VERSION 5.8 ;
BUSBITCHARS "[]" ;
DIVIDERCHAR "/" ;
UNITS
    DATABASE MICRONS 1000 ;
END UNITS

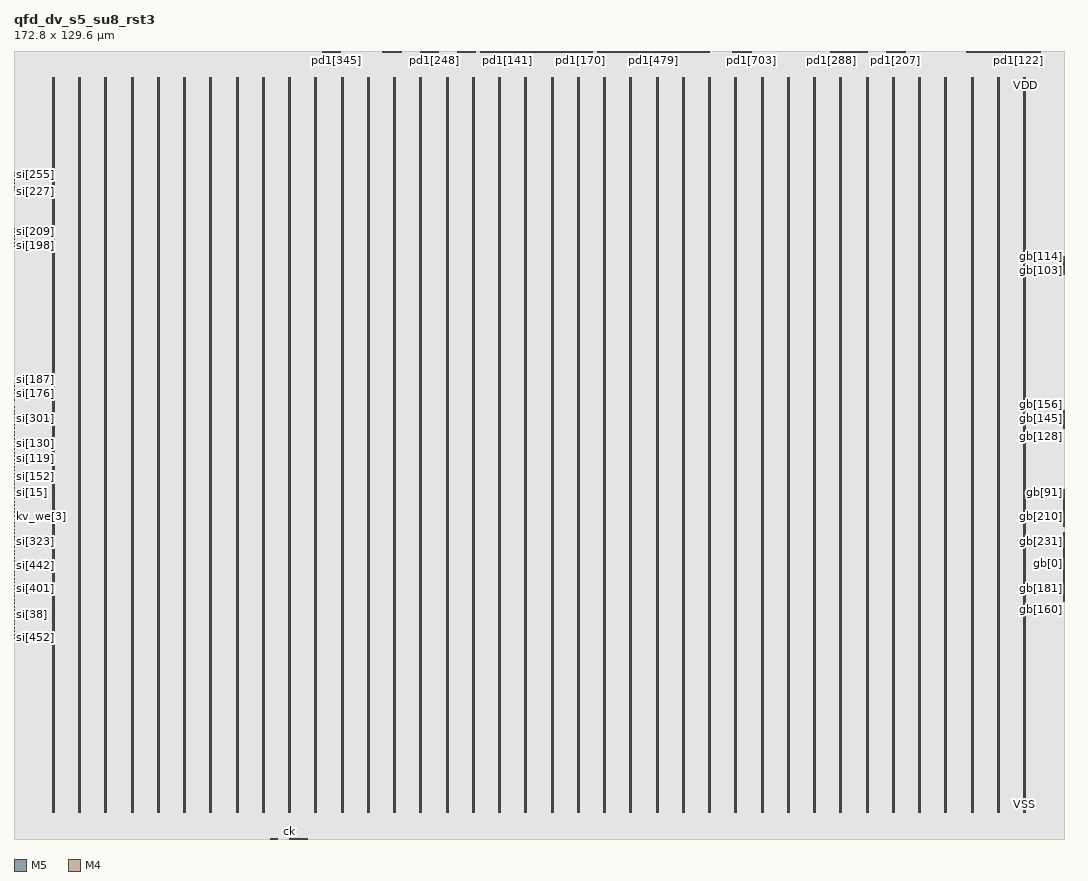
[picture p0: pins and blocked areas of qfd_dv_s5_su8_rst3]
MACRO qfd_dv_s5_su8_rst3
  FOREIGN qfd_dv_s5_su8_rst3 0 0 ;
  CLASS BLOCK ;
  SIZE 172.8 BY 129.6 ;
  PIN ck
    DIRECTION INPUT ;
    USE SIGNAL ;
    PORT
      LAYER M5 ;
        RECT  45.264 0 45.288 0.084 ;
    END
  END ck
  PIN gb[0]
    DIRECTION OUTPUT ;
    USE SIGNAL ;
    PORT
      LAYER M4 ;
        RECT  172.716 45.264 172.8 45.288 ;
    END
  END gb[0]
  PIN gb[100]
    DIRECTION OUTPUT ;
    USE SIGNAL ;
    PORT
      LAYER M4 ;
        RECT  172.716 93.264 172.8 93.288 ;
    END
  END gb[100]
  PIN gb[101]
    DIRECTION OUTPUT ;
    USE SIGNAL ;
    PORT
      LAYER M4 ;
        RECT  172.716 93.36 172.8 93.384 ;
    END
  END gb[101]
  PIN gb[102]
    DIRECTION OUTPUT ;
    USE SIGNAL ;
    PORT
      LAYER M4 ;
        RECT  172.716 93.456 172.8 93.48 ;
    END
  END gb[102]
  PIN gb[103]
    DIRECTION OUTPUT ;
    USE SIGNAL ;
    PORT
      LAYER M4 ;
        RECT  172.716 93.552 172.8 93.576 ;
    END
  END gb[103]
  PIN gb[104]
    DIRECTION OUTPUT ;
    USE SIGNAL ;
    PORT
      LAYER M4 ;
        RECT  172.716 93.648 172.8 93.672 ;
    END
  END gb[104]
  PIN gb[105]
    DIRECTION OUTPUT ;
    USE SIGNAL ;
    PORT
      LAYER M4 ;
        RECT  172.716 93.744 172.8 93.768 ;
    END
  END gb[105]
  PIN gb[106]
    DIRECTION OUTPUT ;
    USE SIGNAL ;
    PORT
      LAYER M4 ;
        RECT  172.716 93.84 172.8 93.864 ;
    END
  END gb[106]
  PIN gb[107]
    DIRECTION OUTPUT ;
    USE SIGNAL ;
    PORT
      LAYER M4 ;
        RECT  172.716 93.936 172.8 93.96 ;
    END
  END gb[107]
  PIN gb[108]
    DIRECTION OUTPUT ;
    USE SIGNAL ;
    PORT
      LAYER M4 ;
        RECT  172.716 94.032 172.8 94.056 ;
    END
  END gb[108]
  PIN gb[109]
    DIRECTION OUTPUT ;
    USE SIGNAL ;
    PORT
      LAYER M4 ;
        RECT  172.716 94.128 172.8 94.152 ;
    END
  END gb[109]
  PIN gb[10]
    DIRECTION OUTPUT ;
    USE SIGNAL ;
    PORT
      LAYER M4 ;
        RECT  172.716 46.224 172.8 46.248 ;
    END
  END gb[10]
  PIN gb[110]
    DIRECTION OUTPUT ;
    USE SIGNAL ;
    PORT
      LAYER M4 ;
        RECT  172.716 94.224 172.8 94.248 ;
    END
  END gb[110]
  PIN gb[111]
    DIRECTION OUTPUT ;
    USE SIGNAL ;
    PORT
      LAYER M4 ;
        RECT  172.716 94.32 172.8 94.344 ;
    END
  END gb[111]
  PIN gb[112]
    DIRECTION OUTPUT ;
    USE SIGNAL ;
    PORT
      LAYER M4 ;
        RECT  172.716 94.416 172.8 94.44 ;
    END
  END gb[112]
  PIN gb[113]
    DIRECTION OUTPUT ;
    USE SIGNAL ;
    PORT
      LAYER M4 ;
        RECT  172.716 94.512 172.8 94.536 ;
    END
  END gb[113]
  PIN gb[114]
    DIRECTION OUTPUT ;
    USE SIGNAL ;
    PORT
      LAYER M4 ;
        RECT  172.716 94.608 172.8 94.632 ;
    END
  END gb[114]
  PIN gb[115]
    DIRECTION OUTPUT ;
    USE SIGNAL ;
    PORT
      LAYER M4 ;
        RECT  172.716 94.704 172.8 94.728 ;
    END
  END gb[115]
  PIN gb[116]
    DIRECTION OUTPUT ;
    USE SIGNAL ;
    PORT
      LAYER M4 ;
        RECT  172.716 94.8 172.8 94.824 ;
    END
  END gb[116]
  PIN gb[117]
    DIRECTION OUTPUT ;
    USE SIGNAL ;
    PORT
      LAYER M4 ;
        RECT  172.716 94.896 172.8 94.92 ;
    END
  END gb[117]
  PIN gb[118]
    DIRECTION OUTPUT ;
    USE SIGNAL ;
    PORT
      LAYER M4 ;
        RECT  172.716 94.992 172.8 95.016 ;
    END
  END gb[118]
  PIN gb[119]
    DIRECTION OUTPUT ;
    USE SIGNAL ;
    PORT
      LAYER M4 ;
        RECT  172.716 95.088 172.8 95.112 ;
    END
  END gb[119]
  PIN gb[11]
    DIRECTION OUTPUT ;
    USE SIGNAL ;
    PORT
      LAYER M4 ;
        RECT  172.716 46.32 172.8 46.344 ;
    END
  END gb[11]
  PIN gb[120]
    DIRECTION OUTPUT ;
    USE SIGNAL ;
    PORT
      LAYER M4 ;
        RECT  172.716 95.184 172.8 95.208 ;
    END
  END gb[120]
  PIN gb[121]
    DIRECTION OUTPUT ;
    USE SIGNAL ;
    PORT
      LAYER M4 ;
        RECT  172.716 95.28 172.8 95.304 ;
    END
  END gb[121]
  PIN gb[122]
    DIRECTION OUTPUT ;
    USE SIGNAL ;
    PORT
      LAYER M4 ;
        RECT  172.716 95.376 172.8 95.4 ;
    END
  END gb[122]
  PIN gb[123]
    DIRECTION OUTPUT ;
    USE SIGNAL ;
    PORT
      LAYER M4 ;
        RECT  172.716 95.472 172.8 95.496 ;
    END
  END gb[123]
  PIN gb[124]
    DIRECTION OUTPUT ;
    USE SIGNAL ;
    PORT
      LAYER M4 ;
        RECT  172.716 95.568 172.8 95.592 ;
    END
  END gb[124]
  PIN gb[125]
    DIRECTION OUTPUT ;
    USE SIGNAL ;
    PORT
      LAYER M4 ;
        RECT  172.716 95.664 172.8 95.688 ;
    END
  END gb[125]
  PIN gb[126]
    DIRECTION OUTPUT ;
    USE SIGNAL ;
    PORT
      LAYER M4 ;
        RECT  172.716 95.76 172.8 95.784 ;
    END
  END gb[126]
  PIN gb[127]
    DIRECTION OUTPUT ;
    USE SIGNAL ;
    PORT
      LAYER M4 ;
        RECT  172.716 95.856 172.8 95.88 ;
    END
  END gb[127]
  PIN gb[128]
    DIRECTION OUTPUT ;
    USE SIGNAL ;
    PORT
      LAYER M4 ;
        RECT  172.716 67.536 172.8 67.56 ;
    END
  END gb[128]
  PIN gb[129]
    DIRECTION OUTPUT ;
    USE SIGNAL ;
    PORT
      LAYER M4 ;
        RECT  172.716 67.632 172.8 67.656 ;
    END
  END gb[129]
  PIN gb[12]
    DIRECTION OUTPUT ;
    USE SIGNAL ;
    PORT
      LAYER M4 ;
        RECT  172.716 46.416 172.8 46.44 ;
    END
  END gb[12]
  PIN gb[130]
    DIRECTION OUTPUT ;
    USE SIGNAL ;
    PORT
      LAYER M4 ;
        RECT  172.716 67.728 172.8 67.752 ;
    END
  END gb[130]
  PIN gb[131]
    DIRECTION OUTPUT ;
    USE SIGNAL ;
    PORT
      LAYER M4 ;
        RECT  172.716 67.824 172.8 67.848 ;
    END
  END gb[131]
  PIN gb[132]
    DIRECTION OUTPUT ;
    USE SIGNAL ;
    PORT
      LAYER M4 ;
        RECT  172.716 67.92 172.8 67.944 ;
    END
  END gb[132]
  PIN gb[133]
    DIRECTION OUTPUT ;
    USE SIGNAL ;
    PORT
      LAYER M4 ;
        RECT  172.716 68.016 172.8 68.04 ;
    END
  END gb[133]
  PIN gb[134]
    DIRECTION OUTPUT ;
    USE SIGNAL ;
    PORT
      LAYER M4 ;
        RECT  172.716 68.112 172.8 68.136 ;
    END
  END gb[134]
  PIN gb[135]
    DIRECTION OUTPUT ;
    USE SIGNAL ;
    PORT
      LAYER M4 ;
        RECT  172.716 68.208 172.8 68.232 ;
    END
  END gb[135]
  PIN gb[136]
    DIRECTION OUTPUT ;
    USE SIGNAL ;
    PORT
      LAYER M4 ;
        RECT  172.716 68.304 172.8 68.328 ;
    END
  END gb[136]
  PIN gb[137]
    DIRECTION OUTPUT ;
    USE SIGNAL ;
    PORT
      LAYER M4 ;
        RECT  172.716 68.4 172.8 68.424 ;
    END
  END gb[137]
  PIN gb[138]
    DIRECTION OUTPUT ;
    USE SIGNAL ;
    PORT
      LAYER M4 ;
        RECT  172.716 68.496 172.8 68.52 ;
    END
  END gb[138]
  PIN gb[139]
    DIRECTION OUTPUT ;
    USE SIGNAL ;
    PORT
      LAYER M4 ;
        RECT  172.716 68.592 172.8 68.616 ;
    END
  END gb[139]
  PIN gb[13]
    DIRECTION OUTPUT ;
    USE SIGNAL ;
    PORT
      LAYER M4 ;
        RECT  172.716 46.512 172.8 46.536 ;
    END
  END gb[13]
  PIN gb[140]
    DIRECTION OUTPUT ;
    USE SIGNAL ;
    PORT
      LAYER M4 ;
        RECT  172.716 68.688 172.8 68.712 ;
    END
  END gb[140]
  PIN gb[141]
    DIRECTION OUTPUT ;
    USE SIGNAL ;
    PORT
      LAYER M4 ;
        RECT  172.716 68.784 172.8 68.808 ;
    END
  END gb[141]
  PIN gb[142]
    DIRECTION OUTPUT ;
    USE SIGNAL ;
    PORT
      LAYER M4 ;
        RECT  172.716 68.88 172.8 68.904 ;
    END
  END gb[142]
  PIN gb[143]
    DIRECTION OUTPUT ;
    USE SIGNAL ;
    PORT
      LAYER M4 ;
        RECT  172.716 68.976 172.8 69 ;
    END
  END gb[143]
  PIN gb[144]
    DIRECTION OUTPUT ;
    USE SIGNAL ;
    PORT
      LAYER M4 ;
        RECT  172.716 69.072 172.8 69.096 ;
    END
  END gb[144]
  PIN gb[145]
    DIRECTION OUTPUT ;
    USE SIGNAL ;
    PORT
      LAYER M4 ;
        RECT  172.716 69.168 172.8 69.192 ;
    END
  END gb[145]
  PIN gb[146]
    DIRECTION OUTPUT ;
    USE SIGNAL ;
    PORT
      LAYER M4 ;
        RECT  172.716 69.264 172.8 69.288 ;
    END
  END gb[146]
  PIN gb[147]
    DIRECTION OUTPUT ;
    USE SIGNAL ;
    PORT
      LAYER M4 ;
        RECT  172.716 69.36 172.8 69.384 ;
    END
  END gb[147]
  PIN gb[148]
    DIRECTION OUTPUT ;
    USE SIGNAL ;
    PORT
      LAYER M4 ;
        RECT  172.716 69.456 172.8 69.48 ;
    END
  END gb[148]
  PIN gb[149]
    DIRECTION OUTPUT ;
    USE SIGNAL ;
    PORT
      LAYER M4 ;
        RECT  172.716 69.552 172.8 69.576 ;
    END
  END gb[149]
  PIN gb[14]
    DIRECTION OUTPUT ;
    USE SIGNAL ;
    PORT
      LAYER M4 ;
        RECT  172.716 46.608 172.8 46.632 ;
    END
  END gb[14]
  PIN gb[150]
    DIRECTION OUTPUT ;
    USE SIGNAL ;
    PORT
      LAYER M4 ;
        RECT  172.716 69.648 172.8 69.672 ;
    END
  END gb[150]
  PIN gb[151]
    DIRECTION OUTPUT ;
    USE SIGNAL ;
    PORT
      LAYER M4 ;
        RECT  172.716 69.744 172.8 69.768 ;
    END
  END gb[151]
  PIN gb[152]
    DIRECTION OUTPUT ;
    USE SIGNAL ;
    PORT
      LAYER M4 ;
        RECT  172.716 69.84 172.8 69.864 ;
    END
  END gb[152]
  PIN gb[153]
    DIRECTION OUTPUT ;
    USE SIGNAL ;
    PORT
      LAYER M4 ;
        RECT  172.716 69.936 172.8 69.96 ;
    END
  END gb[153]
  PIN gb[154]
    DIRECTION OUTPUT ;
    USE SIGNAL ;
    PORT
      LAYER M4 ;
        RECT  172.716 70.032 172.8 70.056 ;
    END
  END gb[154]
  PIN gb[155]
    DIRECTION OUTPUT ;
    USE SIGNAL ;
    PORT
      LAYER M4 ;
        RECT  172.716 70.128 172.8 70.152 ;
    END
  END gb[155]
  PIN gb[156]
    DIRECTION OUTPUT ;
    USE SIGNAL ;
    PORT
      LAYER M4 ;
        RECT  172.716 70.224 172.8 70.248 ;
    END
  END gb[156]
  PIN gb[157]
    DIRECTION OUTPUT ;
    USE SIGNAL ;
    PORT
      LAYER M4 ;
        RECT  172.716 70.32 172.8 70.344 ;
    END
  END gb[157]
  PIN gb[158]
    DIRECTION OUTPUT ;
    USE SIGNAL ;
    PORT
      LAYER M4 ;
        RECT  172.716 70.416 172.8 70.44 ;
    END
  END gb[158]
  PIN gb[159]
    DIRECTION OUTPUT ;
    USE SIGNAL ;
    PORT
      LAYER M4 ;
        RECT  172.716 70.512 172.8 70.536 ;
    END
  END gb[159]
  PIN gb[15]
    DIRECTION OUTPUT ;
    USE SIGNAL ;
    PORT
      LAYER M4 ;
        RECT  172.716 46.704 172.8 46.728 ;
    END
  END gb[15]
  PIN gb[160]
    DIRECTION OUTPUT ;
    USE SIGNAL ;
    PORT
      LAYER M4 ;
        RECT  172.716 39.12 172.8 39.144 ;
    END
  END gb[160]
  PIN gb[161]
    DIRECTION OUTPUT ;
    USE SIGNAL ;
    PORT
      LAYER M4 ;
        RECT  172.716 39.216 172.8 39.24 ;
    END
  END gb[161]
  PIN gb[162]
    DIRECTION OUTPUT ;
    USE SIGNAL ;
    PORT
      LAYER M4 ;
        RECT  172.716 39.312 172.8 39.336 ;
    END
  END gb[162]
  PIN gb[163]
    DIRECTION OUTPUT ;
    USE SIGNAL ;
    PORT
      LAYER M4 ;
        RECT  172.716 39.408 172.8 39.432 ;
    END
  END gb[163]
  PIN gb[164]
    DIRECTION OUTPUT ;
    USE SIGNAL ;
    PORT
      LAYER M4 ;
        RECT  172.716 39.504 172.8 39.528 ;
    END
  END gb[164]
  PIN gb[165]
    DIRECTION OUTPUT ;
    USE SIGNAL ;
    PORT
      LAYER M4 ;
        RECT  172.716 39.6 172.8 39.624 ;
    END
  END gb[165]
  PIN gb[166]
    DIRECTION OUTPUT ;
    USE SIGNAL ;
    PORT
      LAYER M4 ;
        RECT  172.716 39.696 172.8 39.72 ;
    END
  END gb[166]
  PIN gb[167]
    DIRECTION OUTPUT ;
    USE SIGNAL ;
    PORT
      LAYER M4 ;
        RECT  172.716 39.792 172.8 39.816 ;
    END
  END gb[167]
  PIN gb[168]
    DIRECTION OUTPUT ;
    USE SIGNAL ;
    PORT
      LAYER M4 ;
        RECT  172.716 39.888 172.8 39.912 ;
    END
  END gb[168]
  PIN gb[169]
    DIRECTION OUTPUT ;
    USE SIGNAL ;
    PORT
      LAYER M4 ;
        RECT  172.716 39.984 172.8 40.008 ;
    END
  END gb[169]
  PIN gb[16]
    DIRECTION OUTPUT ;
    USE SIGNAL ;
    PORT
      LAYER M4 ;
        RECT  172.716 46.8 172.8 46.824 ;
    END
  END gb[16]
  PIN gb[170]
    DIRECTION OUTPUT ;
    USE SIGNAL ;
    PORT
      LAYER M4 ;
        RECT  172.716 40.08 172.8 40.104 ;
    END
  END gb[170]
  PIN gb[171]
    DIRECTION OUTPUT ;
    USE SIGNAL ;
    PORT
      LAYER M4 ;
        RECT  172.716 40.176 172.8 40.2 ;
    END
  END gb[171]
  PIN gb[172]
    DIRECTION OUTPUT ;
    USE SIGNAL ;
    PORT
      LAYER M4 ;
        RECT  172.716 40.272 172.8 40.296 ;
    END
  END gb[172]
  PIN gb[173]
    DIRECTION OUTPUT ;
    USE SIGNAL ;
    PORT
      LAYER M4 ;
        RECT  172.716 40.368 172.8 40.392 ;
    END
  END gb[173]
  PIN gb[174]
    DIRECTION OUTPUT ;
    USE SIGNAL ;
    PORT
      LAYER M4 ;
        RECT  172.716 40.464 172.8 40.488 ;
    END
  END gb[174]
  PIN gb[175]
    DIRECTION OUTPUT ;
    USE SIGNAL ;
    PORT
      LAYER M4 ;
        RECT  172.716 40.56 172.8 40.584 ;
    END
  END gb[175]
  PIN gb[176]
    DIRECTION OUTPUT ;
    USE SIGNAL ;
    PORT
      LAYER M4 ;
        RECT  172.716 40.656 172.8 40.68 ;
    END
  END gb[176]
  PIN gb[177]
    DIRECTION OUTPUT ;
    USE SIGNAL ;
    PORT
      LAYER M4 ;
        RECT  172.716 40.752 172.8 40.776 ;
    END
  END gb[177]
  PIN gb[178]
    DIRECTION OUTPUT ;
    USE SIGNAL ;
    PORT
      LAYER M4 ;
        RECT  172.716 40.848 172.8 40.872 ;
    END
  END gb[178]
  PIN gb[179]
    DIRECTION OUTPUT ;
    USE SIGNAL ;
    PORT
      LAYER M4 ;
        RECT  172.716 40.944 172.8 40.968 ;
    END
  END gb[179]
  PIN gb[17]
    DIRECTION OUTPUT ;
    USE SIGNAL ;
    PORT
      LAYER M4 ;
        RECT  172.716 46.896 172.8 46.92 ;
    END
  END gb[17]
  PIN gb[180]
    DIRECTION OUTPUT ;
    USE SIGNAL ;
    PORT
      LAYER M4 ;
        RECT  172.716 41.04 172.8 41.064 ;
    END
  END gb[180]
  PIN gb[181]
    DIRECTION OUTPUT ;
    USE SIGNAL ;
    PORT
      LAYER M4 ;
        RECT  172.716 41.136 172.8 41.16 ;
    END
  END gb[181]
  PIN gb[182]
    DIRECTION OUTPUT ;
    USE SIGNAL ;
    PORT
      LAYER M4 ;
        RECT  172.716 41.232 172.8 41.256 ;
    END
  END gb[182]
  PIN gb[183]
    DIRECTION OUTPUT ;
    USE SIGNAL ;
    PORT
      LAYER M4 ;
        RECT  172.716 41.328 172.8 41.352 ;
    END
  END gb[183]
  PIN gb[184]
    DIRECTION OUTPUT ;
    USE SIGNAL ;
    PORT
      LAYER M4 ;
        RECT  172.716 41.424 172.8 41.448 ;
    END
  END gb[184]
  PIN gb[185]
    DIRECTION OUTPUT ;
    USE SIGNAL ;
    PORT
      LAYER M4 ;
        RECT  172.716 41.52 172.8 41.544 ;
    END
  END gb[185]
  PIN gb[186]
    DIRECTION OUTPUT ;
    USE SIGNAL ;
    PORT
      LAYER M4 ;
        RECT  172.716 41.616 172.8 41.64 ;
    END
  END gb[186]
  PIN gb[187]
    DIRECTION OUTPUT ;
    USE SIGNAL ;
    PORT
      LAYER M4 ;
        RECT  172.716 41.712 172.8 41.736 ;
    END
  END gb[187]
  PIN gb[188]
    DIRECTION OUTPUT ;
    USE SIGNAL ;
    PORT
      LAYER M4 ;
        RECT  172.716 41.808 172.8 41.832 ;
    END
  END gb[188]
  PIN gb[189]
    DIRECTION OUTPUT ;
    USE SIGNAL ;
    PORT
      LAYER M4 ;
        RECT  172.716 41.904 172.8 41.928 ;
    END
  END gb[189]
  PIN gb[18]
    DIRECTION OUTPUT ;
    USE SIGNAL ;
    PORT
      LAYER M4 ;
        RECT  172.716 46.992 172.8 47.016 ;
    END
  END gb[18]
  PIN gb[190]
    DIRECTION OUTPUT ;
    USE SIGNAL ;
    PORT
      LAYER M4 ;
        RECT  172.716 42 172.8 42.024 ;
    END
  END gb[190]
  PIN gb[191]
    DIRECTION OUTPUT ;
    USE SIGNAL ;
    PORT
      LAYER M4 ;
        RECT  172.716 42.096 172.8 42.12 ;
    END
  END gb[191]
  PIN gb[192]
    DIRECTION OUTPUT ;
    USE SIGNAL ;
    PORT
      LAYER M4 ;
        RECT  172.716 51.408 172.8 51.432 ;
    END
  END gb[192]
  PIN gb[193]
    DIRECTION OUTPUT ;
    USE SIGNAL ;
    PORT
      LAYER M4 ;
        RECT  172.716 51.504 172.8 51.528 ;
    END
  END gb[193]
  PIN gb[194]
    DIRECTION OUTPUT ;
    USE SIGNAL ;
    PORT
      LAYER M4 ;
        RECT  172.716 51.6 172.8 51.624 ;
    END
  END gb[194]
  PIN gb[195]
    DIRECTION OUTPUT ;
    USE SIGNAL ;
    PORT
      LAYER M4 ;
        RECT  172.716 51.696 172.8 51.72 ;
    END
  END gb[195]
  PIN gb[196]
    DIRECTION OUTPUT ;
    USE SIGNAL ;
    PORT
      LAYER M4 ;
        RECT  172.716 51.792 172.8 51.816 ;
    END
  END gb[196]
  PIN gb[197]
    DIRECTION OUTPUT ;
    USE SIGNAL ;
    PORT
      LAYER M4 ;
        RECT  172.716 51.888 172.8 51.912 ;
    END
  END gb[197]
  PIN gb[198]
    DIRECTION OUTPUT ;
    USE SIGNAL ;
    PORT
      LAYER M4 ;
        RECT  172.716 51.984 172.8 52.008 ;
    END
  END gb[198]
  PIN gb[199]
    DIRECTION OUTPUT ;
    USE SIGNAL ;
    PORT
      LAYER M4 ;
        RECT  172.716 52.08 172.8 52.104 ;
    END
  END gb[199]
  PIN gb[19]
    DIRECTION OUTPUT ;
    USE SIGNAL ;
    PORT
      LAYER M4 ;
        RECT  172.716 47.088 172.8 47.112 ;
    END
  END gb[19]
  PIN gb[1]
    DIRECTION OUTPUT ;
    USE SIGNAL ;
    PORT
      LAYER M4 ;
        RECT  172.716 45.36 172.8 45.384 ;
    END
  END gb[1]
  PIN gb[200]
    DIRECTION OUTPUT ;
    USE SIGNAL ;
    PORT
      LAYER M4 ;
        RECT  172.716 52.176 172.8 52.2 ;
    END
  END gb[200]
  PIN gb[201]
    DIRECTION OUTPUT ;
    USE SIGNAL ;
    PORT
      LAYER M4 ;
        RECT  172.716 52.272 172.8 52.296 ;
    END
  END gb[201]
  PIN gb[202]
    DIRECTION OUTPUT ;
    USE SIGNAL ;
    PORT
      LAYER M4 ;
        RECT  172.716 52.368 172.8 52.392 ;
    END
  END gb[202]
  PIN gb[203]
    DIRECTION OUTPUT ;
    USE SIGNAL ;
    PORT
      LAYER M4 ;
        RECT  172.716 52.464 172.8 52.488 ;
    END
  END gb[203]
  PIN gb[204]
    DIRECTION OUTPUT ;
    USE SIGNAL ;
    PORT
      LAYER M4 ;
        RECT  172.716 52.56 172.8 52.584 ;
    END
  END gb[204]
  PIN gb[205]
    DIRECTION OUTPUT ;
    USE SIGNAL ;
    PORT
      LAYER M4 ;
        RECT  172.716 52.656 172.8 52.68 ;
    END
  END gb[205]
  PIN gb[206]
    DIRECTION OUTPUT ;
    USE SIGNAL ;
    PORT
      LAYER M4 ;
        RECT  172.716 52.752 172.8 52.776 ;
    END
  END gb[206]
  PIN gb[207]
    DIRECTION OUTPUT ;
    USE SIGNAL ;
    PORT
      LAYER M4 ;
        RECT  172.716 52.848 172.8 52.872 ;
    END
  END gb[207]
  PIN gb[208]
    DIRECTION OUTPUT ;
    USE SIGNAL ;
    PORT
      LAYER M4 ;
        RECT  172.716 52.944 172.8 52.968 ;
    END
  END gb[208]
  PIN gb[209]
    DIRECTION OUTPUT ;
    USE SIGNAL ;
    PORT
      LAYER M4 ;
        RECT  172.716 53.04 172.8 53.064 ;
    END
  END gb[209]
  PIN gb[20]
    DIRECTION OUTPUT ;
    USE SIGNAL ;
    PORT
      LAYER M4 ;
        RECT  172.716 47.184 172.8 47.208 ;
    END
  END gb[20]
  PIN gb[210]
    DIRECTION OUTPUT ;
    USE SIGNAL ;
    PORT
      LAYER M4 ;
        RECT  172.716 53.136 172.8 53.16 ;
    END
  END gb[210]
  PIN gb[211]
    DIRECTION OUTPUT ;
    USE SIGNAL ;
    PORT
      LAYER M4 ;
        RECT  172.716 53.232 172.8 53.256 ;
    END
  END gb[211]
  PIN gb[212]
    DIRECTION OUTPUT ;
    USE SIGNAL ;
    PORT
      LAYER M4 ;
        RECT  172.716 53.328 172.8 53.352 ;
    END
  END gb[212]
  PIN gb[213]
    DIRECTION OUTPUT ;
    USE SIGNAL ;
    PORT
      LAYER M4 ;
        RECT  172.716 53.424 172.8 53.448 ;
    END
  END gb[213]
  PIN gb[214]
    DIRECTION OUTPUT ;
    USE SIGNAL ;
    PORT
      LAYER M4 ;
        RECT  172.716 53.52 172.8 53.544 ;
    END
  END gb[214]
  PIN gb[215]
    DIRECTION OUTPUT ;
    USE SIGNAL ;
    PORT
      LAYER M4 ;
        RECT  172.716 53.616 172.8 53.64 ;
    END
  END gb[215]
  PIN gb[216]
    DIRECTION OUTPUT ;
    USE SIGNAL ;
    PORT
      LAYER M4 ;
        RECT  172.716 53.712 172.8 53.736 ;
    END
  END gb[216]
  PIN gb[217]
    DIRECTION OUTPUT ;
    USE SIGNAL ;
    PORT
      LAYER M4 ;
        RECT  172.716 53.808 172.8 53.832 ;
    END
  END gb[217]
  PIN gb[218]
    DIRECTION OUTPUT ;
    USE SIGNAL ;
    PORT
      LAYER M4 ;
        RECT  172.716 53.904 172.8 53.928 ;
    END
  END gb[218]
  PIN gb[219]
    DIRECTION OUTPUT ;
    USE SIGNAL ;
    PORT
      LAYER M4 ;
        RECT  172.716 54 172.8 54.024 ;
    END
  END gb[219]
  PIN gb[21]
    DIRECTION OUTPUT ;
    USE SIGNAL ;
    PORT
      LAYER M4 ;
        RECT  172.716 47.28 172.8 47.304 ;
    END
  END gb[21]
  PIN gb[220]
    DIRECTION OUTPUT ;
    USE SIGNAL ;
    PORT
      LAYER M4 ;
        RECT  172.716 54.096 172.8 54.12 ;
    END
  END gb[220]
  PIN gb[221]
    DIRECTION OUTPUT ;
    USE SIGNAL ;
    PORT
      LAYER M4 ;
        RECT  172.716 54.192 172.8 54.216 ;
    END
  END gb[221]
  PIN gb[222]
    DIRECTION OUTPUT ;
    USE SIGNAL ;
    PORT
      LAYER M4 ;
        RECT  172.716 54.288 172.8 54.312 ;
    END
  END gb[222]
  PIN gb[223]
    DIRECTION OUTPUT ;
    USE SIGNAL ;
    PORT
      LAYER M4 ;
        RECT  172.716 54.384 172.8 54.408 ;
    END
  END gb[223]
  PIN gb[224]
    DIRECTION OUTPUT ;
    USE SIGNAL ;
    PORT
      LAYER M4 ;
        RECT  172.716 48.336 172.8 48.36 ;
    END
  END gb[224]
  PIN gb[225]
    DIRECTION OUTPUT ;
    USE SIGNAL ;
    PORT
      LAYER M4 ;
        RECT  172.716 48.432 172.8 48.456 ;
    END
  END gb[225]
  PIN gb[226]
    DIRECTION OUTPUT ;
    USE SIGNAL ;
    PORT
      LAYER M4 ;
        RECT  172.716 48.528 172.8 48.552 ;
    END
  END gb[226]
  PIN gb[227]
    DIRECTION OUTPUT ;
    USE SIGNAL ;
    PORT
      LAYER M4 ;
        RECT  172.716 48.624 172.8 48.648 ;
    END
  END gb[227]
  PIN gb[228]
    DIRECTION OUTPUT ;
    USE SIGNAL ;
    PORT
      LAYER M4 ;
        RECT  172.716 48.72 172.8 48.744 ;
    END
  END gb[228]
  PIN gb[229]
    DIRECTION OUTPUT ;
    USE SIGNAL ;
    PORT
      LAYER M4 ;
        RECT  172.716 48.816 172.8 48.84 ;
    END
  END gb[229]
  PIN gb[22]
    DIRECTION OUTPUT ;
    USE SIGNAL ;
    PORT
      LAYER M4 ;
        RECT  172.716 47.376 172.8 47.4 ;
    END
  END gb[22]
  PIN gb[230]
    DIRECTION OUTPUT ;
    USE SIGNAL ;
    PORT
      LAYER M4 ;
        RECT  172.716 48.912 172.8 48.936 ;
    END
  END gb[230]
  PIN gb[231]
    DIRECTION OUTPUT ;
    USE SIGNAL ;
    PORT
      LAYER M4 ;
        RECT  172.716 49.008 172.8 49.032 ;
    END
  END gb[231]
  PIN gb[232]
    DIRECTION OUTPUT ;
    USE SIGNAL ;
    PORT
      LAYER M4 ;
        RECT  172.716 49.104 172.8 49.128 ;
    END
  END gb[232]
  PIN gb[233]
    DIRECTION OUTPUT ;
    USE SIGNAL ;
    PORT
      LAYER M4 ;
        RECT  172.716 49.2 172.8 49.224 ;
    END
  END gb[233]
  PIN gb[234]
    DIRECTION OUTPUT ;
    USE SIGNAL ;
    PORT
      LAYER M4 ;
        RECT  172.716 49.296 172.8 49.32 ;
    END
  END gb[234]
  PIN gb[235]
    DIRECTION OUTPUT ;
    USE SIGNAL ;
    PORT
      LAYER M4 ;
        RECT  172.716 49.392 172.8 49.416 ;
    END
  END gb[235]
  PIN gb[236]
    DIRECTION OUTPUT ;
    USE SIGNAL ;
    PORT
      LAYER M4 ;
        RECT  172.716 49.488 172.8 49.512 ;
    END
  END gb[236]
  PIN gb[237]
    DIRECTION OUTPUT ;
    USE SIGNAL ;
    PORT
      LAYER M4 ;
        RECT  172.716 49.584 172.8 49.608 ;
    END
  END gb[237]
  PIN gb[238]
    DIRECTION OUTPUT ;
    USE SIGNAL ;
    PORT
      LAYER M4 ;
        RECT  172.716 49.68 172.8 49.704 ;
    END
  END gb[238]
  PIN gb[239]
    DIRECTION OUTPUT ;
    USE SIGNAL ;
    PORT
      LAYER M4 ;
        RECT  172.716 49.776 172.8 49.8 ;
    END
  END gb[239]
  PIN gb[23]
    DIRECTION OUTPUT ;
    USE SIGNAL ;
    PORT
      LAYER M4 ;
        RECT  172.716 47.472 172.8 47.496 ;
    END
  END gb[23]
  PIN gb[240]
    DIRECTION OUTPUT ;
    USE SIGNAL ;
    PORT
      LAYER M4 ;
        RECT  172.716 49.872 172.8 49.896 ;
    END
  END gb[240]
  PIN gb[241]
    DIRECTION OUTPUT ;
    USE SIGNAL ;
    PORT
      LAYER M4 ;
        RECT  172.716 49.968 172.8 49.992 ;
    END
  END gb[241]
  PIN gb[242]
    DIRECTION OUTPUT ;
    USE SIGNAL ;
    PORT
      LAYER M4 ;
        RECT  172.716 50.064 172.8 50.088 ;
    END
  END gb[242]
  PIN gb[243]
    DIRECTION OUTPUT ;
    USE SIGNAL ;
    PORT
      LAYER M4 ;
        RECT  172.716 50.16 172.8 50.184 ;
    END
  END gb[243]
  PIN gb[24]
    DIRECTION OUTPUT ;
    USE SIGNAL ;
    PORT
      LAYER M4 ;
        RECT  172.716 47.568 172.8 47.592 ;
    END
  END gb[24]
  PIN gb[25]
    DIRECTION OUTPUT ;
    USE SIGNAL ;
    PORT
      LAYER M4 ;
        RECT  172.716 47.664 172.8 47.688 ;
    END
  END gb[25]
  PIN gb[26]
    DIRECTION OUTPUT ;
    USE SIGNAL ;
    PORT
      LAYER M4 ;
        RECT  172.716 47.76 172.8 47.784 ;
    END
  END gb[26]
  PIN gb[27]
    DIRECTION OUTPUT ;
    USE SIGNAL ;
    PORT
      LAYER M4 ;
        RECT  172.716 47.856 172.8 47.88 ;
    END
  END gb[27]
  PIN gb[28]
    DIRECTION OUTPUT ;
    USE SIGNAL ;
    PORT
      LAYER M4 ;
        RECT  172.716 47.952 172.8 47.976 ;
    END
  END gb[28]
  PIN gb[29]
    DIRECTION OUTPUT ;
    USE SIGNAL ;
    PORT
      LAYER M4 ;
        RECT  172.716 48.048 172.8 48.072 ;
    END
  END gb[29]
  PIN gb[2]
    DIRECTION OUTPUT ;
    USE SIGNAL ;
    PORT
      LAYER M4 ;
        RECT  172.716 45.456 172.8 45.48 ;
    END
  END gb[2]
  PIN gb[30]
    DIRECTION OUTPUT ;
    USE SIGNAL ;
    PORT
      LAYER M4 ;
        RECT  172.716 48.144 172.8 48.168 ;
    END
  END gb[30]
  PIN gb[31]
    DIRECTION OUTPUT ;
    USE SIGNAL ;
    PORT
      LAYER M4 ;
        RECT  172.716 48.24 172.8 48.264 ;
    END
  END gb[31]
  PIN gb[32]
    DIRECTION OUTPUT ;
    USE SIGNAL ;
    PORT
      LAYER M4 ;
        RECT  172.716 42.192 172.8 42.216 ;
    END
  END gb[32]
  PIN gb[33]
    DIRECTION OUTPUT ;
    USE SIGNAL ;
    PORT
      LAYER M4 ;
        RECT  172.716 42.288 172.8 42.312 ;
    END
  END gb[33]
  PIN gb[34]
    DIRECTION OUTPUT ;
    USE SIGNAL ;
    PORT
      LAYER M4 ;
        RECT  172.716 42.384 172.8 42.408 ;
    END
  END gb[34]
  PIN gb[35]
    DIRECTION OUTPUT ;
    USE SIGNAL ;
    PORT
      LAYER M4 ;
        RECT  172.716 42.48 172.8 42.504 ;
    END
  END gb[35]
  PIN gb[36]
    DIRECTION OUTPUT ;
    USE SIGNAL ;
    PORT
      LAYER M4 ;
        RECT  172.716 42.576 172.8 42.6 ;
    END
  END gb[36]
  PIN gb[37]
    DIRECTION OUTPUT ;
    USE SIGNAL ;
    PORT
      LAYER M4 ;
        RECT  172.716 42.672 172.8 42.696 ;
    END
  END gb[37]
  PIN gb[38]
    DIRECTION OUTPUT ;
    USE SIGNAL ;
    PORT
      LAYER M4 ;
        RECT  172.716 42.768 172.8 42.792 ;
    END
  END gb[38]
  PIN gb[39]
    DIRECTION OUTPUT ;
    USE SIGNAL ;
    PORT
      LAYER M4 ;
        RECT  172.716 42.864 172.8 42.888 ;
    END
  END gb[39]
  PIN gb[3]
    DIRECTION OUTPUT ;
    USE SIGNAL ;
    PORT
      LAYER M4 ;
        RECT  172.716 45.552 172.8 45.576 ;
    END
  END gb[3]
  PIN gb[40]
    DIRECTION OUTPUT ;
    USE SIGNAL ;
    PORT
      LAYER M4 ;
        RECT  172.716 42.96 172.8 42.984 ;
    END
  END gb[40]
  PIN gb[41]
    DIRECTION OUTPUT ;
    USE SIGNAL ;
    PORT
      LAYER M4 ;
        RECT  172.716 43.056 172.8 43.08 ;
    END
  END gb[41]
  PIN gb[42]
    DIRECTION OUTPUT ;
    USE SIGNAL ;
    PORT
      LAYER M4 ;
        RECT  172.716 43.152 172.8 43.176 ;
    END
  END gb[42]
  PIN gb[43]
    DIRECTION OUTPUT ;
    USE SIGNAL ;
    PORT
      LAYER M4 ;
        RECT  172.716 43.248 172.8 43.272 ;
    END
  END gb[43]
  PIN gb[44]
    DIRECTION OUTPUT ;
    USE SIGNAL ;
    PORT
      LAYER M4 ;
        RECT  172.716 43.344 172.8 43.368 ;
    END
  END gb[44]
  PIN gb[45]
    DIRECTION OUTPUT ;
    USE SIGNAL ;
    PORT
      LAYER M4 ;
        RECT  172.716 43.44 172.8 43.464 ;
    END
  END gb[45]
  PIN gb[46]
    DIRECTION OUTPUT ;
    USE SIGNAL ;
    PORT
      LAYER M4 ;
        RECT  172.716 43.536 172.8 43.56 ;
    END
  END gb[46]
  PIN gb[47]
    DIRECTION OUTPUT ;
    USE SIGNAL ;
    PORT
      LAYER M4 ;
        RECT  172.716 43.632 172.8 43.656 ;
    END
  END gb[47]
  PIN gb[48]
    DIRECTION OUTPUT ;
    USE SIGNAL ;
    PORT
      LAYER M4 ;
        RECT  172.716 43.728 172.8 43.752 ;
    END
  END gb[48]
  PIN gb[49]
    DIRECTION OUTPUT ;
    USE SIGNAL ;
    PORT
      LAYER M4 ;
        RECT  172.716 43.824 172.8 43.848 ;
    END
  END gb[49]
  PIN gb[4]
    DIRECTION OUTPUT ;
    USE SIGNAL ;
    PORT
      LAYER M4 ;
        RECT  172.716 45.648 172.8 45.672 ;
    END
  END gb[4]
  PIN gb[50]
    DIRECTION OUTPUT ;
    USE SIGNAL ;
    PORT
      LAYER M4 ;
        RECT  172.716 43.92 172.8 43.944 ;
    END
  END gb[50]
  PIN gb[51]
    DIRECTION OUTPUT ;
    USE SIGNAL ;
    PORT
      LAYER M4 ;
        RECT  172.716 44.016 172.8 44.04 ;
    END
  END gb[51]
  PIN gb[52]
    DIRECTION OUTPUT ;
    USE SIGNAL ;
    PORT
      LAYER M4 ;
        RECT  172.716 44.112 172.8 44.136 ;
    END
  END gb[52]
  PIN gb[53]
    DIRECTION OUTPUT ;
    USE SIGNAL ;
    PORT
      LAYER M4 ;
        RECT  172.716 44.208 172.8 44.232 ;
    END
  END gb[53]
  PIN gb[54]
    DIRECTION OUTPUT ;
    USE SIGNAL ;
    PORT
      LAYER M4 ;
        RECT  172.716 44.304 172.8 44.328 ;
    END
  END gb[54]
  PIN gb[55]
    DIRECTION OUTPUT ;
    USE SIGNAL ;
    PORT
      LAYER M4 ;
        RECT  172.716 44.4 172.8 44.424 ;
    END
  END gb[55]
  PIN gb[56]
    DIRECTION OUTPUT ;
    USE SIGNAL ;
    PORT
      LAYER M4 ;
        RECT  172.716 44.496 172.8 44.52 ;
    END
  END gb[56]
  PIN gb[57]
    DIRECTION OUTPUT ;
    USE SIGNAL ;
    PORT
      LAYER M4 ;
        RECT  172.716 44.592 172.8 44.616 ;
    END
  END gb[57]
  PIN gb[58]
    DIRECTION OUTPUT ;
    USE SIGNAL ;
    PORT
      LAYER M4 ;
        RECT  172.716 44.688 172.8 44.712 ;
    END
  END gb[58]
  PIN gb[59]
    DIRECTION OUTPUT ;
    USE SIGNAL ;
    PORT
      LAYER M4 ;
        RECT  172.716 44.784 172.8 44.808 ;
    END
  END gb[59]
  PIN gb[5]
    DIRECTION OUTPUT ;
    USE SIGNAL ;
    PORT
      LAYER M4 ;
        RECT  172.716 45.744 172.8 45.768 ;
    END
  END gb[5]
  PIN gb[60]
    DIRECTION OUTPUT ;
    USE SIGNAL ;
    PORT
      LAYER M4 ;
        RECT  172.716 44.88 172.8 44.904 ;
    END
  END gb[60]
  PIN gb[61]
    DIRECTION OUTPUT ;
    USE SIGNAL ;
    PORT
      LAYER M4 ;
        RECT  172.716 44.976 172.8 45 ;
    END
  END gb[61]
  PIN gb[62]
    DIRECTION OUTPUT ;
    USE SIGNAL ;
    PORT
      LAYER M4 ;
        RECT  172.716 45.072 172.8 45.096 ;
    END
  END gb[62]
  PIN gb[63]
    DIRECTION OUTPUT ;
    USE SIGNAL ;
    PORT
      LAYER M4 ;
        RECT  172.716 45.168 172.8 45.192 ;
    END
  END gb[63]
  PIN gb[64]
    DIRECTION OUTPUT ;
    USE SIGNAL ;
    PORT
      LAYER M4 ;
        RECT  172.716 54.48 172.8 54.504 ;
    END
  END gb[64]
  PIN gb[65]
    DIRECTION OUTPUT ;
    USE SIGNAL ;
    PORT
      LAYER M4 ;
        RECT  172.716 54.576 172.8 54.6 ;
    END
  END gb[65]
  PIN gb[66]
    DIRECTION OUTPUT ;
    USE SIGNAL ;
    PORT
      LAYER M4 ;
        RECT  172.716 54.672 172.8 54.696 ;
    END
  END gb[66]
  PIN gb[67]
    DIRECTION OUTPUT ;
    USE SIGNAL ;
    PORT
      LAYER M4 ;
        RECT  172.716 54.768 172.8 54.792 ;
    END
  END gb[67]
  PIN gb[68]
    DIRECTION OUTPUT ;
    USE SIGNAL ;
    PORT
      LAYER M4 ;
        RECT  172.716 54.864 172.8 54.888 ;
    END
  END gb[68]
  PIN gb[69]
    DIRECTION OUTPUT ;
    USE SIGNAL ;
    PORT
      LAYER M4 ;
        RECT  172.716 54.96 172.8 54.984 ;
    END
  END gb[69]
  PIN gb[6]
    DIRECTION OUTPUT ;
    USE SIGNAL ;
    PORT
      LAYER M4 ;
        RECT  172.716 45.84 172.8 45.864 ;
    END
  END gb[6]
  PIN gb[70]
    DIRECTION OUTPUT ;
    USE SIGNAL ;
    PORT
      LAYER M4 ;
        RECT  172.716 55.056 172.8 55.08 ;
    END
  END gb[70]
  PIN gb[71]
    DIRECTION OUTPUT ;
    USE SIGNAL ;
    PORT
      LAYER M4 ;
        RECT  172.716 55.152 172.8 55.176 ;
    END
  END gb[71]
  PIN gb[72]
    DIRECTION OUTPUT ;
    USE SIGNAL ;
    PORT
      LAYER M4 ;
        RECT  172.716 55.248 172.8 55.272 ;
    END
  END gb[72]
  PIN gb[73]
    DIRECTION OUTPUT ;
    USE SIGNAL ;
    PORT
      LAYER M4 ;
        RECT  172.716 55.344 172.8 55.368 ;
    END
  END gb[73]
  PIN gb[74]
    DIRECTION OUTPUT ;
    USE SIGNAL ;
    PORT
      LAYER M4 ;
        RECT  172.716 55.44 172.8 55.464 ;
    END
  END gb[74]
  PIN gb[75]
    DIRECTION OUTPUT ;
    USE SIGNAL ;
    PORT
      LAYER M4 ;
        RECT  172.716 55.536 172.8 55.56 ;
    END
  END gb[75]
  PIN gb[76]
    DIRECTION OUTPUT ;
    USE SIGNAL ;
    PORT
      LAYER M4 ;
        RECT  172.716 55.632 172.8 55.656 ;
    END
  END gb[76]
  PIN gb[77]
    DIRECTION OUTPUT ;
    USE SIGNAL ;
    PORT
      LAYER M4 ;
        RECT  172.716 55.728 172.8 55.752 ;
    END
  END gb[77]
  PIN gb[78]
    DIRECTION OUTPUT ;
    USE SIGNAL ;
    PORT
      LAYER M4 ;
        RECT  172.716 55.824 172.8 55.848 ;
    END
  END gb[78]
  PIN gb[79]
    DIRECTION OUTPUT ;
    USE SIGNAL ;
    PORT
      LAYER M4 ;
        RECT  172.716 55.92 172.8 55.944 ;
    END
  END gb[79]
  PIN gb[7]
    DIRECTION OUTPUT ;
    USE SIGNAL ;
    PORT
      LAYER M4 ;
        RECT  172.716 45.936 172.8 45.96 ;
    END
  END gb[7]
  PIN gb[80]
    DIRECTION OUTPUT ;
    USE SIGNAL ;
    PORT
      LAYER M4 ;
        RECT  172.716 56.016 172.8 56.04 ;
    END
  END gb[80]
  PIN gb[81]
    DIRECTION OUTPUT ;
    USE SIGNAL ;
    PORT
      LAYER M4 ;
        RECT  172.716 56.112 172.8 56.136 ;
    END
  END gb[81]
  PIN gb[82]
    DIRECTION OUTPUT ;
    USE SIGNAL ;
    PORT
      LAYER M4 ;
        RECT  172.716 56.208 172.8 56.232 ;
    END
  END gb[82]
  PIN gb[83]
    DIRECTION OUTPUT ;
    USE SIGNAL ;
    PORT
      LAYER M4 ;
        RECT  172.716 56.304 172.8 56.328 ;
    END
  END gb[83]
  PIN gb[84]
    DIRECTION OUTPUT ;
    USE SIGNAL ;
    PORT
      LAYER M4 ;
        RECT  172.716 56.4 172.8 56.424 ;
    END
  END gb[84]
  PIN gb[85]
    DIRECTION OUTPUT ;
    USE SIGNAL ;
    PORT
      LAYER M4 ;
        RECT  172.716 56.496 172.8 56.52 ;
    END
  END gb[85]
  PIN gb[86]
    DIRECTION OUTPUT ;
    USE SIGNAL ;
    PORT
      LAYER M4 ;
        RECT  172.716 56.592 172.8 56.616 ;
    END
  END gb[86]
  PIN gb[87]
    DIRECTION OUTPUT ;
    USE SIGNAL ;
    PORT
      LAYER M4 ;
        RECT  172.716 56.688 172.8 56.712 ;
    END
  END gb[87]
  PIN gb[88]
    DIRECTION OUTPUT ;
    USE SIGNAL ;
    PORT
      LAYER M4 ;
        RECT  172.716 56.784 172.8 56.808 ;
    END
  END gb[88]
  PIN gb[89]
    DIRECTION OUTPUT ;
    USE SIGNAL ;
    PORT
      LAYER M4 ;
        RECT  172.716 56.88 172.8 56.904 ;
    END
  END gb[89]
  PIN gb[8]
    DIRECTION OUTPUT ;
    USE SIGNAL ;
    PORT
      LAYER M4 ;
        RECT  172.716 46.032 172.8 46.056 ;
    END
  END gb[8]
  PIN gb[90]
    DIRECTION OUTPUT ;
    USE SIGNAL ;
    PORT
      LAYER M4 ;
        RECT  172.716 56.976 172.8 57 ;
    END
  END gb[90]
  PIN gb[91]
    DIRECTION OUTPUT ;
    USE SIGNAL ;
    PORT
      LAYER M4 ;
        RECT  172.716 57.072 172.8 57.096 ;
    END
  END gb[91]
  PIN gb[92]
    DIRECTION OUTPUT ;
    USE SIGNAL ;
    PORT
      LAYER M4 ;
        RECT  172.716 57.168 172.8 57.192 ;
    END
  END gb[92]
  PIN gb[93]
    DIRECTION OUTPUT ;
    USE SIGNAL ;
    PORT
      LAYER M4 ;
        RECT  172.716 57.264 172.8 57.288 ;
    END
  END gb[93]
  PIN gb[94]
    DIRECTION OUTPUT ;
    USE SIGNAL ;
    PORT
      LAYER M4 ;
        RECT  172.716 57.36 172.8 57.384 ;
    END
  END gb[94]
  PIN gb[95]
    DIRECTION OUTPUT ;
    USE SIGNAL ;
    PORT
      LAYER M4 ;
        RECT  172.716 57.456 172.8 57.48 ;
    END
  END gb[95]
  PIN gb[96]
    DIRECTION OUTPUT ;
    USE SIGNAL ;
    PORT
      LAYER M4 ;
        RECT  172.716 92.88 172.8 92.904 ;
    END
  END gb[96]
  PIN gb[97]
    DIRECTION OUTPUT ;
    USE SIGNAL ;
    PORT
      LAYER M4 ;
        RECT  172.716 92.976 172.8 93 ;
    END
  END gb[97]
  PIN gb[98]
    DIRECTION OUTPUT ;
    USE SIGNAL ;
    PORT
      LAYER M4 ;
        RECT  172.716 93.072 172.8 93.096 ;
    END
  END gb[98]
  PIN gb[99]
    DIRECTION OUTPUT ;
    USE SIGNAL ;
    PORT
      LAYER M4 ;
        RECT  172.716 93.168 172.8 93.192 ;
    END
  END gb[99]
  PIN gb[9]
    DIRECTION OUTPUT ;
    USE SIGNAL ;
    PORT
      LAYER M4 ;
        RECT  172.716 46.128 172.8 46.152 ;
    END
  END gb[9]
  PIN gv[0]
    DIRECTION OUTPUT ;
    USE SIGNAL ;
    PORT
      LAYER M4 ;
        RECT  172.716 50.256 172.8 50.28 ;
    END
  END gv[0]
  PIN gv[1]
    DIRECTION OUTPUT ;
    USE SIGNAL ;
    PORT
      LAYER M4 ;
        RECT  172.716 50.352 172.8 50.376 ;
    END
  END gv[1]
  PIN gv[2]
    DIRECTION OUTPUT ;
    USE SIGNAL ;
    PORT
      LAYER M4 ;
        RECT  172.716 50.448 172.8 50.472 ;
    END
  END gv[2]
  PIN kv_we[0]
    DIRECTION INPUT ;
    USE SIGNAL ;
    PORT
      LAYER M4 ;
        RECT  0 52.848 0.084 52.872 ;
    END
  END kv_we[0]
  PIN kv_we[1]
    DIRECTION INPUT ;
    USE SIGNAL ;
    PORT
      LAYER M4 ;
        RECT  0 52.944 0.084 52.968 ;
    END
  END kv_we[1]
  PIN kv_we[2]
    DIRECTION INPUT ;
    USE SIGNAL ;
    PORT
      LAYER M4 ;
        RECT  0 53.04 0.084 53.064 ;
    END
  END kv_we[2]
  PIN kv_we[3]
    DIRECTION INPUT ;
    USE SIGNAL ;
    PORT
      LAYER M4 ;
        RECT  0 53.136 0.084 53.16 ;
    END
  END kv_we[3]
  PIN kv_we[4]
    DIRECTION INPUT ;
    USE SIGNAL ;
    PORT
      LAYER M4 ;
        RECT  0 53.232 0.084 53.256 ;
    END
  END kv_we[4]
  PIN kv_we[5]
    DIRECTION INPUT ;
    USE SIGNAL ;
    PORT
      LAYER M4 ;
        RECT  0 53.328 0.084 53.352 ;
    END
  END kv_we[5]
  PIN kv_we[6]
    DIRECTION INPUT ;
    USE SIGNAL ;
    PORT
      LAYER M4 ;
        RECT  0 53.424 0.084 53.448 ;
    END
  END kv_we[6]
  PIN kv_we[7]
    DIRECTION INPUT ;
    USE SIGNAL ;
    PORT
      LAYER M4 ;
        RECT  0 53.52 0.084 53.544 ;
    END
  END kv_we[7]
  PIN l_fault[0]
    DIRECTION INPUT ;
    USE SIGNAL ;
    PORT
      LAYER M4 ;
        RECT  0 53.616 0.084 53.64 ;
    END
  END l_fault[0]
  PIN l_fault[1]
    DIRECTION INPUT ;
    USE SIGNAL ;
    PORT
      LAYER M4 ;
        RECT  0 53.712 0.084 53.736 ;
    END
  END l_fault[1]
  PIN l_fault[2]
    DIRECTION INPUT ;
    USE SIGNAL ;
    PORT
      LAYER M4 ;
        RECT  0 53.808 0.084 53.832 ;
    END
  END l_fault[2]
  PIN l_fault[3]
    DIRECTION INPUT ;
    USE SIGNAL ;
    PORT
      LAYER M4 ;
        RECT  0 53.904 0.084 53.928 ;
    END
  END l_fault[3]
  PIN l_fault[4]
    DIRECTION INPUT ;
    USE SIGNAL ;
    PORT
      LAYER M4 ;
        RECT  0 54 0.084 54.024 ;
    END
  END l_fault[4]
  PIN l_fault[5]
    DIRECTION INPUT ;
    USE SIGNAL ;
    PORT
      LAYER M4 ;
        RECT  0 54.096 0.084 54.12 ;
    END
  END l_fault[5]
  PIN l_fault[6]
    DIRECTION INPUT ;
    USE SIGNAL ;
    PORT
      LAYER M4 ;
        RECT  0 54.192 0.084 54.216 ;
    END
  END l_fault[6]
  PIN l_fault[7]
    DIRECTION INPUT ;
    USE SIGNAL ;
    PORT
      LAYER M4 ;
        RECT  0 54.288 0.084 54.312 ;
    END
  END l_fault[7]
  PIN l_last
    DIRECTION INPUT ;
    USE SIGNAL ;
    PORT
      LAYER M4 ;
        RECT  0 54.384 0.084 54.408 ;
    END
  END l_last
  PIN l_retire
    DIRECTION INPUT ;
    USE SIGNAL ;
    PORT
      LAYER M4 ;
        RECT  0 54.48 0.084 54.504 ;
    END
  END l_retire
  PIN lv1[0]
    DIRECTION OUTPUT ;
    USE SIGNAL ;
    PORT
      LAYER M5 ;
        RECT  45.36 0 45.384 0.084 ;
    END
  END lv1[0]
  PIN lv1[1]
    DIRECTION OUTPUT ;
    USE SIGNAL ;
    PORT
      LAYER M5 ;
        RECT  45.456 0 45.48 0.084 ;
    END
  END lv1[1]
  PIN lv1[2]
    DIRECTION OUTPUT ;
    USE SIGNAL ;
    PORT
      LAYER M5 ;
        RECT  45.552 0 45.576 0.084 ;
    END
  END lv1[2]
  PIN lv1[3]
    DIRECTION OUTPUT ;
    USE SIGNAL ;
    PORT
      LAYER M5 ;
        RECT  45.648 0 45.672 0.084 ;
    END
  END lv1[3]
  PIN lv1[4]
    DIRECTION OUTPUT ;
    USE SIGNAL ;
    PORT
      LAYER M5 ;
        RECT  45.744 0 45.768 0.084 ;
    END
  END lv1[4]
  PIN lv1[5]
    DIRECTION OUTPUT ;
    USE SIGNAL ;
    PORT
      LAYER M5 ;
        RECT  45.84 0 45.864 0.084 ;
    END
  END lv1[5]
  PIN lv1[6]
    DIRECTION OUTPUT ;
    USE SIGNAL ;
    PORT
      LAYER M5 ;
        RECT  45.936 0 45.96 0.084 ;
    END
  END lv1[6]
  PIN lv1[7]
    DIRECTION OUTPUT ;
    USE SIGNAL ;
    PORT
      LAYER M5 ;
        RECT  46.032 0 46.056 0.084 ;
    END
  END lv1[7]
  PIN lvm_we[0]
    DIRECTION INPUT ;
    USE SIGNAL ;
    PORT
      LAYER M4 ;
        RECT  0 54.576 0.084 54.6 ;
    END
  END lvm_we[0]
  PIN lvm_we[1]
    DIRECTION INPUT ;
    USE SIGNAL ;
    PORT
      LAYER M4 ;
        RECT  0 54.672 0.084 54.696 ;
    END
  END lvm_we[1]
  PIN lvm_we[2]
    DIRECTION INPUT ;
    USE SIGNAL ;
    PORT
      LAYER M4 ;
        RECT  0 54.768 0.084 54.792 ;
    END
  END lvm_we[2]
  PIN lvm_we[3]
    DIRECTION INPUT ;
    USE SIGNAL ;
    PORT
      LAYER M4 ;
        RECT  0 54.864 0.084 54.888 ;
    END
  END lvm_we[3]
  PIN lvm_we[4]
    DIRECTION INPUT ;
    USE SIGNAL ;
    PORT
      LAYER M4 ;
        RECT  0 54.96 0.084 54.984 ;
    END
  END lvm_we[4]
  PIN lvm_we[5]
    DIRECTION INPUT ;
    USE SIGNAL ;
    PORT
      LAYER M4 ;
        RECT  0 55.056 0.084 55.08 ;
    END
  END lvm_we[5]
  PIN lvm_we[6]
    DIRECTION INPUT ;
    USE SIGNAL ;
    PORT
      LAYER M4 ;
        RECT  0 55.152 0.084 55.176 ;
    END
  END lvm_we[6]
  PIN lvm_we[7]
    DIRECTION INPUT ;
    USE SIGNAL ;
    PORT
      LAYER M4 ;
        RECT  0 55.248 0.084 55.272 ;
    END
  END lvm_we[7]
  PIN pd1[0]
    DIRECTION OUTPUT ;
    USE SIGNAL ;
    PORT
      LAYER M5 ;
        RECT  159.792 129.516 159.816 129.6 ;
    END
  END pd1[0]
  PIN pd1[100]
    DIRECTION OUTPUT ;
    USE SIGNAL ;
    PORT
      LAYER M5 ;
        RECT  163.248 129.516 163.272 129.6 ;
    END
  END pd1[100]
  PIN pd1[101]
    DIRECTION OUTPUT ;
    USE SIGNAL ;
    PORT
      LAYER M5 ;
        RECT  163.344 129.516 163.368 129.6 ;
    END
  END pd1[101]
  PIN pd1[102]
    DIRECTION OUTPUT ;
    USE SIGNAL ;
    PORT
      LAYER M5 ;
        RECT  163.44 129.516 163.464 129.6 ;
    END
  END pd1[102]
  PIN pd1[103]
    DIRECTION OUTPUT ;
    USE SIGNAL ;
    PORT
      LAYER M5 ;
        RECT  163.536 129.516 163.56 129.6 ;
    END
  END pd1[103]
  PIN pd1[104]
    DIRECTION OUTPUT ;
    USE SIGNAL ;
    PORT
      LAYER M5 ;
        RECT  163.632 129.516 163.656 129.6 ;
    END
  END pd1[104]
  PIN pd1[105]
    DIRECTION OUTPUT ;
    USE SIGNAL ;
    PORT
      LAYER M5 ;
        RECT  163.728 129.516 163.752 129.6 ;
    END
  END pd1[105]
  PIN pd1[106]
    DIRECTION OUTPUT ;
    USE SIGNAL ;
    PORT
      LAYER M5 ;
        RECT  163.824 129.516 163.848 129.6 ;
    END
  END pd1[106]
  PIN pd1[107]
    DIRECTION OUTPUT ;
    USE SIGNAL ;
    PORT
      LAYER M5 ;
        RECT  163.92 129.516 163.944 129.6 ;
    END
  END pd1[107]
  PIN pd1[108]
    DIRECTION OUTPUT ;
    USE SIGNAL ;
    PORT
      LAYER M5 ;
        RECT  164.016 129.516 164.04 129.6 ;
    END
  END pd1[108]
  PIN pd1[109]
    DIRECTION OUTPUT ;
    USE SIGNAL ;
    PORT
      LAYER M5 ;
        RECT  164.112 129.516 164.136 129.6 ;
    END
  END pd1[109]
  PIN pd1[10]
    DIRECTION OUTPUT ;
    USE SIGNAL ;
    PORT
      LAYER M5 ;
        RECT  160.752 129.516 160.776 129.6 ;
    END
  END pd1[10]
  PIN pd1[110]
    DIRECTION OUTPUT ;
    USE SIGNAL ;
    PORT
      LAYER M5 ;
        RECT  164.208 129.516 164.232 129.6 ;
    END
  END pd1[110]
  PIN pd1[111]
    DIRECTION OUTPUT ;
    USE SIGNAL ;
    PORT
      LAYER M5 ;
        RECT  164.304 129.516 164.328 129.6 ;
    END
  END pd1[111]
  PIN pd1[112]
    DIRECTION OUTPUT ;
    USE SIGNAL ;
    PORT
      LAYER M5 ;
        RECT  164.4 129.516 164.424 129.6 ;
    END
  END pd1[112]
  PIN pd1[113]
    DIRECTION OUTPUT ;
    USE SIGNAL ;
    PORT
      LAYER M5 ;
        RECT  164.496 129.516 164.52 129.6 ;
    END
  END pd1[113]
  PIN pd1[114]
    DIRECTION OUTPUT ;
    USE SIGNAL ;
    PORT
      LAYER M5 ;
        RECT  164.592 129.516 164.616 129.6 ;
    END
  END pd1[114]
  PIN pd1[115]
    DIRECTION OUTPUT ;
    USE SIGNAL ;
    PORT
      LAYER M5 ;
        RECT  164.688 129.516 164.712 129.6 ;
    END
  END pd1[115]
  PIN pd1[116]
    DIRECTION OUTPUT ;
    USE SIGNAL ;
    PORT
      LAYER M5 ;
        RECT  164.784 129.516 164.808 129.6 ;
    END
  END pd1[116]
  PIN pd1[117]
    DIRECTION OUTPUT ;
    USE SIGNAL ;
    PORT
      LAYER M5 ;
        RECT  164.88 129.516 164.904 129.6 ;
    END
  END pd1[117]
  PIN pd1[118]
    DIRECTION OUTPUT ;
    USE SIGNAL ;
    PORT
      LAYER M5 ;
        RECT  164.976 129.516 165 129.6 ;
    END
  END pd1[118]
  PIN pd1[119]
    DIRECTION OUTPUT ;
    USE SIGNAL ;
    PORT
      LAYER M5 ;
        RECT  165.072 129.516 165.096 129.6 ;
    END
  END pd1[119]
  PIN pd1[11]
    DIRECTION OUTPUT ;
    USE SIGNAL ;
    PORT
      LAYER M5 ;
        RECT  160.848 129.516 160.872 129.6 ;
    END
  END pd1[11]
  PIN pd1[120]
    DIRECTION OUTPUT ;
    USE SIGNAL ;
    PORT
      LAYER M5 ;
        RECT  165.168 129.516 165.192 129.6 ;
    END
  END pd1[120]
  PIN pd1[121]
    DIRECTION OUTPUT ;
    USE SIGNAL ;
    PORT
      LAYER M5 ;
        RECT  165.264 129.516 165.288 129.6 ;
    END
  END pd1[121]
  PIN pd1[122]
    DIRECTION OUTPUT ;
    USE SIGNAL ;
    PORT
      LAYER M5 ;
        RECT  165.36 129.516 165.384 129.6 ;
    END
  END pd1[122]
  PIN pd1[123]
    DIRECTION OUTPUT ;
    USE SIGNAL ;
    PORT
      LAYER M5 ;
        RECT  165.456 129.516 165.48 129.6 ;
    END
  END pd1[123]
  PIN pd1[124]
    DIRECTION OUTPUT ;
    USE SIGNAL ;
    PORT
      LAYER M5 ;
        RECT  165.552 129.516 165.576 129.6 ;
    END
  END pd1[124]
  PIN pd1[125]
    DIRECTION OUTPUT ;
    USE SIGNAL ;
    PORT
      LAYER M5 ;
        RECT  165.648 129.516 165.672 129.6 ;
    END
  END pd1[125]
  PIN pd1[126]
    DIRECTION OUTPUT ;
    USE SIGNAL ;
    PORT
      LAYER M5 ;
        RECT  165.744 129.516 165.768 129.6 ;
    END
  END pd1[126]
  PIN pd1[127]
    DIRECTION OUTPUT ;
    USE SIGNAL ;
    PORT
      LAYER M5 ;
        RECT  165.84 129.516 165.864 129.6 ;
    END
  END pd1[127]
  PIN pd1[128]
    DIRECTION OUTPUT ;
    USE SIGNAL ;
    PORT
      LAYER M5 ;
        RECT  79.92 129.516 79.944 129.6 ;
    END
  END pd1[128]
  PIN pd1[129]
    DIRECTION OUTPUT ;
    USE SIGNAL ;
    PORT
      LAYER M5 ;
        RECT  80.016 129.516 80.04 129.6 ;
    END
  END pd1[129]
  PIN pd1[12]
    DIRECTION OUTPUT ;
    USE SIGNAL ;
    PORT
      LAYER M5 ;
        RECT  160.944 129.516 160.968 129.6 ;
    END
  END pd1[12]
  PIN pd1[130]
    DIRECTION OUTPUT ;
    USE SIGNAL ;
    PORT
      LAYER M5 ;
        RECT  80.112 129.516 80.136 129.6 ;
    END
  END pd1[130]
  PIN pd1[131]
    DIRECTION OUTPUT ;
    USE SIGNAL ;
    PORT
      LAYER M5 ;
        RECT  80.208 129.516 80.232 129.6 ;
    END
  END pd1[131]
  PIN pd1[132]
    DIRECTION OUTPUT ;
    USE SIGNAL ;
    PORT
      LAYER M5 ;
        RECT  80.304 129.516 80.328 129.6 ;
    END
  END pd1[132]
  PIN pd1[133]
    DIRECTION OUTPUT ;
    USE SIGNAL ;
    PORT
      LAYER M5 ;
        RECT  80.4 129.516 80.424 129.6 ;
    END
  END pd1[133]
  PIN pd1[134]
    DIRECTION OUTPUT ;
    USE SIGNAL ;
    PORT
      LAYER M5 ;
        RECT  80.496 129.516 80.52 129.6 ;
    END
  END pd1[134]
  PIN pd1[135]
    DIRECTION OUTPUT ;
    USE SIGNAL ;
    PORT
      LAYER M5 ;
        RECT  80.592 129.516 80.616 129.6 ;
    END
  END pd1[135]
  PIN pd1[136]
    DIRECTION OUTPUT ;
    USE SIGNAL ;
    PORT
      LAYER M5 ;
        RECT  80.688 129.516 80.712 129.6 ;
    END
  END pd1[136]
  PIN pd1[137]
    DIRECTION OUTPUT ;
    USE SIGNAL ;
    PORT
      LAYER M5 ;
        RECT  80.784 129.516 80.808 129.6 ;
    END
  END pd1[137]
  PIN pd1[138]
    DIRECTION OUTPUT ;
    USE SIGNAL ;
    PORT
      LAYER M5 ;
        RECT  80.88 129.516 80.904 129.6 ;
    END
  END pd1[138]
  PIN pd1[139]
    DIRECTION OUTPUT ;
    USE SIGNAL ;
    PORT
      LAYER M5 ;
        RECT  80.976 129.516 81 129.6 ;
    END
  END pd1[139]
  PIN pd1[13]
    DIRECTION OUTPUT ;
    USE SIGNAL ;
    PORT
      LAYER M5 ;
        RECT  161.04 129.516 161.064 129.6 ;
    END
  END pd1[13]
  PIN pd1[140]
    DIRECTION OUTPUT ;
    USE SIGNAL ;
    PORT
      LAYER M5 ;
        RECT  81.072 129.516 81.096 129.6 ;
    END
  END pd1[140]
  PIN pd1[141]
    DIRECTION OUTPUT ;
    USE SIGNAL ;
    PORT
      LAYER M5 ;
        RECT  81.168 129.516 81.192 129.6 ;
    END
  END pd1[141]
  PIN pd1[142]
    DIRECTION OUTPUT ;
    USE SIGNAL ;
    PORT
      LAYER M5 ;
        RECT  81.264 129.516 81.288 129.6 ;
    END
  END pd1[142]
  PIN pd1[143]
    DIRECTION OUTPUT ;
    USE SIGNAL ;
    PORT
      LAYER M5 ;
        RECT  81.36 129.516 81.384 129.6 ;
    END
  END pd1[143]
  PIN pd1[144]
    DIRECTION OUTPUT ;
    USE SIGNAL ;
    PORT
      LAYER M5 ;
        RECT  81.456 129.516 81.48 129.6 ;
    END
  END pd1[144]
  PIN pd1[145]
    DIRECTION OUTPUT ;
    USE SIGNAL ;
    PORT
      LAYER M5 ;
        RECT  81.552 129.516 81.576 129.6 ;
    END
  END pd1[145]
  PIN pd1[146]
    DIRECTION OUTPUT ;
    USE SIGNAL ;
    PORT
      LAYER M5 ;
        RECT  81.648 129.516 81.672 129.6 ;
    END
  END pd1[146]
  PIN pd1[147]
    DIRECTION OUTPUT ;
    USE SIGNAL ;
    PORT
      LAYER M5 ;
        RECT  81.744 129.516 81.768 129.6 ;
    END
  END pd1[147]
  PIN pd1[148]
    DIRECTION OUTPUT ;
    USE SIGNAL ;
    PORT
      LAYER M5 ;
        RECT  81.84 129.516 81.864 129.6 ;
    END
  END pd1[148]
  PIN pd1[149]
    DIRECTION OUTPUT ;
    USE SIGNAL ;
    PORT
      LAYER M5 ;
        RECT  81.936 129.516 81.96 129.6 ;
    END
  END pd1[149]
  PIN pd1[14]
    DIRECTION OUTPUT ;
    USE SIGNAL ;
    PORT
      LAYER M5 ;
        RECT  161.136 129.516 161.16 129.6 ;
    END
  END pd1[14]
  PIN pd1[150]
    DIRECTION OUTPUT ;
    USE SIGNAL ;
    PORT
      LAYER M5 ;
        RECT  82.032 129.516 82.056 129.6 ;
    END
  END pd1[150]
  PIN pd1[151]
    DIRECTION OUTPUT ;
    USE SIGNAL ;
    PORT
      LAYER M5 ;
        RECT  82.128 129.516 82.152 129.6 ;
    END
  END pd1[151]
  PIN pd1[152]
    DIRECTION OUTPUT ;
    USE SIGNAL ;
    PORT
      LAYER M5 ;
        RECT  82.224 129.516 82.248 129.6 ;
    END
  END pd1[152]
  PIN pd1[153]
    DIRECTION OUTPUT ;
    USE SIGNAL ;
    PORT
      LAYER M5 ;
        RECT  82.32 129.516 82.344 129.6 ;
    END
  END pd1[153]
  PIN pd1[154]
    DIRECTION OUTPUT ;
    USE SIGNAL ;
    PORT
      LAYER M5 ;
        RECT  82.416 129.516 82.44 129.6 ;
    END
  END pd1[154]
  PIN pd1[155]
    DIRECTION OUTPUT ;
    USE SIGNAL ;
    PORT
      LAYER M5 ;
        RECT  82.512 129.516 82.536 129.6 ;
    END
  END pd1[155]
  PIN pd1[156]
    DIRECTION OUTPUT ;
    USE SIGNAL ;
    PORT
      LAYER M5 ;
        RECT  82.608 129.516 82.632 129.6 ;
    END
  END pd1[156]
  PIN pd1[157]
    DIRECTION OUTPUT ;
    USE SIGNAL ;
    PORT
      LAYER M5 ;
        RECT  82.704 129.516 82.728 129.6 ;
    END
  END pd1[157]
  PIN pd1[158]
    DIRECTION OUTPUT ;
    USE SIGNAL ;
    PORT
      LAYER M5 ;
        RECT  82.8 129.516 82.824 129.6 ;
    END
  END pd1[158]
  PIN pd1[159]
    DIRECTION OUTPUT ;
    USE SIGNAL ;
    PORT
      LAYER M5 ;
        RECT  82.896 129.516 82.92 129.6 ;
    END
  END pd1[159]
  PIN pd1[15]
    DIRECTION OUTPUT ;
    USE SIGNAL ;
    PORT
      LAYER M5 ;
        RECT  161.232 129.516 161.256 129.6 ;
    END
  END pd1[15]
  PIN pd1[160]
    DIRECTION OUTPUT ;
    USE SIGNAL ;
    PORT
      LAYER M5 ;
        RECT  92.208 129.516 92.232 129.6 ;
    END
  END pd1[160]
  PIN pd1[161]
    DIRECTION OUTPUT ;
    USE SIGNAL ;
    PORT
      LAYER M5 ;
        RECT  92.304 129.516 92.328 129.6 ;
    END
  END pd1[161]
  PIN pd1[162]
    DIRECTION OUTPUT ;
    USE SIGNAL ;
    PORT
      LAYER M5 ;
        RECT  92.4 129.516 92.424 129.6 ;
    END
  END pd1[162]
  PIN pd1[163]
    DIRECTION OUTPUT ;
    USE SIGNAL ;
    PORT
      LAYER M5 ;
        RECT  92.496 129.516 92.52 129.6 ;
    END
  END pd1[163]
  PIN pd1[164]
    DIRECTION OUTPUT ;
    USE SIGNAL ;
    PORT
      LAYER M5 ;
        RECT  92.592 129.516 92.616 129.6 ;
    END
  END pd1[164]
  PIN pd1[165]
    DIRECTION OUTPUT ;
    USE SIGNAL ;
    PORT
      LAYER M5 ;
        RECT  92.688 129.516 92.712 129.6 ;
    END
  END pd1[165]
  PIN pd1[166]
    DIRECTION OUTPUT ;
    USE SIGNAL ;
    PORT
      LAYER M5 ;
        RECT  92.784 129.516 92.808 129.6 ;
    END
  END pd1[166]
  PIN pd1[167]
    DIRECTION OUTPUT ;
    USE SIGNAL ;
    PORT
      LAYER M5 ;
        RECT  92.88 129.516 92.904 129.6 ;
    END
  END pd1[167]
  PIN pd1[168]
    DIRECTION OUTPUT ;
    USE SIGNAL ;
    PORT
      LAYER M5 ;
        RECT  92.976 129.516 93 129.6 ;
    END
  END pd1[168]
  PIN pd1[169]
    DIRECTION OUTPUT ;
    USE SIGNAL ;
    PORT
      LAYER M5 ;
        RECT  93.072 129.516 93.096 129.6 ;
    END
  END pd1[169]
  PIN pd1[16]
    DIRECTION OUTPUT ;
    USE SIGNAL ;
    PORT
      LAYER M5 ;
        RECT  161.328 129.516 161.352 129.6 ;
    END
  END pd1[16]
  PIN pd1[170]
    DIRECTION OUTPUT ;
    USE SIGNAL ;
    PORT
      LAYER M5 ;
        RECT  93.168 129.516 93.192 129.6 ;
    END
  END pd1[170]
  PIN pd1[171]
    DIRECTION OUTPUT ;
    USE SIGNAL ;
    PORT
      LAYER M5 ;
        RECT  93.264 129.516 93.288 129.6 ;
    END
  END pd1[171]
  PIN pd1[172]
    DIRECTION OUTPUT ;
    USE SIGNAL ;
    PORT
      LAYER M5 ;
        RECT  93.36 129.516 93.384 129.6 ;
    END
  END pd1[172]
  PIN pd1[173]
    DIRECTION OUTPUT ;
    USE SIGNAL ;
    PORT
      LAYER M5 ;
        RECT  93.456 129.516 93.48 129.6 ;
    END
  END pd1[173]
  PIN pd1[174]
    DIRECTION OUTPUT ;
    USE SIGNAL ;
    PORT
      LAYER M5 ;
        RECT  93.552 129.516 93.576 129.6 ;
    END
  END pd1[174]
  PIN pd1[175]
    DIRECTION OUTPUT ;
    USE SIGNAL ;
    PORT
      LAYER M5 ;
        RECT  93.648 129.516 93.672 129.6 ;
    END
  END pd1[175]
  PIN pd1[176]
    DIRECTION OUTPUT ;
    USE SIGNAL ;
    PORT
      LAYER M5 ;
        RECT  93.744 129.516 93.768 129.6 ;
    END
  END pd1[176]
  PIN pd1[177]
    DIRECTION OUTPUT ;
    USE SIGNAL ;
    PORT
      LAYER M5 ;
        RECT  93.84 129.516 93.864 129.6 ;
    END
  END pd1[177]
  PIN pd1[178]
    DIRECTION OUTPUT ;
    USE SIGNAL ;
    PORT
      LAYER M5 ;
        RECT  93.936 129.516 93.96 129.6 ;
    END
  END pd1[178]
  PIN pd1[179]
    DIRECTION OUTPUT ;
    USE SIGNAL ;
    PORT
      LAYER M5 ;
        RECT  94.032 129.516 94.056 129.6 ;
    END
  END pd1[179]
  PIN pd1[17]
    DIRECTION OUTPUT ;
    USE SIGNAL ;
    PORT
      LAYER M5 ;
        RECT  161.424 129.516 161.448 129.6 ;
    END
  END pd1[17]
  PIN pd1[180]
    DIRECTION OUTPUT ;
    USE SIGNAL ;
    PORT
      LAYER M5 ;
        RECT  94.128 129.516 94.152 129.6 ;
    END
  END pd1[180]
  PIN pd1[181]
    DIRECTION OUTPUT ;
    USE SIGNAL ;
    PORT
      LAYER M5 ;
        RECT  94.224 129.516 94.248 129.6 ;
    END
  END pd1[181]
  PIN pd1[182]
    DIRECTION OUTPUT ;
    USE SIGNAL ;
    PORT
      LAYER M5 ;
        RECT  94.32 129.516 94.344 129.6 ;
    END
  END pd1[182]
  PIN pd1[183]
    DIRECTION OUTPUT ;
    USE SIGNAL ;
    PORT
      LAYER M5 ;
        RECT  94.416 129.516 94.44 129.6 ;
    END
  END pd1[183]
  PIN pd1[184]
    DIRECTION OUTPUT ;
    USE SIGNAL ;
    PORT
      LAYER M5 ;
        RECT  94.512 129.516 94.536 129.6 ;
    END
  END pd1[184]
  PIN pd1[185]
    DIRECTION OUTPUT ;
    USE SIGNAL ;
    PORT
      LAYER M5 ;
        RECT  94.608 129.516 94.632 129.6 ;
    END
  END pd1[185]
  PIN pd1[186]
    DIRECTION OUTPUT ;
    USE SIGNAL ;
    PORT
      LAYER M5 ;
        RECT  94.704 129.516 94.728 129.6 ;
    END
  END pd1[186]
  PIN pd1[187]
    DIRECTION OUTPUT ;
    USE SIGNAL ;
    PORT
      LAYER M5 ;
        RECT  94.8 129.516 94.824 129.6 ;
    END
  END pd1[187]
  PIN pd1[188]
    DIRECTION OUTPUT ;
    USE SIGNAL ;
    PORT
      LAYER M5 ;
        RECT  94.896 129.516 94.92 129.6 ;
    END
  END pd1[188]
  PIN pd1[189]
    DIRECTION OUTPUT ;
    USE SIGNAL ;
    PORT
      LAYER M5 ;
        RECT  94.992 129.516 95.016 129.6 ;
    END
  END pd1[189]
  PIN pd1[18]
    DIRECTION OUTPUT ;
    USE SIGNAL ;
    PORT
      LAYER M5 ;
        RECT  161.52 129.516 161.544 129.6 ;
    END
  END pd1[18]
  PIN pd1[190]
    DIRECTION OUTPUT ;
    USE SIGNAL ;
    PORT
      LAYER M5 ;
        RECT  95.088 129.516 95.112 129.6 ;
    END
  END pd1[190]
  PIN pd1[191]
    DIRECTION OUTPUT ;
    USE SIGNAL ;
    PORT
      LAYER M5 ;
        RECT  95.184 129.516 95.208 129.6 ;
    END
  END pd1[191]
  PIN pd1[192]
    DIRECTION OUTPUT ;
    USE SIGNAL ;
    PORT
      LAYER M5 ;
        RECT  143.664 129.516 143.688 129.6 ;
    END
  END pd1[192]
  PIN pd1[193]
    DIRECTION OUTPUT ;
    USE SIGNAL ;
    PORT
      LAYER M5 ;
        RECT  143.76 129.516 143.784 129.6 ;
    END
  END pd1[193]
  PIN pd1[194]
    DIRECTION OUTPUT ;
    USE SIGNAL ;
    PORT
      LAYER M5 ;
        RECT  143.856 129.516 143.88 129.6 ;
    END
  END pd1[194]
  PIN pd1[195]
    DIRECTION OUTPUT ;
    USE SIGNAL ;
    PORT
      LAYER M5 ;
        RECT  143.952 129.516 143.976 129.6 ;
    END
  END pd1[195]
  PIN pd1[196]
    DIRECTION OUTPUT ;
    USE SIGNAL ;
    PORT
      LAYER M5 ;
        RECT  144.048 129.516 144.072 129.6 ;
    END
  END pd1[196]
  PIN pd1[197]
    DIRECTION OUTPUT ;
    USE SIGNAL ;
    PORT
      LAYER M5 ;
        RECT  144.144 129.516 144.168 129.6 ;
    END
  END pd1[197]
  PIN pd1[198]
    DIRECTION OUTPUT ;
    USE SIGNAL ;
    PORT
      LAYER M5 ;
        RECT  144.24 129.516 144.264 129.6 ;
    END
  END pd1[198]
  PIN pd1[199]
    DIRECTION OUTPUT ;
    USE SIGNAL ;
    PORT
      LAYER M5 ;
        RECT  144.336 129.516 144.36 129.6 ;
    END
  END pd1[199]
  PIN pd1[19]
    DIRECTION OUTPUT ;
    USE SIGNAL ;
    PORT
      LAYER M5 ;
        RECT  161.616 129.516 161.64 129.6 ;
    END
  END pd1[19]
  PIN pd1[1]
    DIRECTION OUTPUT ;
    USE SIGNAL ;
    PORT
      LAYER M5 ;
        RECT  159.888 129.516 159.912 129.6 ;
    END
  END pd1[1]
  PIN pd1[200]
    DIRECTION OUTPUT ;
    USE SIGNAL ;
    PORT
      LAYER M5 ;
        RECT  144.432 129.516 144.456 129.6 ;
    END
  END pd1[200]
  PIN pd1[201]
    DIRECTION OUTPUT ;
    USE SIGNAL ;
    PORT
      LAYER M5 ;
        RECT  144.528 129.516 144.552 129.6 ;
    END
  END pd1[201]
  PIN pd1[202]
    DIRECTION OUTPUT ;
    USE SIGNAL ;
    PORT
      LAYER M5 ;
        RECT  144.624 129.516 144.648 129.6 ;
    END
  END pd1[202]
  PIN pd1[203]
    DIRECTION OUTPUT ;
    USE SIGNAL ;
    PORT
      LAYER M5 ;
        RECT  144.72 129.516 144.744 129.6 ;
    END
  END pd1[203]
  PIN pd1[204]
    DIRECTION OUTPUT ;
    USE SIGNAL ;
    PORT
      LAYER M5 ;
        RECT  144.816 129.516 144.84 129.6 ;
    END
  END pd1[204]
  PIN pd1[205]
    DIRECTION OUTPUT ;
    USE SIGNAL ;
    PORT
      LAYER M5 ;
        RECT  144.912 129.516 144.936 129.6 ;
    END
  END pd1[205]
  PIN pd1[206]
    DIRECTION OUTPUT ;
    USE SIGNAL ;
    PORT
      LAYER M5 ;
        RECT  145.008 129.516 145.032 129.6 ;
    END
  END pd1[206]
  PIN pd1[207]
    DIRECTION OUTPUT ;
    USE SIGNAL ;
    PORT
      LAYER M5 ;
        RECT  145.104 129.516 145.128 129.6 ;
    END
  END pd1[207]
  PIN pd1[208]
    DIRECTION OUTPUT ;
    USE SIGNAL ;
    PORT
      LAYER M5 ;
        RECT  145.2 129.516 145.224 129.6 ;
    END
  END pd1[208]
  PIN pd1[209]
    DIRECTION OUTPUT ;
    USE SIGNAL ;
    PORT
      LAYER M5 ;
        RECT  145.296 129.516 145.32 129.6 ;
    END
  END pd1[209]
  PIN pd1[20]
    DIRECTION OUTPUT ;
    USE SIGNAL ;
    PORT
      LAYER M5 ;
        RECT  161.712 129.516 161.736 129.6 ;
    END
  END pd1[20]
  PIN pd1[210]
    DIRECTION OUTPUT ;
    USE SIGNAL ;
    PORT
      LAYER M5 ;
        RECT  145.392 129.516 145.416 129.6 ;
    END
  END pd1[210]
  PIN pd1[211]
    DIRECTION OUTPUT ;
    USE SIGNAL ;
    PORT
      LAYER M5 ;
        RECT  145.488 129.516 145.512 129.6 ;
    END
  END pd1[211]
  PIN pd1[212]
    DIRECTION OUTPUT ;
    USE SIGNAL ;
    PORT
      LAYER M5 ;
        RECT  145.584 129.516 145.608 129.6 ;
    END
  END pd1[212]
  PIN pd1[213]
    DIRECTION OUTPUT ;
    USE SIGNAL ;
    PORT
      LAYER M5 ;
        RECT  145.68 129.516 145.704 129.6 ;
    END
  END pd1[213]
  PIN pd1[214]
    DIRECTION OUTPUT ;
    USE SIGNAL ;
    PORT
      LAYER M5 ;
        RECT  145.776 129.516 145.8 129.6 ;
    END
  END pd1[214]
  PIN pd1[215]
    DIRECTION OUTPUT ;
    USE SIGNAL ;
    PORT
      LAYER M5 ;
        RECT  145.872 129.516 145.896 129.6 ;
    END
  END pd1[215]
  PIN pd1[216]
    DIRECTION OUTPUT ;
    USE SIGNAL ;
    PORT
      LAYER M5 ;
        RECT  145.968 129.516 145.992 129.6 ;
    END
  END pd1[216]
  PIN pd1[217]
    DIRECTION OUTPUT ;
    USE SIGNAL ;
    PORT
      LAYER M5 ;
        RECT  146.064 129.516 146.088 129.6 ;
    END
  END pd1[217]
  PIN pd1[218]
    DIRECTION OUTPUT ;
    USE SIGNAL ;
    PORT
      LAYER M5 ;
        RECT  146.16 129.516 146.184 129.6 ;
    END
  END pd1[218]
  PIN pd1[219]
    DIRECTION OUTPUT ;
    USE SIGNAL ;
    PORT
      LAYER M5 ;
        RECT  146.256 129.516 146.28 129.6 ;
    END
  END pd1[219]
  PIN pd1[21]
    DIRECTION OUTPUT ;
    USE SIGNAL ;
    PORT
      LAYER M5 ;
        RECT  161.808 129.516 161.832 129.6 ;
    END
  END pd1[21]
  PIN pd1[220]
    DIRECTION OUTPUT ;
    USE SIGNAL ;
    PORT
      LAYER M5 ;
        RECT  146.352 129.516 146.376 129.6 ;
    END
  END pd1[220]
  PIN pd1[221]
    DIRECTION OUTPUT ;
    USE SIGNAL ;
    PORT
      LAYER M5 ;
        RECT  146.448 129.516 146.472 129.6 ;
    END
  END pd1[221]
  PIN pd1[222]
    DIRECTION OUTPUT ;
    USE SIGNAL ;
    PORT
      LAYER M5 ;
        RECT  146.544 129.516 146.568 129.6 ;
    END
  END pd1[222]
  PIN pd1[223]
    DIRECTION OUTPUT ;
    USE SIGNAL ;
    PORT
      LAYER M5 ;
        RECT  146.64 129.516 146.664 129.6 ;
    END
  END pd1[223]
  PIN pd1[224]
    DIRECTION OUTPUT ;
    USE SIGNAL ;
    PORT
      LAYER M5 ;
        RECT  66.864 129.516 66.888 129.6 ;
    END
  END pd1[224]
  PIN pd1[225]
    DIRECTION OUTPUT ;
    USE SIGNAL ;
    PORT
      LAYER M5 ;
        RECT  66.96 129.516 66.984 129.6 ;
    END
  END pd1[225]
  PIN pd1[226]
    DIRECTION OUTPUT ;
    USE SIGNAL ;
    PORT
      LAYER M5 ;
        RECT  67.056 129.516 67.08 129.6 ;
    END
  END pd1[226]
  PIN pd1[227]
    DIRECTION OUTPUT ;
    USE SIGNAL ;
    PORT
      LAYER M5 ;
        RECT  67.152 129.516 67.176 129.6 ;
    END
  END pd1[227]
  PIN pd1[228]
    DIRECTION OUTPUT ;
    USE SIGNAL ;
    PORT
      LAYER M5 ;
        RECT  67.248 129.516 67.272 129.6 ;
    END
  END pd1[228]
  PIN pd1[229]
    DIRECTION OUTPUT ;
    USE SIGNAL ;
    PORT
      LAYER M5 ;
        RECT  67.344 129.516 67.368 129.6 ;
    END
  END pd1[229]
  PIN pd1[22]
    DIRECTION OUTPUT ;
    USE SIGNAL ;
    PORT
      LAYER M5 ;
        RECT  161.904 129.516 161.928 129.6 ;
    END
  END pd1[22]
  PIN pd1[230]
    DIRECTION OUTPUT ;
    USE SIGNAL ;
    PORT
      LAYER M5 ;
        RECT  67.44 129.516 67.464 129.6 ;
    END
  END pd1[230]
  PIN pd1[231]
    DIRECTION OUTPUT ;
    USE SIGNAL ;
    PORT
      LAYER M5 ;
        RECT  67.536 129.516 67.56 129.6 ;
    END
  END pd1[231]
  PIN pd1[232]
    DIRECTION OUTPUT ;
    USE SIGNAL ;
    PORT
      LAYER M5 ;
        RECT  67.632 129.516 67.656 129.6 ;
    END
  END pd1[232]
  PIN pd1[233]
    DIRECTION OUTPUT ;
    USE SIGNAL ;
    PORT
      LAYER M5 ;
        RECT  67.728 129.516 67.752 129.6 ;
    END
  END pd1[233]
  PIN pd1[234]
    DIRECTION OUTPUT ;
    USE SIGNAL ;
    PORT
      LAYER M5 ;
        RECT  67.824 129.516 67.848 129.6 ;
    END
  END pd1[234]
  PIN pd1[235]
    DIRECTION OUTPUT ;
    USE SIGNAL ;
    PORT
      LAYER M5 ;
        RECT  67.92 129.516 67.944 129.6 ;
    END
  END pd1[235]
  PIN pd1[236]
    DIRECTION OUTPUT ;
    USE SIGNAL ;
    PORT
      LAYER M5 ;
        RECT  68.016 129.516 68.04 129.6 ;
    END
  END pd1[236]
  PIN pd1[237]
    DIRECTION OUTPUT ;
    USE SIGNAL ;
    PORT
      LAYER M5 ;
        RECT  68.112 129.516 68.136 129.6 ;
    END
  END pd1[237]
  PIN pd1[238]
    DIRECTION OUTPUT ;
    USE SIGNAL ;
    PORT
      LAYER M5 ;
        RECT  68.208 129.516 68.232 129.6 ;
    END
  END pd1[238]
  PIN pd1[239]
    DIRECTION OUTPUT ;
    USE SIGNAL ;
    PORT
      LAYER M5 ;
        RECT  68.304 129.516 68.328 129.6 ;
    END
  END pd1[239]
  PIN pd1[23]
    DIRECTION OUTPUT ;
    USE SIGNAL ;
    PORT
      LAYER M5 ;
        RECT  162 129.516 162.024 129.6 ;
    END
  END pd1[23]
  PIN pd1[240]
    DIRECTION OUTPUT ;
    USE SIGNAL ;
    PORT
      LAYER M5 ;
        RECT  68.4 129.516 68.424 129.6 ;
    END
  END pd1[240]
  PIN pd1[241]
    DIRECTION OUTPUT ;
    USE SIGNAL ;
    PORT
      LAYER M5 ;
        RECT  68.496 129.516 68.52 129.6 ;
    END
  END pd1[241]
  PIN pd1[242]
    DIRECTION OUTPUT ;
    USE SIGNAL ;
    PORT
      LAYER M5 ;
        RECT  68.592 129.516 68.616 129.6 ;
    END
  END pd1[242]
  PIN pd1[243]
    DIRECTION OUTPUT ;
    USE SIGNAL ;
    PORT
      LAYER M5 ;
        RECT  68.688 129.516 68.712 129.6 ;
    END
  END pd1[243]
  PIN pd1[244]
    DIRECTION OUTPUT ;
    USE SIGNAL ;
    PORT
      LAYER M5 ;
        RECT  68.784 129.516 68.808 129.6 ;
    END
  END pd1[244]
  PIN pd1[245]
    DIRECTION OUTPUT ;
    USE SIGNAL ;
    PORT
      LAYER M5 ;
        RECT  68.88 129.516 68.904 129.6 ;
    END
  END pd1[245]
  PIN pd1[246]
    DIRECTION OUTPUT ;
    USE SIGNAL ;
    PORT
      LAYER M5 ;
        RECT  68.976 129.516 69 129.6 ;
    END
  END pd1[246]
  PIN pd1[247]
    DIRECTION OUTPUT ;
    USE SIGNAL ;
    PORT
      LAYER M5 ;
        RECT  69.072 129.516 69.096 129.6 ;
    END
  END pd1[247]
  PIN pd1[248]
    DIRECTION OUTPUT ;
    USE SIGNAL ;
    PORT
      LAYER M5 ;
        RECT  69.168 129.516 69.192 129.6 ;
    END
  END pd1[248]
  PIN pd1[249]
    DIRECTION OUTPUT ;
    USE SIGNAL ;
    PORT
      LAYER M5 ;
        RECT  69.264 129.516 69.288 129.6 ;
    END
  END pd1[249]
  PIN pd1[24]
    DIRECTION OUTPUT ;
    USE SIGNAL ;
    PORT
      LAYER M5 ;
        RECT  162.096 129.516 162.12 129.6 ;
    END
  END pd1[24]
  PIN pd1[250]
    DIRECTION OUTPUT ;
    USE SIGNAL ;
    PORT
      LAYER M5 ;
        RECT  69.36 129.516 69.384 129.6 ;
    END
  END pd1[250]
  PIN pd1[251]
    DIRECTION OUTPUT ;
    USE SIGNAL ;
    PORT
      LAYER M5 ;
        RECT  69.456 129.516 69.48 129.6 ;
    END
  END pd1[251]
  PIN pd1[252]
    DIRECTION OUTPUT ;
    USE SIGNAL ;
    PORT
      LAYER M5 ;
        RECT  69.552 129.516 69.576 129.6 ;
    END
  END pd1[252]
  PIN pd1[253]
    DIRECTION OUTPUT ;
    USE SIGNAL ;
    PORT
      LAYER M5 ;
        RECT  69.648 129.516 69.672 129.6 ;
    END
  END pd1[253]
  PIN pd1[254]
    DIRECTION OUTPUT ;
    USE SIGNAL ;
    PORT
      LAYER M5 ;
        RECT  69.744 129.516 69.768 129.6 ;
    END
  END pd1[254]
  PIN pd1[255]
    DIRECTION OUTPUT ;
    USE SIGNAL ;
    PORT
      LAYER M5 ;
        RECT  69.84 129.516 69.864 129.6 ;
    END
  END pd1[255]
  PIN pd1[256]
    DIRECTION OUTPUT ;
    USE SIGNAL ;
    PORT
      LAYER M5 ;
        RECT  99.12 129.516 99.144 129.6 ;
    END
  END pd1[256]
  PIN pd1[257]
    DIRECTION OUTPUT ;
    USE SIGNAL ;
    PORT
      LAYER M5 ;
        RECT  99.216 129.516 99.24 129.6 ;
    END
  END pd1[257]
  PIN pd1[258]
    DIRECTION OUTPUT ;
    USE SIGNAL ;
    PORT
      LAYER M5 ;
        RECT  99.312 129.516 99.336 129.6 ;
    END
  END pd1[258]
  PIN pd1[259]
    DIRECTION OUTPUT ;
    USE SIGNAL ;
    PORT
      LAYER M5 ;
        RECT  99.408 129.516 99.432 129.6 ;
    END
  END pd1[259]
  PIN pd1[25]
    DIRECTION OUTPUT ;
    USE SIGNAL ;
    PORT
      LAYER M5 ;
        RECT  162.192 129.516 162.216 129.6 ;
    END
  END pd1[25]
  PIN pd1[260]
    DIRECTION OUTPUT ;
    USE SIGNAL ;
    PORT
      LAYER M5 ;
        RECT  99.504 129.516 99.528 129.6 ;
    END
  END pd1[260]
  PIN pd1[261]
    DIRECTION OUTPUT ;
    USE SIGNAL ;
    PORT
      LAYER M5 ;
        RECT  99.6 129.516 99.624 129.6 ;
    END
  END pd1[261]
  PIN pd1[262]
    DIRECTION OUTPUT ;
    USE SIGNAL ;
    PORT
      LAYER M5 ;
        RECT  99.696 129.516 99.72 129.6 ;
    END
  END pd1[262]
  PIN pd1[263]
    DIRECTION OUTPUT ;
    USE SIGNAL ;
    PORT
      LAYER M5 ;
        RECT  99.792 129.516 99.816 129.6 ;
    END
  END pd1[263]
  PIN pd1[264]
    DIRECTION OUTPUT ;
    USE SIGNAL ;
    PORT
      LAYER M5 ;
        RECT  99.888 129.516 99.912 129.6 ;
    END
  END pd1[264]
  PIN pd1[265]
    DIRECTION OUTPUT ;
    USE SIGNAL ;
    PORT
      LAYER M5 ;
        RECT  99.984 129.516 100.008 129.6 ;
    END
  END pd1[265]
  PIN pd1[266]
    DIRECTION OUTPUT ;
    USE SIGNAL ;
    PORT
      LAYER M5 ;
        RECT  100.08 129.516 100.104 129.6 ;
    END
  END pd1[266]
  PIN pd1[267]
    DIRECTION OUTPUT ;
    USE SIGNAL ;
    PORT
      LAYER M5 ;
        RECT  100.176 129.516 100.2 129.6 ;
    END
  END pd1[267]
  PIN pd1[268]
    DIRECTION OUTPUT ;
    USE SIGNAL ;
    PORT
      LAYER M5 ;
        RECT  100.272 129.516 100.296 129.6 ;
    END
  END pd1[268]
  PIN pd1[269]
    DIRECTION OUTPUT ;
    USE SIGNAL ;
    PORT
      LAYER M5 ;
        RECT  100.368 129.516 100.392 129.6 ;
    END
  END pd1[269]
  PIN pd1[26]
    DIRECTION OUTPUT ;
    USE SIGNAL ;
    PORT
      LAYER M5 ;
        RECT  162.288 129.516 162.312 129.6 ;
    END
  END pd1[26]
  PIN pd1[270]
    DIRECTION OUTPUT ;
    USE SIGNAL ;
    PORT
      LAYER M5 ;
        RECT  100.464 129.516 100.488 129.6 ;
    END
  END pd1[270]
  PIN pd1[271]
    DIRECTION OUTPUT ;
    USE SIGNAL ;
    PORT
      LAYER M5 ;
        RECT  100.56 129.516 100.584 129.6 ;
    END
  END pd1[271]
  PIN pd1[272]
    DIRECTION OUTPUT ;
    USE SIGNAL ;
    PORT
      LAYER M5 ;
        RECT  100.656 129.516 100.68 129.6 ;
    END
  END pd1[272]
  PIN pd1[273]
    DIRECTION OUTPUT ;
    USE SIGNAL ;
    PORT
      LAYER M5 ;
        RECT  100.752 129.516 100.776 129.6 ;
    END
  END pd1[273]
  PIN pd1[274]
    DIRECTION OUTPUT ;
    USE SIGNAL ;
    PORT
      LAYER M5 ;
        RECT  100.848 129.516 100.872 129.6 ;
    END
  END pd1[274]
  PIN pd1[275]
    DIRECTION OUTPUT ;
    USE SIGNAL ;
    PORT
      LAYER M5 ;
        RECT  100.944 129.516 100.968 129.6 ;
    END
  END pd1[275]
  PIN pd1[276]
    DIRECTION OUTPUT ;
    USE SIGNAL ;
    PORT
      LAYER M5 ;
        RECT  101.04 129.516 101.064 129.6 ;
    END
  END pd1[276]
  PIN pd1[277]
    DIRECTION OUTPUT ;
    USE SIGNAL ;
    PORT
      LAYER M5 ;
        RECT  101.136 129.516 101.16 129.6 ;
    END
  END pd1[277]
  PIN pd1[278]
    DIRECTION OUTPUT ;
    USE SIGNAL ;
    PORT
      LAYER M5 ;
        RECT  101.232 129.516 101.256 129.6 ;
    END
  END pd1[278]
  PIN pd1[279]
    DIRECTION OUTPUT ;
    USE SIGNAL ;
    PORT
      LAYER M5 ;
        RECT  101.328 129.516 101.352 129.6 ;
    END
  END pd1[279]
  PIN pd1[27]
    DIRECTION OUTPUT ;
    USE SIGNAL ;
    PORT
      LAYER M5 ;
        RECT  162.384 129.516 162.408 129.6 ;
    END
  END pd1[27]
  PIN pd1[280]
    DIRECTION OUTPUT ;
    USE SIGNAL ;
    PORT
      LAYER M5 ;
        RECT  101.424 129.516 101.448 129.6 ;
    END
  END pd1[280]
  PIN pd1[281]
    DIRECTION OUTPUT ;
    USE SIGNAL ;
    PORT
      LAYER M5 ;
        RECT  101.52 129.516 101.544 129.6 ;
    END
  END pd1[281]
  PIN pd1[282]
    DIRECTION OUTPUT ;
    USE SIGNAL ;
    PORT
      LAYER M5 ;
        RECT  101.616 129.516 101.64 129.6 ;
    END
  END pd1[282]
  PIN pd1[283]
    DIRECTION OUTPUT ;
    USE SIGNAL ;
    PORT
      LAYER M5 ;
        RECT  101.712 129.516 101.736 129.6 ;
    END
  END pd1[283]
  PIN pd1[284]
    DIRECTION OUTPUT ;
    USE SIGNAL ;
    PORT
      LAYER M5 ;
        RECT  101.808 129.516 101.832 129.6 ;
    END
  END pd1[284]
  PIN pd1[285]
    DIRECTION OUTPUT ;
    USE SIGNAL ;
    PORT
      LAYER M5 ;
        RECT  101.904 129.516 101.928 129.6 ;
    END
  END pd1[285]
  PIN pd1[286]
    DIRECTION OUTPUT ;
    USE SIGNAL ;
    PORT
      LAYER M5 ;
        RECT  102 129.516 102.024 129.6 ;
    END
  END pd1[286]
  PIN pd1[287]
    DIRECTION OUTPUT ;
    USE SIGNAL ;
    PORT
      LAYER M5 ;
        RECT  102.096 129.516 102.12 129.6 ;
    END
  END pd1[287]
  PIN pd1[288]
    DIRECTION OUTPUT ;
    USE SIGNAL ;
    PORT
      LAYER M5 ;
        RECT  134.448 129.516 134.472 129.6 ;
    END
  END pd1[288]
  PIN pd1[289]
    DIRECTION OUTPUT ;
    USE SIGNAL ;
    PORT
      LAYER M5 ;
        RECT  134.544 129.516 134.568 129.6 ;
    END
  END pd1[289]
  PIN pd1[28]
    DIRECTION OUTPUT ;
    USE SIGNAL ;
    PORT
      LAYER M5 ;
        RECT  162.48 129.516 162.504 129.6 ;
    END
  END pd1[28]
  PIN pd1[290]
    DIRECTION OUTPUT ;
    USE SIGNAL ;
    PORT
      LAYER M5 ;
        RECT  134.64 129.516 134.664 129.6 ;
    END
  END pd1[290]
  PIN pd1[291]
    DIRECTION OUTPUT ;
    USE SIGNAL ;
    PORT
      LAYER M5 ;
        RECT  134.736 129.516 134.76 129.6 ;
    END
  END pd1[291]
  PIN pd1[292]
    DIRECTION OUTPUT ;
    USE SIGNAL ;
    PORT
      LAYER M5 ;
        RECT  134.832 129.516 134.856 129.6 ;
    END
  END pd1[292]
  PIN pd1[293]
    DIRECTION OUTPUT ;
    USE SIGNAL ;
    PORT
      LAYER M5 ;
        RECT  134.928 129.516 134.952 129.6 ;
    END
  END pd1[293]
  PIN pd1[294]
    DIRECTION OUTPUT ;
    USE SIGNAL ;
    PORT
      LAYER M5 ;
        RECT  135.024 129.516 135.048 129.6 ;
    END
  END pd1[294]
  PIN pd1[295]
    DIRECTION OUTPUT ;
    USE SIGNAL ;
    PORT
      LAYER M5 ;
        RECT  135.12 129.516 135.144 129.6 ;
    END
  END pd1[295]
  PIN pd1[296]
    DIRECTION OUTPUT ;
    USE SIGNAL ;
    PORT
      LAYER M5 ;
        RECT  135.216 129.516 135.24 129.6 ;
    END
  END pd1[296]
  PIN pd1[297]
    DIRECTION OUTPUT ;
    USE SIGNAL ;
    PORT
      LAYER M5 ;
        RECT  135.312 129.516 135.336 129.6 ;
    END
  END pd1[297]
  PIN pd1[298]
    DIRECTION OUTPUT ;
    USE SIGNAL ;
    PORT
      LAYER M5 ;
        RECT  135.408 129.516 135.432 129.6 ;
    END
  END pd1[298]
  PIN pd1[299]
    DIRECTION OUTPUT ;
    USE SIGNAL ;
    PORT
      LAYER M5 ;
        RECT  135.504 129.516 135.528 129.6 ;
    END
  END pd1[299]
  PIN pd1[29]
    DIRECTION OUTPUT ;
    USE SIGNAL ;
    PORT
      LAYER M5 ;
        RECT  162.576 129.516 162.6 129.6 ;
    END
  END pd1[29]
  PIN pd1[2]
    DIRECTION OUTPUT ;
    USE SIGNAL ;
    PORT
      LAYER M5 ;
        RECT  159.984 129.516 160.008 129.6 ;
    END
  END pd1[2]
  PIN pd1[300]
    DIRECTION OUTPUT ;
    USE SIGNAL ;
    PORT
      LAYER M5 ;
        RECT  135.6 129.516 135.624 129.6 ;
    END
  END pd1[300]
  PIN pd1[301]
    DIRECTION OUTPUT ;
    USE SIGNAL ;
    PORT
      LAYER M5 ;
        RECT  135.696 129.516 135.72 129.6 ;
    END
  END pd1[301]
  PIN pd1[302]
    DIRECTION OUTPUT ;
    USE SIGNAL ;
    PORT
      LAYER M5 ;
        RECT  135.792 129.516 135.816 129.6 ;
    END
  END pd1[302]
  PIN pd1[303]
    DIRECTION OUTPUT ;
    USE SIGNAL ;
    PORT
      LAYER M5 ;
        RECT  135.888 129.516 135.912 129.6 ;
    END
  END pd1[303]
  PIN pd1[304]
    DIRECTION OUTPUT ;
    USE SIGNAL ;
    PORT
      LAYER M5 ;
        RECT  135.984 129.516 136.008 129.6 ;
    END
  END pd1[304]
  PIN pd1[305]
    DIRECTION OUTPUT ;
    USE SIGNAL ;
    PORT
      LAYER M5 ;
        RECT  136.08 129.516 136.104 129.6 ;
    END
  END pd1[305]
  PIN pd1[306]
    DIRECTION OUTPUT ;
    USE SIGNAL ;
    PORT
      LAYER M5 ;
        RECT  136.176 129.516 136.2 129.6 ;
    END
  END pd1[306]
  PIN pd1[307]
    DIRECTION OUTPUT ;
    USE SIGNAL ;
    PORT
      LAYER M5 ;
        RECT  136.272 129.516 136.296 129.6 ;
    END
  END pd1[307]
  PIN pd1[308]
    DIRECTION OUTPUT ;
    USE SIGNAL ;
    PORT
      LAYER M5 ;
        RECT  136.368 129.516 136.392 129.6 ;
    END
  END pd1[308]
  PIN pd1[309]
    DIRECTION OUTPUT ;
    USE SIGNAL ;
    PORT
      LAYER M5 ;
        RECT  136.464 129.516 136.488 129.6 ;
    END
  END pd1[309]
  PIN pd1[30]
    DIRECTION OUTPUT ;
    USE SIGNAL ;
    PORT
      LAYER M5 ;
        RECT  162.672 129.516 162.696 129.6 ;
    END
  END pd1[30]
  PIN pd1[310]
    DIRECTION OUTPUT ;
    USE SIGNAL ;
    PORT
      LAYER M5 ;
        RECT  136.56 129.516 136.584 129.6 ;
    END
  END pd1[310]
  PIN pd1[311]
    DIRECTION OUTPUT ;
    USE SIGNAL ;
    PORT
      LAYER M5 ;
        RECT  136.656 129.516 136.68 129.6 ;
    END
  END pd1[311]
  PIN pd1[312]
    DIRECTION OUTPUT ;
    USE SIGNAL ;
    PORT
      LAYER M5 ;
        RECT  136.752 129.516 136.776 129.6 ;
    END
  END pd1[312]
  PIN pd1[313]
    DIRECTION OUTPUT ;
    USE SIGNAL ;
    PORT
      LAYER M5 ;
        RECT  136.848 129.516 136.872 129.6 ;
    END
  END pd1[313]
  PIN pd1[314]
    DIRECTION OUTPUT ;
    USE SIGNAL ;
    PORT
      LAYER M5 ;
        RECT  136.944 129.516 136.968 129.6 ;
    END
  END pd1[314]
  PIN pd1[315]
    DIRECTION OUTPUT ;
    USE SIGNAL ;
    PORT
      LAYER M5 ;
        RECT  137.04 129.516 137.064 129.6 ;
    END
  END pd1[315]
  PIN pd1[316]
    DIRECTION OUTPUT ;
    USE SIGNAL ;
    PORT
      LAYER M5 ;
        RECT  137.136 129.516 137.16 129.6 ;
    END
  END pd1[316]
  PIN pd1[317]
    DIRECTION OUTPUT ;
    USE SIGNAL ;
    PORT
      LAYER M5 ;
        RECT  137.232 129.516 137.256 129.6 ;
    END
  END pd1[317]
  PIN pd1[318]
    DIRECTION OUTPUT ;
    USE SIGNAL ;
    PORT
      LAYER M5 ;
        RECT  137.328 129.516 137.352 129.6 ;
    END
  END pd1[318]
  PIN pd1[319]
    DIRECTION OUTPUT ;
    USE SIGNAL ;
    PORT
      LAYER M5 ;
        RECT  137.424 129.516 137.448 129.6 ;
    END
  END pd1[319]
  PIN pd1[31]
    DIRECTION OUTPUT ;
    USE SIGNAL ;
    PORT
      LAYER M5 ;
        RECT  162.768 129.516 162.792 129.6 ;
    END
  END pd1[31]
  PIN pd1[320]
    DIRECTION OUTPUT ;
    USE SIGNAL ;
    PORT
      LAYER M5 ;
        RECT  50.736 129.516 50.76 129.6 ;
    END
  END pd1[320]
  PIN pd1[321]
    DIRECTION OUTPUT ;
    USE SIGNAL ;
    PORT
      LAYER M5 ;
        RECT  50.832 129.516 50.856 129.6 ;
    END
  END pd1[321]
  PIN pd1[322]
    DIRECTION OUTPUT ;
    USE SIGNAL ;
    PORT
      LAYER M5 ;
        RECT  50.928 129.516 50.952 129.6 ;
    END
  END pd1[322]
  PIN pd1[323]
    DIRECTION OUTPUT ;
    USE SIGNAL ;
    PORT
      LAYER M5 ;
        RECT  51.024 129.516 51.048 129.6 ;
    END
  END pd1[323]
  PIN pd1[324]
    DIRECTION OUTPUT ;
    USE SIGNAL ;
    PORT
      LAYER M5 ;
        RECT  51.12 129.516 51.144 129.6 ;
    END
  END pd1[324]
  PIN pd1[325]
    DIRECTION OUTPUT ;
    USE SIGNAL ;
    PORT
      LAYER M5 ;
        RECT  51.216 129.516 51.24 129.6 ;
    END
  END pd1[325]
  PIN pd1[326]
    DIRECTION OUTPUT ;
    USE SIGNAL ;
    PORT
      LAYER M5 ;
        RECT  51.312 129.516 51.336 129.6 ;
    END
  END pd1[326]
  PIN pd1[327]
    DIRECTION OUTPUT ;
    USE SIGNAL ;
    PORT
      LAYER M5 ;
        RECT  51.408 129.516 51.432 129.6 ;
    END
  END pd1[327]
  PIN pd1[328]
    DIRECTION OUTPUT ;
    USE SIGNAL ;
    PORT
      LAYER M5 ;
        RECT  51.504 129.516 51.528 129.6 ;
    END
  END pd1[328]
  PIN pd1[329]
    DIRECTION OUTPUT ;
    USE SIGNAL ;
    PORT
      LAYER M5 ;
        RECT  51.6 129.516 51.624 129.6 ;
    END
  END pd1[329]
  PIN pd1[32]
    DIRECTION OUTPUT ;
    USE SIGNAL ;
    PORT
      LAYER M5 ;
        RECT  76.848 129.516 76.872 129.6 ;
    END
  END pd1[32]
  PIN pd1[330]
    DIRECTION OUTPUT ;
    USE SIGNAL ;
    PORT
      LAYER M5 ;
        RECT  51.696 129.516 51.72 129.6 ;
    END
  END pd1[330]
  PIN pd1[331]
    DIRECTION OUTPUT ;
    USE SIGNAL ;
    PORT
      LAYER M5 ;
        RECT  51.792 129.516 51.816 129.6 ;
    END
  END pd1[331]
  PIN pd1[332]
    DIRECTION OUTPUT ;
    USE SIGNAL ;
    PORT
      LAYER M5 ;
        RECT  51.888 129.516 51.912 129.6 ;
    END
  END pd1[332]
  PIN pd1[333]
    DIRECTION OUTPUT ;
    USE SIGNAL ;
    PORT
      LAYER M5 ;
        RECT  51.984 129.516 52.008 129.6 ;
    END
  END pd1[333]
  PIN pd1[334]
    DIRECTION OUTPUT ;
    USE SIGNAL ;
    PORT
      LAYER M5 ;
        RECT  52.08 129.516 52.104 129.6 ;
    END
  END pd1[334]
  PIN pd1[335]
    DIRECTION OUTPUT ;
    USE SIGNAL ;
    PORT
      LAYER M5 ;
        RECT  52.176 129.516 52.2 129.6 ;
    END
  END pd1[335]
  PIN pd1[336]
    DIRECTION OUTPUT ;
    USE SIGNAL ;
    PORT
      LAYER M5 ;
        RECT  52.272 129.516 52.296 129.6 ;
    END
  END pd1[336]
  PIN pd1[337]
    DIRECTION OUTPUT ;
    USE SIGNAL ;
    PORT
      LAYER M5 ;
        RECT  52.368 129.516 52.392 129.6 ;
    END
  END pd1[337]
  PIN pd1[338]
    DIRECTION OUTPUT ;
    USE SIGNAL ;
    PORT
      LAYER M5 ;
        RECT  52.464 129.516 52.488 129.6 ;
    END
  END pd1[338]
  PIN pd1[339]
    DIRECTION OUTPUT ;
    USE SIGNAL ;
    PORT
      LAYER M5 ;
        RECT  52.56 129.516 52.584 129.6 ;
    END
  END pd1[339]
  PIN pd1[33]
    DIRECTION OUTPUT ;
    USE SIGNAL ;
    PORT
      LAYER M5 ;
        RECT  76.944 129.516 76.968 129.6 ;
    END
  END pd1[33]
  PIN pd1[340]
    DIRECTION OUTPUT ;
    USE SIGNAL ;
    PORT
      LAYER M5 ;
        RECT  52.656 129.516 52.68 129.6 ;
    END
  END pd1[340]
  PIN pd1[341]
    DIRECTION OUTPUT ;
    USE SIGNAL ;
    PORT
      LAYER M5 ;
        RECT  52.752 129.516 52.776 129.6 ;
    END
  END pd1[341]
  PIN pd1[342]
    DIRECTION OUTPUT ;
    USE SIGNAL ;
    PORT
      LAYER M5 ;
        RECT  52.848 129.516 52.872 129.6 ;
    END
  END pd1[342]
  PIN pd1[343]
    DIRECTION OUTPUT ;
    USE SIGNAL ;
    PORT
      LAYER M5 ;
        RECT  52.944 129.516 52.968 129.6 ;
    END
  END pd1[343]
  PIN pd1[344]
    DIRECTION OUTPUT ;
    USE SIGNAL ;
    PORT
      LAYER M5 ;
        RECT  53.04 129.516 53.064 129.6 ;
    END
  END pd1[344]
  PIN pd1[345]
    DIRECTION OUTPUT ;
    USE SIGNAL ;
    PORT
      LAYER M5 ;
        RECT  53.136 129.516 53.16 129.6 ;
    END
  END pd1[345]
  PIN pd1[346]
    DIRECTION OUTPUT ;
    USE SIGNAL ;
    PORT
      LAYER M5 ;
        RECT  53.232 129.516 53.256 129.6 ;
    END
  END pd1[346]
  PIN pd1[347]
    DIRECTION OUTPUT ;
    USE SIGNAL ;
    PORT
      LAYER M5 ;
        RECT  53.328 129.516 53.352 129.6 ;
    END
  END pd1[347]
  PIN pd1[348]
    DIRECTION OUTPUT ;
    USE SIGNAL ;
    PORT
      LAYER M5 ;
        RECT  53.424 129.516 53.448 129.6 ;
    END
  END pd1[348]
  PIN pd1[349]
    DIRECTION OUTPUT ;
    USE SIGNAL ;
    PORT
      LAYER M5 ;
        RECT  53.52 129.516 53.544 129.6 ;
    END
  END pd1[349]
  PIN pd1[34]
    DIRECTION OUTPUT ;
    USE SIGNAL ;
    PORT
      LAYER M5 ;
        RECT  77.04 129.516 77.064 129.6 ;
    END
  END pd1[34]
  PIN pd1[350]
    DIRECTION OUTPUT ;
    USE SIGNAL ;
    PORT
      LAYER M5 ;
        RECT  53.616 129.516 53.64 129.6 ;
    END
  END pd1[350]
  PIN pd1[351]
    DIRECTION OUTPUT ;
    USE SIGNAL ;
    PORT
      LAYER M5 ;
        RECT  53.712 129.516 53.736 129.6 ;
    END
  END pd1[351]
  PIN pd1[352]
    DIRECTION OUTPUT ;
    USE SIGNAL ;
    PORT
      LAYER M5 ;
        RECT  86.064 129.516 86.088 129.6 ;
    END
  END pd1[352]
  PIN pd1[353]
    DIRECTION OUTPUT ;
    USE SIGNAL ;
    PORT
      LAYER M5 ;
        RECT  86.16 129.516 86.184 129.6 ;
    END
  END pd1[353]
  PIN pd1[354]
    DIRECTION OUTPUT ;
    USE SIGNAL ;
    PORT
      LAYER M5 ;
        RECT  86.256 129.516 86.28 129.6 ;
    END
  END pd1[354]
  PIN pd1[355]
    DIRECTION OUTPUT ;
    USE SIGNAL ;
    PORT
      LAYER M5 ;
        RECT  86.352 129.516 86.376 129.6 ;
    END
  END pd1[355]
  PIN pd1[356]
    DIRECTION OUTPUT ;
    USE SIGNAL ;
    PORT
      LAYER M5 ;
        RECT  86.448 129.516 86.472 129.6 ;
    END
  END pd1[356]
  PIN pd1[357]
    DIRECTION OUTPUT ;
    USE SIGNAL ;
    PORT
      LAYER M5 ;
        RECT  86.544 129.516 86.568 129.6 ;
    END
  END pd1[357]
  PIN pd1[358]
    DIRECTION OUTPUT ;
    USE SIGNAL ;
    PORT
      LAYER M5 ;
        RECT  86.64 129.516 86.664 129.6 ;
    END
  END pd1[358]
  PIN pd1[359]
    DIRECTION OUTPUT ;
    USE SIGNAL ;
    PORT
      LAYER M5 ;
        RECT  86.736 129.516 86.76 129.6 ;
    END
  END pd1[359]
  PIN pd1[35]
    DIRECTION OUTPUT ;
    USE SIGNAL ;
    PORT
      LAYER M5 ;
        RECT  77.136 129.516 77.16 129.6 ;
    END
  END pd1[35]
  PIN pd1[360]
    DIRECTION OUTPUT ;
    USE SIGNAL ;
    PORT
      LAYER M5 ;
        RECT  86.832 129.516 86.856 129.6 ;
    END
  END pd1[360]
  PIN pd1[361]
    DIRECTION OUTPUT ;
    USE SIGNAL ;
    PORT
      LAYER M5 ;
        RECT  86.928 129.516 86.952 129.6 ;
    END
  END pd1[361]
  PIN pd1[362]
    DIRECTION OUTPUT ;
    USE SIGNAL ;
    PORT
      LAYER M5 ;
        RECT  87.024 129.516 87.048 129.6 ;
    END
  END pd1[362]
  PIN pd1[363]
    DIRECTION OUTPUT ;
    USE SIGNAL ;
    PORT
      LAYER M5 ;
        RECT  87.12 129.516 87.144 129.6 ;
    END
  END pd1[363]
  PIN pd1[364]
    DIRECTION OUTPUT ;
    USE SIGNAL ;
    PORT
      LAYER M5 ;
        RECT  87.216 129.516 87.24 129.6 ;
    END
  END pd1[364]
  PIN pd1[365]
    DIRECTION OUTPUT ;
    USE SIGNAL ;
    PORT
      LAYER M5 ;
        RECT  87.312 129.516 87.336 129.6 ;
    END
  END pd1[365]
  PIN pd1[366]
    DIRECTION OUTPUT ;
    USE SIGNAL ;
    PORT
      LAYER M5 ;
        RECT  87.408 129.516 87.432 129.6 ;
    END
  END pd1[366]
  PIN pd1[367]
    DIRECTION OUTPUT ;
    USE SIGNAL ;
    PORT
      LAYER M5 ;
        RECT  87.504 129.516 87.528 129.6 ;
    END
  END pd1[367]
  PIN pd1[368]
    DIRECTION OUTPUT ;
    USE SIGNAL ;
    PORT
      LAYER M5 ;
        RECT  87.6 129.516 87.624 129.6 ;
    END
  END pd1[368]
  PIN pd1[369]
    DIRECTION OUTPUT ;
    USE SIGNAL ;
    PORT
      LAYER M5 ;
        RECT  87.696 129.516 87.72 129.6 ;
    END
  END pd1[369]
  PIN pd1[36]
    DIRECTION OUTPUT ;
    USE SIGNAL ;
    PORT
      LAYER M5 ;
        RECT  77.232 129.516 77.256 129.6 ;
    END
  END pd1[36]
  PIN pd1[370]
    DIRECTION OUTPUT ;
    USE SIGNAL ;
    PORT
      LAYER M5 ;
        RECT  87.792 129.516 87.816 129.6 ;
    END
  END pd1[370]
  PIN pd1[371]
    DIRECTION OUTPUT ;
    USE SIGNAL ;
    PORT
      LAYER M5 ;
        RECT  87.888 129.516 87.912 129.6 ;
    END
  END pd1[371]
  PIN pd1[372]
    DIRECTION OUTPUT ;
    USE SIGNAL ;
    PORT
      LAYER M5 ;
        RECT  87.984 129.516 88.008 129.6 ;
    END
  END pd1[372]
  PIN pd1[373]
    DIRECTION OUTPUT ;
    USE SIGNAL ;
    PORT
      LAYER M5 ;
        RECT  88.08 129.516 88.104 129.6 ;
    END
  END pd1[373]
  PIN pd1[374]
    DIRECTION OUTPUT ;
    USE SIGNAL ;
    PORT
      LAYER M5 ;
        RECT  88.176 129.516 88.2 129.6 ;
    END
  END pd1[374]
  PIN pd1[375]
    DIRECTION OUTPUT ;
    USE SIGNAL ;
    PORT
      LAYER M5 ;
        RECT  88.272 129.516 88.296 129.6 ;
    END
  END pd1[375]
  PIN pd1[376]
    DIRECTION OUTPUT ;
    USE SIGNAL ;
    PORT
      LAYER M5 ;
        RECT  88.368 129.516 88.392 129.6 ;
    END
  END pd1[376]
  PIN pd1[377]
    DIRECTION OUTPUT ;
    USE SIGNAL ;
    PORT
      LAYER M5 ;
        RECT  88.464 129.516 88.488 129.6 ;
    END
  END pd1[377]
  PIN pd1[378]
    DIRECTION OUTPUT ;
    USE SIGNAL ;
    PORT
      LAYER M5 ;
        RECT  88.56 129.516 88.584 129.6 ;
    END
  END pd1[378]
  PIN pd1[379]
    DIRECTION OUTPUT ;
    USE SIGNAL ;
    PORT
      LAYER M5 ;
        RECT  88.656 129.516 88.68 129.6 ;
    END
  END pd1[379]
  PIN pd1[37]
    DIRECTION OUTPUT ;
    USE SIGNAL ;
    PORT
      LAYER M5 ;
        RECT  77.328 129.516 77.352 129.6 ;
    END
  END pd1[37]
  PIN pd1[380]
    DIRECTION OUTPUT ;
    USE SIGNAL ;
    PORT
      LAYER M5 ;
        RECT  88.752 129.516 88.776 129.6 ;
    END
  END pd1[380]
  PIN pd1[381]
    DIRECTION OUTPUT ;
    USE SIGNAL ;
    PORT
      LAYER M5 ;
        RECT  88.848 129.516 88.872 129.6 ;
    END
  END pd1[381]
  PIN pd1[382]
    DIRECTION OUTPUT ;
    USE SIGNAL ;
    PORT
      LAYER M5 ;
        RECT  88.944 129.516 88.968 129.6 ;
    END
  END pd1[382]
  PIN pd1[383]
    DIRECTION OUTPUT ;
    USE SIGNAL ;
    PORT
      LAYER M5 ;
        RECT  89.04 129.516 89.064 129.6 ;
    END
  END pd1[383]
  PIN pd1[384]
    DIRECTION OUTPUT ;
    USE SIGNAL ;
    PORT
      LAYER M5 ;
        RECT  165.936 129.516 165.96 129.6 ;
    END
  END pd1[384]
  PIN pd1[385]
    DIRECTION OUTPUT ;
    USE SIGNAL ;
    PORT
      LAYER M5 ;
        RECT  166.032 129.516 166.056 129.6 ;
    END
  END pd1[385]
  PIN pd1[386]
    DIRECTION OUTPUT ;
    USE SIGNAL ;
    PORT
      LAYER M5 ;
        RECT  166.128 129.516 166.152 129.6 ;
    END
  END pd1[386]
  PIN pd1[387]
    DIRECTION OUTPUT ;
    USE SIGNAL ;
    PORT
      LAYER M5 ;
        RECT  166.224 129.516 166.248 129.6 ;
    END
  END pd1[387]
  PIN pd1[388]
    DIRECTION OUTPUT ;
    USE SIGNAL ;
    PORT
      LAYER M5 ;
        RECT  166.32 129.516 166.344 129.6 ;
    END
  END pd1[388]
  PIN pd1[389]
    DIRECTION OUTPUT ;
    USE SIGNAL ;
    PORT
      LAYER M5 ;
        RECT  166.416 129.516 166.44 129.6 ;
    END
  END pd1[389]
  PIN pd1[38]
    DIRECTION OUTPUT ;
    USE SIGNAL ;
    PORT
      LAYER M5 ;
        RECT  77.424 129.516 77.448 129.6 ;
    END
  END pd1[38]
  PIN pd1[390]
    DIRECTION OUTPUT ;
    USE SIGNAL ;
    PORT
      LAYER M5 ;
        RECT  166.512 129.516 166.536 129.6 ;
    END
  END pd1[390]
  PIN pd1[391]
    DIRECTION OUTPUT ;
    USE SIGNAL ;
    PORT
      LAYER M5 ;
        RECT  166.608 129.516 166.632 129.6 ;
    END
  END pd1[391]
  PIN pd1[392]
    DIRECTION OUTPUT ;
    USE SIGNAL ;
    PORT
      LAYER M5 ;
        RECT  166.704 129.516 166.728 129.6 ;
    END
  END pd1[392]
  PIN pd1[393]
    DIRECTION OUTPUT ;
    USE SIGNAL ;
    PORT
      LAYER M5 ;
        RECT  166.8 129.516 166.824 129.6 ;
    END
  END pd1[393]
  PIN pd1[394]
    DIRECTION OUTPUT ;
    USE SIGNAL ;
    PORT
      LAYER M5 ;
        RECT  166.896 129.516 166.92 129.6 ;
    END
  END pd1[394]
  PIN pd1[395]
    DIRECTION OUTPUT ;
    USE SIGNAL ;
    PORT
      LAYER M5 ;
        RECT  166.992 129.516 167.016 129.6 ;
    END
  END pd1[395]
  PIN pd1[396]
    DIRECTION OUTPUT ;
    USE SIGNAL ;
    PORT
      LAYER M5 ;
        RECT  167.088 129.516 167.112 129.6 ;
    END
  END pd1[396]
  PIN pd1[397]
    DIRECTION OUTPUT ;
    USE SIGNAL ;
    PORT
      LAYER M5 ;
        RECT  167.184 129.516 167.208 129.6 ;
    END
  END pd1[397]
  PIN pd1[398]
    DIRECTION OUTPUT ;
    USE SIGNAL ;
    PORT
      LAYER M5 ;
        RECT  167.28 129.516 167.304 129.6 ;
    END
  END pd1[398]
  PIN pd1[399]
    DIRECTION OUTPUT ;
    USE SIGNAL ;
    PORT
      LAYER M5 ;
        RECT  167.376 129.516 167.4 129.6 ;
    END
  END pd1[399]
  PIN pd1[39]
    DIRECTION OUTPUT ;
    USE SIGNAL ;
    PORT
      LAYER M5 ;
        RECT  77.52 129.516 77.544 129.6 ;
    END
  END pd1[39]
  PIN pd1[3]
    DIRECTION OUTPUT ;
    USE SIGNAL ;
    PORT
      LAYER M5 ;
        RECT  160.08 129.516 160.104 129.6 ;
    END
  END pd1[3]
  PIN pd1[400]
    DIRECTION OUTPUT ;
    USE SIGNAL ;
    PORT
      LAYER M5 ;
        RECT  167.472 129.516 167.496 129.6 ;
    END
  END pd1[400]
  PIN pd1[401]
    DIRECTION OUTPUT ;
    USE SIGNAL ;
    PORT
      LAYER M5 ;
        RECT  167.568 129.516 167.592 129.6 ;
    END
  END pd1[401]
  PIN pd1[402]
    DIRECTION OUTPUT ;
    USE SIGNAL ;
    PORT
      LAYER M5 ;
        RECT  167.664 129.516 167.688 129.6 ;
    END
  END pd1[402]
  PIN pd1[403]
    DIRECTION OUTPUT ;
    USE SIGNAL ;
    PORT
      LAYER M5 ;
        RECT  167.76 129.516 167.784 129.6 ;
    END
  END pd1[403]
  PIN pd1[404]
    DIRECTION OUTPUT ;
    USE SIGNAL ;
    PORT
      LAYER M5 ;
        RECT  167.856 129.516 167.88 129.6 ;
    END
  END pd1[404]
  PIN pd1[405]
    DIRECTION OUTPUT ;
    USE SIGNAL ;
    PORT
      LAYER M5 ;
        RECT  167.952 129.516 167.976 129.6 ;
    END
  END pd1[405]
  PIN pd1[406]
    DIRECTION OUTPUT ;
    USE SIGNAL ;
    PORT
      LAYER M5 ;
        RECT  168.048 129.516 168.072 129.6 ;
    END
  END pd1[406]
  PIN pd1[407]
    DIRECTION OUTPUT ;
    USE SIGNAL ;
    PORT
      LAYER M5 ;
        RECT  168.144 129.516 168.168 129.6 ;
    END
  END pd1[407]
  PIN pd1[408]
    DIRECTION OUTPUT ;
    USE SIGNAL ;
    PORT
      LAYER M5 ;
        RECT  168.24 129.516 168.264 129.6 ;
    END
  END pd1[408]
  PIN pd1[409]
    DIRECTION OUTPUT ;
    USE SIGNAL ;
    PORT
      LAYER M5 ;
        RECT  168.336 129.516 168.36 129.6 ;
    END
  END pd1[409]
  PIN pd1[40]
    DIRECTION OUTPUT ;
    USE SIGNAL ;
    PORT
      LAYER M5 ;
        RECT  77.616 129.516 77.64 129.6 ;
    END
  END pd1[40]
  PIN pd1[410]
    DIRECTION OUTPUT ;
    USE SIGNAL ;
    PORT
      LAYER M5 ;
        RECT  168.432 129.516 168.456 129.6 ;
    END
  END pd1[410]
  PIN pd1[411]
    DIRECTION OUTPUT ;
    USE SIGNAL ;
    PORT
      LAYER M5 ;
        RECT  168.528 129.516 168.552 129.6 ;
    END
  END pd1[411]
  PIN pd1[412]
    DIRECTION OUTPUT ;
    USE SIGNAL ;
    PORT
      LAYER M5 ;
        RECT  168.624 129.516 168.648 129.6 ;
    END
  END pd1[412]
  PIN pd1[413]
    DIRECTION OUTPUT ;
    USE SIGNAL ;
    PORT
      LAYER M5 ;
        RECT  168.72 129.516 168.744 129.6 ;
    END
  END pd1[413]
  PIN pd1[414]
    DIRECTION OUTPUT ;
    USE SIGNAL ;
    PORT
      LAYER M5 ;
        RECT  168.816 129.516 168.84 129.6 ;
    END
  END pd1[414]
  PIN pd1[415]
    DIRECTION OUTPUT ;
    USE SIGNAL ;
    PORT
      LAYER M5 ;
        RECT  168.912 129.516 168.936 129.6 ;
    END
  END pd1[415]
  PIN pd1[416]
    DIRECTION OUTPUT ;
    USE SIGNAL ;
    PORT
      LAYER M5 ;
        RECT  96.048 129.516 96.072 129.6 ;
    END
  END pd1[416]
  PIN pd1[417]
    DIRECTION OUTPUT ;
    USE SIGNAL ;
    PORT
      LAYER M5 ;
        RECT  96.144 129.516 96.168 129.6 ;
    END
  END pd1[417]
  PIN pd1[418]
    DIRECTION OUTPUT ;
    USE SIGNAL ;
    PORT
      LAYER M5 ;
        RECT  96.24 129.516 96.264 129.6 ;
    END
  END pd1[418]
  PIN pd1[419]
    DIRECTION OUTPUT ;
    USE SIGNAL ;
    PORT
      LAYER M5 ;
        RECT  96.336 129.516 96.36 129.6 ;
    END
  END pd1[419]
  PIN pd1[41]
    DIRECTION OUTPUT ;
    USE SIGNAL ;
    PORT
      LAYER M5 ;
        RECT  77.712 129.516 77.736 129.6 ;
    END
  END pd1[41]
  PIN pd1[420]
    DIRECTION OUTPUT ;
    USE SIGNAL ;
    PORT
      LAYER M5 ;
        RECT  96.432 129.516 96.456 129.6 ;
    END
  END pd1[420]
  PIN pd1[421]
    DIRECTION OUTPUT ;
    USE SIGNAL ;
    PORT
      LAYER M5 ;
        RECT  96.528 129.516 96.552 129.6 ;
    END
  END pd1[421]
  PIN pd1[422]
    DIRECTION OUTPUT ;
    USE SIGNAL ;
    PORT
      LAYER M5 ;
        RECT  96.624 129.516 96.648 129.6 ;
    END
  END pd1[422]
  PIN pd1[423]
    DIRECTION OUTPUT ;
    USE SIGNAL ;
    PORT
      LAYER M5 ;
        RECT  96.72 129.516 96.744 129.6 ;
    END
  END pd1[423]
  PIN pd1[424]
    DIRECTION OUTPUT ;
    USE SIGNAL ;
    PORT
      LAYER M5 ;
        RECT  96.816 129.516 96.84 129.6 ;
    END
  END pd1[424]
  PIN pd1[425]
    DIRECTION OUTPUT ;
    USE SIGNAL ;
    PORT
      LAYER M5 ;
        RECT  96.912 129.516 96.936 129.6 ;
    END
  END pd1[425]
  PIN pd1[426]
    DIRECTION OUTPUT ;
    USE SIGNAL ;
    PORT
      LAYER M5 ;
        RECT  97.008 129.516 97.032 129.6 ;
    END
  END pd1[426]
  PIN pd1[427]
    DIRECTION OUTPUT ;
    USE SIGNAL ;
    PORT
      LAYER M5 ;
        RECT  97.104 129.516 97.128 129.6 ;
    END
  END pd1[427]
  PIN pd1[428]
    DIRECTION OUTPUT ;
    USE SIGNAL ;
    PORT
      LAYER M5 ;
        RECT  97.2 129.516 97.224 129.6 ;
    END
  END pd1[428]
  PIN pd1[429]
    DIRECTION OUTPUT ;
    USE SIGNAL ;
    PORT
      LAYER M5 ;
        RECT  97.296 129.516 97.32 129.6 ;
    END
  END pd1[429]
  PIN pd1[42]
    DIRECTION OUTPUT ;
    USE SIGNAL ;
    PORT
      LAYER M5 ;
        RECT  77.808 129.516 77.832 129.6 ;
    END
  END pd1[42]
  PIN pd1[430]
    DIRECTION OUTPUT ;
    USE SIGNAL ;
    PORT
      LAYER M5 ;
        RECT  97.392 129.516 97.416 129.6 ;
    END
  END pd1[430]
  PIN pd1[431]
    DIRECTION OUTPUT ;
    USE SIGNAL ;
    PORT
      LAYER M5 ;
        RECT  97.488 129.516 97.512 129.6 ;
    END
  END pd1[431]
  PIN pd1[432]
    DIRECTION OUTPUT ;
    USE SIGNAL ;
    PORT
      LAYER M5 ;
        RECT  97.584 129.516 97.608 129.6 ;
    END
  END pd1[432]
  PIN pd1[433]
    DIRECTION OUTPUT ;
    USE SIGNAL ;
    PORT
      LAYER M5 ;
        RECT  97.68 129.516 97.704 129.6 ;
    END
  END pd1[433]
  PIN pd1[434]
    DIRECTION OUTPUT ;
    USE SIGNAL ;
    PORT
      LAYER M5 ;
        RECT  97.776 129.516 97.8 129.6 ;
    END
  END pd1[434]
  PIN pd1[435]
    DIRECTION OUTPUT ;
    USE SIGNAL ;
    PORT
      LAYER M5 ;
        RECT  97.872 129.516 97.896 129.6 ;
    END
  END pd1[435]
  PIN pd1[436]
    DIRECTION OUTPUT ;
    USE SIGNAL ;
    PORT
      LAYER M5 ;
        RECT  97.968 129.516 97.992 129.6 ;
    END
  END pd1[436]
  PIN pd1[437]
    DIRECTION OUTPUT ;
    USE SIGNAL ;
    PORT
      LAYER M5 ;
        RECT  98.064 129.516 98.088 129.6 ;
    END
  END pd1[437]
  PIN pd1[438]
    DIRECTION OUTPUT ;
    USE SIGNAL ;
    PORT
      LAYER M5 ;
        RECT  98.16 129.516 98.184 129.6 ;
    END
  END pd1[438]
  PIN pd1[439]
    DIRECTION OUTPUT ;
    USE SIGNAL ;
    PORT
      LAYER M5 ;
        RECT  98.256 129.516 98.28 129.6 ;
    END
  END pd1[439]
  PIN pd1[43]
    DIRECTION OUTPUT ;
    USE SIGNAL ;
    PORT
      LAYER M5 ;
        RECT  77.904 129.516 77.928 129.6 ;
    END
  END pd1[43]
  PIN pd1[440]
    DIRECTION OUTPUT ;
    USE SIGNAL ;
    PORT
      LAYER M5 ;
        RECT  98.352 129.516 98.376 129.6 ;
    END
  END pd1[440]
  PIN pd1[441]
    DIRECTION OUTPUT ;
    USE SIGNAL ;
    PORT
      LAYER M5 ;
        RECT  98.448 129.516 98.472 129.6 ;
    END
  END pd1[441]
  PIN pd1[442]
    DIRECTION OUTPUT ;
    USE SIGNAL ;
    PORT
      LAYER M5 ;
        RECT  98.544 129.516 98.568 129.6 ;
    END
  END pd1[442]
  PIN pd1[443]
    DIRECTION OUTPUT ;
    USE SIGNAL ;
    PORT
      LAYER M5 ;
        RECT  98.64 129.516 98.664 129.6 ;
    END
  END pd1[443]
  PIN pd1[444]
    DIRECTION OUTPUT ;
    USE SIGNAL ;
    PORT
      LAYER M5 ;
        RECT  98.736 129.516 98.76 129.6 ;
    END
  END pd1[444]
  PIN pd1[445]
    DIRECTION OUTPUT ;
    USE SIGNAL ;
    PORT
      LAYER M5 ;
        RECT  98.832 129.516 98.856 129.6 ;
    END
  END pd1[445]
  PIN pd1[446]
    DIRECTION OUTPUT ;
    USE SIGNAL ;
    PORT
      LAYER M5 ;
        RECT  98.928 129.516 98.952 129.6 ;
    END
  END pd1[446]
  PIN pd1[447]
    DIRECTION OUTPUT ;
    USE SIGNAL ;
    PORT
      LAYER M5 ;
        RECT  99.024 129.516 99.048 129.6 ;
    END
  END pd1[447]
  PIN pd1[448]
    DIRECTION OUTPUT ;
    USE SIGNAL ;
    PORT
      LAYER M5 ;
        RECT  102.192 129.516 102.216 129.6 ;
    END
  END pd1[448]
  PIN pd1[449]
    DIRECTION OUTPUT ;
    USE SIGNAL ;
    PORT
      LAYER M5 ;
        RECT  102.288 129.516 102.312 129.6 ;
    END
  END pd1[449]
  PIN pd1[44]
    DIRECTION OUTPUT ;
    USE SIGNAL ;
    PORT
      LAYER M5 ;
        RECT  78 129.516 78.024 129.6 ;
    END
  END pd1[44]
  PIN pd1[450]
    DIRECTION OUTPUT ;
    USE SIGNAL ;
    PORT
      LAYER M5 ;
        RECT  102.384 129.516 102.408 129.6 ;
    END
  END pd1[450]
  PIN pd1[451]
    DIRECTION OUTPUT ;
    USE SIGNAL ;
    PORT
      LAYER M5 ;
        RECT  102.48 129.516 102.504 129.6 ;
    END
  END pd1[451]
  PIN pd1[452]
    DIRECTION OUTPUT ;
    USE SIGNAL ;
    PORT
      LAYER M5 ;
        RECT  102.576 129.516 102.6 129.6 ;
    END
  END pd1[452]
  PIN pd1[453]
    DIRECTION OUTPUT ;
    USE SIGNAL ;
    PORT
      LAYER M5 ;
        RECT  102.672 129.516 102.696 129.6 ;
    END
  END pd1[453]
  PIN pd1[454]
    DIRECTION OUTPUT ;
    USE SIGNAL ;
    PORT
      LAYER M5 ;
        RECT  102.768 129.516 102.792 129.6 ;
    END
  END pd1[454]
  PIN pd1[455]
    DIRECTION OUTPUT ;
    USE SIGNAL ;
    PORT
      LAYER M5 ;
        RECT  102.864 129.516 102.888 129.6 ;
    END
  END pd1[455]
  PIN pd1[456]
    DIRECTION OUTPUT ;
    USE SIGNAL ;
    PORT
      LAYER M5 ;
        RECT  102.96 129.516 102.984 129.6 ;
    END
  END pd1[456]
  PIN pd1[457]
    DIRECTION OUTPUT ;
    USE SIGNAL ;
    PORT
      LAYER M5 ;
        RECT  103.056 129.516 103.08 129.6 ;
    END
  END pd1[457]
  PIN pd1[458]
    DIRECTION OUTPUT ;
    USE SIGNAL ;
    PORT
      LAYER M5 ;
        RECT  103.152 129.516 103.176 129.6 ;
    END
  END pd1[458]
  PIN pd1[459]
    DIRECTION OUTPUT ;
    USE SIGNAL ;
    PORT
      LAYER M5 ;
        RECT  103.248 129.516 103.272 129.6 ;
    END
  END pd1[459]
  PIN pd1[45]
    DIRECTION OUTPUT ;
    USE SIGNAL ;
    PORT
      LAYER M5 ;
        RECT  78.096 129.516 78.12 129.6 ;
    END
  END pd1[45]
  PIN pd1[460]
    DIRECTION OUTPUT ;
    USE SIGNAL ;
    PORT
      LAYER M5 ;
        RECT  103.344 129.516 103.368 129.6 ;
    END
  END pd1[460]
  PIN pd1[461]
    DIRECTION OUTPUT ;
    USE SIGNAL ;
    PORT
      LAYER M5 ;
        RECT  103.44 129.516 103.464 129.6 ;
    END
  END pd1[461]
  PIN pd1[462]
    DIRECTION OUTPUT ;
    USE SIGNAL ;
    PORT
      LAYER M5 ;
        RECT  103.536 129.516 103.56 129.6 ;
    END
  END pd1[462]
  PIN pd1[463]
    DIRECTION OUTPUT ;
    USE SIGNAL ;
    PORT
      LAYER M5 ;
        RECT  103.632 129.516 103.656 129.6 ;
    END
  END pd1[463]
  PIN pd1[464]
    DIRECTION OUTPUT ;
    USE SIGNAL ;
    PORT
      LAYER M5 ;
        RECT  103.728 129.516 103.752 129.6 ;
    END
  END pd1[464]
  PIN pd1[465]
    DIRECTION OUTPUT ;
    USE SIGNAL ;
    PORT
      LAYER M5 ;
        RECT  103.824 129.516 103.848 129.6 ;
    END
  END pd1[465]
  PIN pd1[466]
    DIRECTION OUTPUT ;
    USE SIGNAL ;
    PORT
      LAYER M5 ;
        RECT  103.92 129.516 103.944 129.6 ;
    END
  END pd1[466]
  PIN pd1[467]
    DIRECTION OUTPUT ;
    USE SIGNAL ;
    PORT
      LAYER M5 ;
        RECT  104.016 129.516 104.04 129.6 ;
    END
  END pd1[467]
  PIN pd1[468]
    DIRECTION OUTPUT ;
    USE SIGNAL ;
    PORT
      LAYER M5 ;
        RECT  104.112 129.516 104.136 129.6 ;
    END
  END pd1[468]
  PIN pd1[469]
    DIRECTION OUTPUT ;
    USE SIGNAL ;
    PORT
      LAYER M5 ;
        RECT  104.208 129.516 104.232 129.6 ;
    END
  END pd1[469]
  PIN pd1[46]
    DIRECTION OUTPUT ;
    USE SIGNAL ;
    PORT
      LAYER M5 ;
        RECT  78.192 129.516 78.216 129.6 ;
    END
  END pd1[46]
  PIN pd1[470]
    DIRECTION OUTPUT ;
    USE SIGNAL ;
    PORT
      LAYER M5 ;
        RECT  104.304 129.516 104.328 129.6 ;
    END
  END pd1[470]
  PIN pd1[471]
    DIRECTION OUTPUT ;
    USE SIGNAL ;
    PORT
      LAYER M5 ;
        RECT  104.4 129.516 104.424 129.6 ;
    END
  END pd1[471]
  PIN pd1[472]
    DIRECTION OUTPUT ;
    USE SIGNAL ;
    PORT
      LAYER M5 ;
        RECT  104.496 129.516 104.52 129.6 ;
    END
  END pd1[472]
  PIN pd1[473]
    DIRECTION OUTPUT ;
    USE SIGNAL ;
    PORT
      LAYER M5 ;
        RECT  104.592 129.516 104.616 129.6 ;
    END
  END pd1[473]
  PIN pd1[474]
    DIRECTION OUTPUT ;
    USE SIGNAL ;
    PORT
      LAYER M5 ;
        RECT  104.688 129.516 104.712 129.6 ;
    END
  END pd1[474]
  PIN pd1[475]
    DIRECTION OUTPUT ;
    USE SIGNAL ;
    PORT
      LAYER M5 ;
        RECT  104.784 129.516 104.808 129.6 ;
    END
  END pd1[475]
  PIN pd1[476]
    DIRECTION OUTPUT ;
    USE SIGNAL ;
    PORT
      LAYER M5 ;
        RECT  104.88 129.516 104.904 129.6 ;
    END
  END pd1[476]
  PIN pd1[477]
    DIRECTION OUTPUT ;
    USE SIGNAL ;
    PORT
      LAYER M5 ;
        RECT  104.976 129.516 105 129.6 ;
    END
  END pd1[477]
  PIN pd1[478]
    DIRECTION OUTPUT ;
    USE SIGNAL ;
    PORT
      LAYER M5 ;
        RECT  105.072 129.516 105.096 129.6 ;
    END
  END pd1[478]
  PIN pd1[479]
    DIRECTION OUTPUT ;
    USE SIGNAL ;
    PORT
      LAYER M5 ;
        RECT  105.168 129.516 105.192 129.6 ;
    END
  END pd1[479]
  PIN pd1[47]
    DIRECTION OUTPUT ;
    USE SIGNAL ;
    PORT
      LAYER M5 ;
        RECT  78.288 129.516 78.312 129.6 ;
    END
  END pd1[47]
  PIN pd1[480]
    DIRECTION OUTPUT ;
    USE SIGNAL ;
    PORT
      LAYER M5 ;
        RECT  156.72 129.516 156.744 129.6 ;
    END
  END pd1[480]
  PIN pd1[481]
    DIRECTION OUTPUT ;
    USE SIGNAL ;
    PORT
      LAYER M5 ;
        RECT  156.816 129.516 156.84 129.6 ;
    END
  END pd1[481]
  PIN pd1[482]
    DIRECTION OUTPUT ;
    USE SIGNAL ;
    PORT
      LAYER M5 ;
        RECT  156.912 129.516 156.936 129.6 ;
    END
  END pd1[482]
  PIN pd1[483]
    DIRECTION OUTPUT ;
    USE SIGNAL ;
    PORT
      LAYER M5 ;
        RECT  157.008 129.516 157.032 129.6 ;
    END
  END pd1[483]
  PIN pd1[484]
    DIRECTION OUTPUT ;
    USE SIGNAL ;
    PORT
      LAYER M5 ;
        RECT  157.104 129.516 157.128 129.6 ;
    END
  END pd1[484]
  PIN pd1[485]
    DIRECTION OUTPUT ;
    USE SIGNAL ;
    PORT
      LAYER M5 ;
        RECT  157.2 129.516 157.224 129.6 ;
    END
  END pd1[485]
  PIN pd1[486]
    DIRECTION OUTPUT ;
    USE SIGNAL ;
    PORT
      LAYER M5 ;
        RECT  157.296 129.516 157.32 129.6 ;
    END
  END pd1[486]
  PIN pd1[487]
    DIRECTION OUTPUT ;
    USE SIGNAL ;
    PORT
      LAYER M5 ;
        RECT  157.392 129.516 157.416 129.6 ;
    END
  END pd1[487]
  PIN pd1[488]
    DIRECTION OUTPUT ;
    USE SIGNAL ;
    PORT
      LAYER M5 ;
        RECT  157.488 129.516 157.512 129.6 ;
    END
  END pd1[488]
  PIN pd1[489]
    DIRECTION OUTPUT ;
    USE SIGNAL ;
    PORT
      LAYER M5 ;
        RECT  157.584 129.516 157.608 129.6 ;
    END
  END pd1[489]
  PIN pd1[48]
    DIRECTION OUTPUT ;
    USE SIGNAL ;
    PORT
      LAYER M5 ;
        RECT  78.384 129.516 78.408 129.6 ;
    END
  END pd1[48]
  PIN pd1[490]
    DIRECTION OUTPUT ;
    USE SIGNAL ;
    PORT
      LAYER M5 ;
        RECT  157.68 129.516 157.704 129.6 ;
    END
  END pd1[490]
  PIN pd1[491]
    DIRECTION OUTPUT ;
    USE SIGNAL ;
    PORT
      LAYER M5 ;
        RECT  157.776 129.516 157.8 129.6 ;
    END
  END pd1[491]
  PIN pd1[492]
    DIRECTION OUTPUT ;
    USE SIGNAL ;
    PORT
      LAYER M5 ;
        RECT  157.872 129.516 157.896 129.6 ;
    END
  END pd1[492]
  PIN pd1[493]
    DIRECTION OUTPUT ;
    USE SIGNAL ;
    PORT
      LAYER M5 ;
        RECT  157.968 129.516 157.992 129.6 ;
    END
  END pd1[493]
  PIN pd1[494]
    DIRECTION OUTPUT ;
    USE SIGNAL ;
    PORT
      LAYER M5 ;
        RECT  158.064 129.516 158.088 129.6 ;
    END
  END pd1[494]
  PIN pd1[495]
    DIRECTION OUTPUT ;
    USE SIGNAL ;
    PORT
      LAYER M5 ;
        RECT  158.16 129.516 158.184 129.6 ;
    END
  END pd1[495]
  PIN pd1[496]
    DIRECTION OUTPUT ;
    USE SIGNAL ;
    PORT
      LAYER M5 ;
        RECT  158.256 129.516 158.28 129.6 ;
    END
  END pd1[496]
  PIN pd1[497]
    DIRECTION OUTPUT ;
    USE SIGNAL ;
    PORT
      LAYER M5 ;
        RECT  158.352 129.516 158.376 129.6 ;
    END
  END pd1[497]
  PIN pd1[498]
    DIRECTION OUTPUT ;
    USE SIGNAL ;
    PORT
      LAYER M5 ;
        RECT  158.448 129.516 158.472 129.6 ;
    END
  END pd1[498]
  PIN pd1[499]
    DIRECTION OUTPUT ;
    USE SIGNAL ;
    PORT
      LAYER M5 ;
        RECT  158.544 129.516 158.568 129.6 ;
    END
  END pd1[499]
  PIN pd1[49]
    DIRECTION OUTPUT ;
    USE SIGNAL ;
    PORT
      LAYER M5 ;
        RECT  78.48 129.516 78.504 129.6 ;
    END
  END pd1[49]
  PIN pd1[4]
    DIRECTION OUTPUT ;
    USE SIGNAL ;
    PORT
      LAYER M5 ;
        RECT  160.176 129.516 160.2 129.6 ;
    END
  END pd1[4]
  PIN pd1[500]
    DIRECTION OUTPUT ;
    USE SIGNAL ;
    PORT
      LAYER M5 ;
        RECT  158.64 129.516 158.664 129.6 ;
    END
  END pd1[500]
  PIN pd1[501]
    DIRECTION OUTPUT ;
    USE SIGNAL ;
    PORT
      LAYER M5 ;
        RECT  158.736 129.516 158.76 129.6 ;
    END
  END pd1[501]
  PIN pd1[502]
    DIRECTION OUTPUT ;
    USE SIGNAL ;
    PORT
      LAYER M5 ;
        RECT  158.832 129.516 158.856 129.6 ;
    END
  END pd1[502]
  PIN pd1[503]
    DIRECTION OUTPUT ;
    USE SIGNAL ;
    PORT
      LAYER M5 ;
        RECT  158.928 129.516 158.952 129.6 ;
    END
  END pd1[503]
  PIN pd1[504]
    DIRECTION OUTPUT ;
    USE SIGNAL ;
    PORT
      LAYER M5 ;
        RECT  159.024 129.516 159.048 129.6 ;
    END
  END pd1[504]
  PIN pd1[505]
    DIRECTION OUTPUT ;
    USE SIGNAL ;
    PORT
      LAYER M5 ;
        RECT  159.12 129.516 159.144 129.6 ;
    END
  END pd1[505]
  PIN pd1[506]
    DIRECTION OUTPUT ;
    USE SIGNAL ;
    PORT
      LAYER M5 ;
        RECT  159.216 129.516 159.24 129.6 ;
    END
  END pd1[506]
  PIN pd1[507]
    DIRECTION OUTPUT ;
    USE SIGNAL ;
    PORT
      LAYER M5 ;
        RECT  159.312 129.516 159.336 129.6 ;
    END
  END pd1[507]
  PIN pd1[508]
    DIRECTION OUTPUT ;
    USE SIGNAL ;
    PORT
      LAYER M5 ;
        RECT  159.408 129.516 159.432 129.6 ;
    END
  END pd1[508]
  PIN pd1[509]
    DIRECTION OUTPUT ;
    USE SIGNAL ;
    PORT
      LAYER M5 ;
        RECT  159.504 129.516 159.528 129.6 ;
    END
  END pd1[509]
  PIN pd1[50]
    DIRECTION OUTPUT ;
    USE SIGNAL ;
    PORT
      LAYER M5 ;
        RECT  78.576 129.516 78.6 129.6 ;
    END
  END pd1[50]
  PIN pd1[510]
    DIRECTION OUTPUT ;
    USE SIGNAL ;
    PORT
      LAYER M5 ;
        RECT  159.6 129.516 159.624 129.6 ;
    END
  END pd1[510]
  PIN pd1[511]
    DIRECTION OUTPUT ;
    USE SIGNAL ;
    PORT
      LAYER M5 ;
        RECT  159.696 129.516 159.72 129.6 ;
    END
  END pd1[511]
  PIN pd1[512]
    DIRECTION OUTPUT ;
    USE SIGNAL ;
    PORT
      LAYER M5 ;
        RECT  111.408 129.516 111.432 129.6 ;
    END
  END pd1[512]
  PIN pd1[513]
    DIRECTION OUTPUT ;
    USE SIGNAL ;
    PORT
      LAYER M5 ;
        RECT  111.504 129.516 111.528 129.6 ;
    END
  END pd1[513]
  PIN pd1[514]
    DIRECTION OUTPUT ;
    USE SIGNAL ;
    PORT
      LAYER M5 ;
        RECT  111.6 129.516 111.624 129.6 ;
    END
  END pd1[514]
  PIN pd1[515]
    DIRECTION OUTPUT ;
    USE SIGNAL ;
    PORT
      LAYER M5 ;
        RECT  111.696 129.516 111.72 129.6 ;
    END
  END pd1[515]
  PIN pd1[516]
    DIRECTION OUTPUT ;
    USE SIGNAL ;
    PORT
      LAYER M5 ;
        RECT  111.792 129.516 111.816 129.6 ;
    END
  END pd1[516]
  PIN pd1[517]
    DIRECTION OUTPUT ;
    USE SIGNAL ;
    PORT
      LAYER M5 ;
        RECT  111.888 129.516 111.912 129.6 ;
    END
  END pd1[517]
  PIN pd1[518]
    DIRECTION OUTPUT ;
    USE SIGNAL ;
    PORT
      LAYER M5 ;
        RECT  111.984 129.516 112.008 129.6 ;
    END
  END pd1[518]
  PIN pd1[519]
    DIRECTION OUTPUT ;
    USE SIGNAL ;
    PORT
      LAYER M5 ;
        RECT  112.08 129.516 112.104 129.6 ;
    END
  END pd1[519]
  PIN pd1[51]
    DIRECTION OUTPUT ;
    USE SIGNAL ;
    PORT
      LAYER M5 ;
        RECT  78.672 129.516 78.696 129.6 ;
    END
  END pd1[51]
  PIN pd1[520]
    DIRECTION OUTPUT ;
    USE SIGNAL ;
    PORT
      LAYER M5 ;
        RECT  112.176 129.516 112.2 129.6 ;
    END
  END pd1[520]
  PIN pd1[521]
    DIRECTION OUTPUT ;
    USE SIGNAL ;
    PORT
      LAYER M5 ;
        RECT  112.272 129.516 112.296 129.6 ;
    END
  END pd1[521]
  PIN pd1[522]
    DIRECTION OUTPUT ;
    USE SIGNAL ;
    PORT
      LAYER M5 ;
        RECT  112.368 129.516 112.392 129.6 ;
    END
  END pd1[522]
  PIN pd1[523]
    DIRECTION OUTPUT ;
    USE SIGNAL ;
    PORT
      LAYER M5 ;
        RECT  112.464 129.516 112.488 129.6 ;
    END
  END pd1[523]
  PIN pd1[524]
    DIRECTION OUTPUT ;
    USE SIGNAL ;
    PORT
      LAYER M5 ;
        RECT  112.56 129.516 112.584 129.6 ;
    END
  END pd1[524]
  PIN pd1[525]
    DIRECTION OUTPUT ;
    USE SIGNAL ;
    PORT
      LAYER M5 ;
        RECT  112.656 129.516 112.68 129.6 ;
    END
  END pd1[525]
  PIN pd1[526]
    DIRECTION OUTPUT ;
    USE SIGNAL ;
    PORT
      LAYER M5 ;
        RECT  112.752 129.516 112.776 129.6 ;
    END
  END pd1[526]
  PIN pd1[527]
    DIRECTION OUTPUT ;
    USE SIGNAL ;
    PORT
      LAYER M5 ;
        RECT  112.848 129.516 112.872 129.6 ;
    END
  END pd1[527]
  PIN pd1[528]
    DIRECTION OUTPUT ;
    USE SIGNAL ;
    PORT
      LAYER M5 ;
        RECT  112.944 129.516 112.968 129.6 ;
    END
  END pd1[528]
  PIN pd1[529]
    DIRECTION OUTPUT ;
    USE SIGNAL ;
    PORT
      LAYER M5 ;
        RECT  113.04 129.516 113.064 129.6 ;
    END
  END pd1[529]
  PIN pd1[52]
    DIRECTION OUTPUT ;
    USE SIGNAL ;
    PORT
      LAYER M5 ;
        RECT  78.768 129.516 78.792 129.6 ;
    END
  END pd1[52]
  PIN pd1[530]
    DIRECTION OUTPUT ;
    USE SIGNAL ;
    PORT
      LAYER M5 ;
        RECT  113.136 129.516 113.16 129.6 ;
    END
  END pd1[530]
  PIN pd1[531]
    DIRECTION OUTPUT ;
    USE SIGNAL ;
    PORT
      LAYER M5 ;
        RECT  113.232 129.516 113.256 129.6 ;
    END
  END pd1[531]
  PIN pd1[532]
    DIRECTION OUTPUT ;
    USE SIGNAL ;
    PORT
      LAYER M5 ;
        RECT  113.328 129.516 113.352 129.6 ;
    END
  END pd1[532]
  PIN pd1[533]
    DIRECTION OUTPUT ;
    USE SIGNAL ;
    PORT
      LAYER M5 ;
        RECT  113.424 129.516 113.448 129.6 ;
    END
  END pd1[533]
  PIN pd1[534]
    DIRECTION OUTPUT ;
    USE SIGNAL ;
    PORT
      LAYER M5 ;
        RECT  113.52 129.516 113.544 129.6 ;
    END
  END pd1[534]
  PIN pd1[535]
    DIRECTION OUTPUT ;
    USE SIGNAL ;
    PORT
      LAYER M5 ;
        RECT  113.616 129.516 113.64 129.6 ;
    END
  END pd1[535]
  PIN pd1[536]
    DIRECTION OUTPUT ;
    USE SIGNAL ;
    PORT
      LAYER M5 ;
        RECT  113.712 129.516 113.736 129.6 ;
    END
  END pd1[536]
  PIN pd1[537]
    DIRECTION OUTPUT ;
    USE SIGNAL ;
    PORT
      LAYER M5 ;
        RECT  113.808 129.516 113.832 129.6 ;
    END
  END pd1[537]
  PIN pd1[538]
    DIRECTION OUTPUT ;
    USE SIGNAL ;
    PORT
      LAYER M5 ;
        RECT  113.904 129.516 113.928 129.6 ;
    END
  END pd1[538]
  PIN pd1[539]
    DIRECTION OUTPUT ;
    USE SIGNAL ;
    PORT
      LAYER M5 ;
        RECT  114 129.516 114.024 129.6 ;
    END
  END pd1[539]
  PIN pd1[53]
    DIRECTION OUTPUT ;
    USE SIGNAL ;
    PORT
      LAYER M5 ;
        RECT  78.864 129.516 78.888 129.6 ;
    END
  END pd1[53]
  PIN pd1[540]
    DIRECTION OUTPUT ;
    USE SIGNAL ;
    PORT
      LAYER M5 ;
        RECT  114.096 129.516 114.12 129.6 ;
    END
  END pd1[540]
  PIN pd1[541]
    DIRECTION OUTPUT ;
    USE SIGNAL ;
    PORT
      LAYER M5 ;
        RECT  114.192 129.516 114.216 129.6 ;
    END
  END pd1[541]
  PIN pd1[542]
    DIRECTION OUTPUT ;
    USE SIGNAL ;
    PORT
      LAYER M5 ;
        RECT  114.288 129.516 114.312 129.6 ;
    END
  END pd1[542]
  PIN pd1[543]
    DIRECTION OUTPUT ;
    USE SIGNAL ;
    PORT
      LAYER M5 ;
        RECT  114.384 129.516 114.408 129.6 ;
    END
  END pd1[543]
  PIN pd1[544]
    DIRECTION OUTPUT ;
    USE SIGNAL ;
    PORT
      LAYER M5 ;
        RECT  108.336 129.516 108.36 129.6 ;
    END
  END pd1[544]
  PIN pd1[545]
    DIRECTION OUTPUT ;
    USE SIGNAL ;
    PORT
      LAYER M5 ;
        RECT  108.432 129.516 108.456 129.6 ;
    END
  END pd1[545]
  PIN pd1[546]
    DIRECTION OUTPUT ;
    USE SIGNAL ;
    PORT
      LAYER M5 ;
        RECT  108.528 129.516 108.552 129.6 ;
    END
  END pd1[546]
  PIN pd1[547]
    DIRECTION OUTPUT ;
    USE SIGNAL ;
    PORT
      LAYER M5 ;
        RECT  108.624 129.516 108.648 129.6 ;
    END
  END pd1[547]
  PIN pd1[548]
    DIRECTION OUTPUT ;
    USE SIGNAL ;
    PORT
      LAYER M5 ;
        RECT  108.72 129.516 108.744 129.6 ;
    END
  END pd1[548]
  PIN pd1[549]
    DIRECTION OUTPUT ;
    USE SIGNAL ;
    PORT
      LAYER M5 ;
        RECT  108.816 129.516 108.84 129.6 ;
    END
  END pd1[549]
  PIN pd1[54]
    DIRECTION OUTPUT ;
    USE SIGNAL ;
    PORT
      LAYER M5 ;
        RECT  78.96 129.516 78.984 129.6 ;
    END
  END pd1[54]
  PIN pd1[550]
    DIRECTION OUTPUT ;
    USE SIGNAL ;
    PORT
      LAYER M5 ;
        RECT  108.912 129.516 108.936 129.6 ;
    END
  END pd1[550]
  PIN pd1[551]
    DIRECTION OUTPUT ;
    USE SIGNAL ;
    PORT
      LAYER M5 ;
        RECT  109.008 129.516 109.032 129.6 ;
    END
  END pd1[551]
  PIN pd1[552]
    DIRECTION OUTPUT ;
    USE SIGNAL ;
    PORT
      LAYER M5 ;
        RECT  109.104 129.516 109.128 129.6 ;
    END
  END pd1[552]
  PIN pd1[553]
    DIRECTION OUTPUT ;
    USE SIGNAL ;
    PORT
      LAYER M5 ;
        RECT  109.2 129.516 109.224 129.6 ;
    END
  END pd1[553]
  PIN pd1[554]
    DIRECTION OUTPUT ;
    USE SIGNAL ;
    PORT
      LAYER M5 ;
        RECT  109.296 129.516 109.32 129.6 ;
    END
  END pd1[554]
  PIN pd1[555]
    DIRECTION OUTPUT ;
    USE SIGNAL ;
    PORT
      LAYER M5 ;
        RECT  109.392 129.516 109.416 129.6 ;
    END
  END pd1[555]
  PIN pd1[556]
    DIRECTION OUTPUT ;
    USE SIGNAL ;
    PORT
      LAYER M5 ;
        RECT  109.488 129.516 109.512 129.6 ;
    END
  END pd1[556]
  PIN pd1[557]
    DIRECTION OUTPUT ;
    USE SIGNAL ;
    PORT
      LAYER M5 ;
        RECT  109.584 129.516 109.608 129.6 ;
    END
  END pd1[557]
  PIN pd1[558]
    DIRECTION OUTPUT ;
    USE SIGNAL ;
    PORT
      LAYER M5 ;
        RECT  109.68 129.516 109.704 129.6 ;
    END
  END pd1[558]
  PIN pd1[559]
    DIRECTION OUTPUT ;
    USE SIGNAL ;
    PORT
      LAYER M5 ;
        RECT  109.776 129.516 109.8 129.6 ;
    END
  END pd1[559]
  PIN pd1[55]
    DIRECTION OUTPUT ;
    USE SIGNAL ;
    PORT
      LAYER M5 ;
        RECT  79.056 129.516 79.08 129.6 ;
    END
  END pd1[55]
  PIN pd1[560]
    DIRECTION OUTPUT ;
    USE SIGNAL ;
    PORT
      LAYER M5 ;
        RECT  109.872 129.516 109.896 129.6 ;
    END
  END pd1[560]
  PIN pd1[561]
    DIRECTION OUTPUT ;
    USE SIGNAL ;
    PORT
      LAYER M5 ;
        RECT  109.968 129.516 109.992 129.6 ;
    END
  END pd1[561]
  PIN pd1[562]
    DIRECTION OUTPUT ;
    USE SIGNAL ;
    PORT
      LAYER M5 ;
        RECT  110.064 129.516 110.088 129.6 ;
    END
  END pd1[562]
  PIN pd1[563]
    DIRECTION OUTPUT ;
    USE SIGNAL ;
    PORT
      LAYER M5 ;
        RECT  110.16 129.516 110.184 129.6 ;
    END
  END pd1[563]
  PIN pd1[564]
    DIRECTION OUTPUT ;
    USE SIGNAL ;
    PORT
      LAYER M5 ;
        RECT  110.256 129.516 110.28 129.6 ;
    END
  END pd1[564]
  PIN pd1[565]
    DIRECTION OUTPUT ;
    USE SIGNAL ;
    PORT
      LAYER M5 ;
        RECT  110.352 129.516 110.376 129.6 ;
    END
  END pd1[565]
  PIN pd1[566]
    DIRECTION OUTPUT ;
    USE SIGNAL ;
    PORT
      LAYER M5 ;
        RECT  110.448 129.516 110.472 129.6 ;
    END
  END pd1[566]
  PIN pd1[567]
    DIRECTION OUTPUT ;
    USE SIGNAL ;
    PORT
      LAYER M5 ;
        RECT  110.544 129.516 110.568 129.6 ;
    END
  END pd1[567]
  PIN pd1[568]
    DIRECTION OUTPUT ;
    USE SIGNAL ;
    PORT
      LAYER M5 ;
        RECT  110.64 129.516 110.664 129.6 ;
    END
  END pd1[568]
  PIN pd1[569]
    DIRECTION OUTPUT ;
    USE SIGNAL ;
    PORT
      LAYER M5 ;
        RECT  110.736 129.516 110.76 129.6 ;
    END
  END pd1[569]
  PIN pd1[56]
    DIRECTION OUTPUT ;
    USE SIGNAL ;
    PORT
      LAYER M5 ;
        RECT  79.152 129.516 79.176 129.6 ;
    END
  END pd1[56]
  PIN pd1[570]
    DIRECTION OUTPUT ;
    USE SIGNAL ;
    PORT
      LAYER M5 ;
        RECT  110.832 129.516 110.856 129.6 ;
    END
  END pd1[570]
  PIN pd1[571]
    DIRECTION OUTPUT ;
    USE SIGNAL ;
    PORT
      LAYER M5 ;
        RECT  110.928 129.516 110.952 129.6 ;
    END
  END pd1[571]
  PIN pd1[572]
    DIRECTION OUTPUT ;
    USE SIGNAL ;
    PORT
      LAYER M5 ;
        RECT  111.024 129.516 111.048 129.6 ;
    END
  END pd1[572]
  PIN pd1[573]
    DIRECTION OUTPUT ;
    USE SIGNAL ;
    PORT
      LAYER M5 ;
        RECT  111.12 129.516 111.144 129.6 ;
    END
  END pd1[573]
  PIN pd1[574]
    DIRECTION OUTPUT ;
    USE SIGNAL ;
    PORT
      LAYER M5 ;
        RECT  111.216 129.516 111.24 129.6 ;
    END
  END pd1[574]
  PIN pd1[575]
    DIRECTION OUTPUT ;
    USE SIGNAL ;
    PORT
      LAYER M5 ;
        RECT  111.312 129.516 111.336 129.6 ;
    END
  END pd1[575]
  PIN pd1[576]
    DIRECTION OUTPUT ;
    USE SIGNAL ;
    PORT
      LAYER M5 ;
        RECT  137.52 129.516 137.544 129.6 ;
    END
  END pd1[576]
  PIN pd1[577]
    DIRECTION OUTPUT ;
    USE SIGNAL ;
    PORT
      LAYER M5 ;
        RECT  137.616 129.516 137.64 129.6 ;
    END
  END pd1[577]
  PIN pd1[578]
    DIRECTION OUTPUT ;
    USE SIGNAL ;
    PORT
      LAYER M5 ;
        RECT  137.712 129.516 137.736 129.6 ;
    END
  END pd1[578]
  PIN pd1[579]
    DIRECTION OUTPUT ;
    USE SIGNAL ;
    PORT
      LAYER M5 ;
        RECT  137.808 129.516 137.832 129.6 ;
    END
  END pd1[579]
  PIN pd1[57]
    DIRECTION OUTPUT ;
    USE SIGNAL ;
    PORT
      LAYER M5 ;
        RECT  79.248 129.516 79.272 129.6 ;
    END
  END pd1[57]
  PIN pd1[580]
    DIRECTION OUTPUT ;
    USE SIGNAL ;
    PORT
      LAYER M5 ;
        RECT  137.904 129.516 137.928 129.6 ;
    END
  END pd1[580]
  PIN pd1[581]
    DIRECTION OUTPUT ;
    USE SIGNAL ;
    PORT
      LAYER M5 ;
        RECT  138 129.516 138.024 129.6 ;
    END
  END pd1[581]
  PIN pd1[582]
    DIRECTION OUTPUT ;
    USE SIGNAL ;
    PORT
      LAYER M5 ;
        RECT  138.096 129.516 138.12 129.6 ;
    END
  END pd1[582]
  PIN pd1[583]
    DIRECTION OUTPUT ;
    USE SIGNAL ;
    PORT
      LAYER M5 ;
        RECT  138.192 129.516 138.216 129.6 ;
    END
  END pd1[583]
  PIN pd1[584]
    DIRECTION OUTPUT ;
    USE SIGNAL ;
    PORT
      LAYER M5 ;
        RECT  138.288 129.516 138.312 129.6 ;
    END
  END pd1[584]
  PIN pd1[585]
    DIRECTION OUTPUT ;
    USE SIGNAL ;
    PORT
      LAYER M5 ;
        RECT  138.384 129.516 138.408 129.6 ;
    END
  END pd1[585]
  PIN pd1[586]
    DIRECTION OUTPUT ;
    USE SIGNAL ;
    PORT
      LAYER M5 ;
        RECT  138.48 129.516 138.504 129.6 ;
    END
  END pd1[586]
  PIN pd1[587]
    DIRECTION OUTPUT ;
    USE SIGNAL ;
    PORT
      LAYER M5 ;
        RECT  138.576 129.516 138.6 129.6 ;
    END
  END pd1[587]
  PIN pd1[588]
    DIRECTION OUTPUT ;
    USE SIGNAL ;
    PORT
      LAYER M5 ;
        RECT  138.672 129.516 138.696 129.6 ;
    END
  END pd1[588]
  PIN pd1[589]
    DIRECTION OUTPUT ;
    USE SIGNAL ;
    PORT
      LAYER M5 ;
        RECT  138.768 129.516 138.792 129.6 ;
    END
  END pd1[589]
  PIN pd1[58]
    DIRECTION OUTPUT ;
    USE SIGNAL ;
    PORT
      LAYER M5 ;
        RECT  79.344 129.516 79.368 129.6 ;
    END
  END pd1[58]
  PIN pd1[590]
    DIRECTION OUTPUT ;
    USE SIGNAL ;
    PORT
      LAYER M5 ;
        RECT  138.864 129.516 138.888 129.6 ;
    END
  END pd1[590]
  PIN pd1[591]
    DIRECTION OUTPUT ;
    USE SIGNAL ;
    PORT
      LAYER M5 ;
        RECT  138.96 129.516 138.984 129.6 ;
    END
  END pd1[591]
  PIN pd1[592]
    DIRECTION OUTPUT ;
    USE SIGNAL ;
    PORT
      LAYER M5 ;
        RECT  139.056 129.516 139.08 129.6 ;
    END
  END pd1[592]
  PIN pd1[593]
    DIRECTION OUTPUT ;
    USE SIGNAL ;
    PORT
      LAYER M5 ;
        RECT  139.152 129.516 139.176 129.6 ;
    END
  END pd1[593]
  PIN pd1[594]
    DIRECTION OUTPUT ;
    USE SIGNAL ;
    PORT
      LAYER M5 ;
        RECT  139.248 129.516 139.272 129.6 ;
    END
  END pd1[594]
  PIN pd1[595]
    DIRECTION OUTPUT ;
    USE SIGNAL ;
    PORT
      LAYER M5 ;
        RECT  139.344 129.516 139.368 129.6 ;
    END
  END pd1[595]
  PIN pd1[596]
    DIRECTION OUTPUT ;
    USE SIGNAL ;
    PORT
      LAYER M5 ;
        RECT  139.44 129.516 139.464 129.6 ;
    END
  END pd1[596]
  PIN pd1[597]
    DIRECTION OUTPUT ;
    USE SIGNAL ;
    PORT
      LAYER M5 ;
        RECT  139.536 129.516 139.56 129.6 ;
    END
  END pd1[597]
  PIN pd1[598]
    DIRECTION OUTPUT ;
    USE SIGNAL ;
    PORT
      LAYER M5 ;
        RECT  139.632 129.516 139.656 129.6 ;
    END
  END pd1[598]
  PIN pd1[599]
    DIRECTION OUTPUT ;
    USE SIGNAL ;
    PORT
      LAYER M5 ;
        RECT  139.728 129.516 139.752 129.6 ;
    END
  END pd1[599]
  PIN pd1[59]
    DIRECTION OUTPUT ;
    USE SIGNAL ;
    PORT
      LAYER M5 ;
        RECT  79.44 129.516 79.464 129.6 ;
    END
  END pd1[59]
  PIN pd1[5]
    DIRECTION OUTPUT ;
    USE SIGNAL ;
    PORT
      LAYER M5 ;
        RECT  160.272 129.516 160.296 129.6 ;
    END
  END pd1[5]
  PIN pd1[600]
    DIRECTION OUTPUT ;
    USE SIGNAL ;
    PORT
      LAYER M5 ;
        RECT  139.824 129.516 139.848 129.6 ;
    END
  END pd1[600]
  PIN pd1[601]
    DIRECTION OUTPUT ;
    USE SIGNAL ;
    PORT
      LAYER M5 ;
        RECT  139.92 129.516 139.944 129.6 ;
    END
  END pd1[601]
  PIN pd1[602]
    DIRECTION OUTPUT ;
    USE SIGNAL ;
    PORT
      LAYER M5 ;
        RECT  140.016 129.516 140.04 129.6 ;
    END
  END pd1[602]
  PIN pd1[603]
    DIRECTION OUTPUT ;
    USE SIGNAL ;
    PORT
      LAYER M5 ;
        RECT  140.112 129.516 140.136 129.6 ;
    END
  END pd1[603]
  PIN pd1[604]
    DIRECTION OUTPUT ;
    USE SIGNAL ;
    PORT
      LAYER M5 ;
        RECT  140.208 129.516 140.232 129.6 ;
    END
  END pd1[604]
  PIN pd1[605]
    DIRECTION OUTPUT ;
    USE SIGNAL ;
    PORT
      LAYER M5 ;
        RECT  140.304 129.516 140.328 129.6 ;
    END
  END pd1[605]
  PIN pd1[606]
    DIRECTION OUTPUT ;
    USE SIGNAL ;
    PORT
      LAYER M5 ;
        RECT  140.4 129.516 140.424 129.6 ;
    END
  END pd1[606]
  PIN pd1[607]
    DIRECTION OUTPUT ;
    USE SIGNAL ;
    PORT
      LAYER M5 ;
        RECT  140.496 129.516 140.52 129.6 ;
    END
  END pd1[607]
  PIN pd1[608]
    DIRECTION OUTPUT ;
    USE SIGNAL ;
    PORT
      LAYER M5 ;
        RECT  82.992 129.516 83.016 129.6 ;
    END
  END pd1[608]
  PIN pd1[609]
    DIRECTION OUTPUT ;
    USE SIGNAL ;
    PORT
      LAYER M5 ;
        RECT  83.088 129.516 83.112 129.6 ;
    END
  END pd1[609]
  PIN pd1[60]
    DIRECTION OUTPUT ;
    USE SIGNAL ;
    PORT
      LAYER M5 ;
        RECT  79.536 129.516 79.56 129.6 ;
    END
  END pd1[60]
  PIN pd1[610]
    DIRECTION OUTPUT ;
    USE SIGNAL ;
    PORT
      LAYER M5 ;
        RECT  83.184 129.516 83.208 129.6 ;
    END
  END pd1[610]
  PIN pd1[611]
    DIRECTION OUTPUT ;
    USE SIGNAL ;
    PORT
      LAYER M5 ;
        RECT  83.28 129.516 83.304 129.6 ;
    END
  END pd1[611]
  PIN pd1[612]
    DIRECTION OUTPUT ;
    USE SIGNAL ;
    PORT
      LAYER M5 ;
        RECT  83.376 129.516 83.4 129.6 ;
    END
  END pd1[612]
  PIN pd1[613]
    DIRECTION OUTPUT ;
    USE SIGNAL ;
    PORT
      LAYER M5 ;
        RECT  83.472 129.516 83.496 129.6 ;
    END
  END pd1[613]
  PIN pd1[614]
    DIRECTION OUTPUT ;
    USE SIGNAL ;
    PORT
      LAYER M5 ;
        RECT  83.568 129.516 83.592 129.6 ;
    END
  END pd1[614]
  PIN pd1[615]
    DIRECTION OUTPUT ;
    USE SIGNAL ;
    PORT
      LAYER M5 ;
        RECT  83.664 129.516 83.688 129.6 ;
    END
  END pd1[615]
  PIN pd1[616]
    DIRECTION OUTPUT ;
    USE SIGNAL ;
    PORT
      LAYER M5 ;
        RECT  83.76 129.516 83.784 129.6 ;
    END
  END pd1[616]
  PIN pd1[617]
    DIRECTION OUTPUT ;
    USE SIGNAL ;
    PORT
      LAYER M5 ;
        RECT  83.856 129.516 83.88 129.6 ;
    END
  END pd1[617]
  PIN pd1[618]
    DIRECTION OUTPUT ;
    USE SIGNAL ;
    PORT
      LAYER M5 ;
        RECT  83.952 129.516 83.976 129.6 ;
    END
  END pd1[618]
  PIN pd1[619]
    DIRECTION OUTPUT ;
    USE SIGNAL ;
    PORT
      LAYER M5 ;
        RECT  84.048 129.516 84.072 129.6 ;
    END
  END pd1[619]
  PIN pd1[61]
    DIRECTION OUTPUT ;
    USE SIGNAL ;
    PORT
      LAYER M5 ;
        RECT  79.632 129.516 79.656 129.6 ;
    END
  END pd1[61]
  PIN pd1[620]
    DIRECTION OUTPUT ;
    USE SIGNAL ;
    PORT
      LAYER M5 ;
        RECT  84.144 129.516 84.168 129.6 ;
    END
  END pd1[620]
  PIN pd1[621]
    DIRECTION OUTPUT ;
    USE SIGNAL ;
    PORT
      LAYER M5 ;
        RECT  84.24 129.516 84.264 129.6 ;
    END
  END pd1[621]
  PIN pd1[622]
    DIRECTION OUTPUT ;
    USE SIGNAL ;
    PORT
      LAYER M5 ;
        RECT  84.336 129.516 84.36 129.6 ;
    END
  END pd1[622]
  PIN pd1[623]
    DIRECTION OUTPUT ;
    USE SIGNAL ;
    PORT
      LAYER M5 ;
        RECT  84.432 129.516 84.456 129.6 ;
    END
  END pd1[623]
  PIN pd1[624]
    DIRECTION OUTPUT ;
    USE SIGNAL ;
    PORT
      LAYER M5 ;
        RECT  84.528 129.516 84.552 129.6 ;
    END
  END pd1[624]
  PIN pd1[625]
    DIRECTION OUTPUT ;
    USE SIGNAL ;
    PORT
      LAYER M5 ;
        RECT  84.624 129.516 84.648 129.6 ;
    END
  END pd1[625]
  PIN pd1[626]
    DIRECTION OUTPUT ;
    USE SIGNAL ;
    PORT
      LAYER M5 ;
        RECT  84.72 129.516 84.744 129.6 ;
    END
  END pd1[626]
  PIN pd1[627]
    DIRECTION OUTPUT ;
    USE SIGNAL ;
    PORT
      LAYER M5 ;
        RECT  84.816 129.516 84.84 129.6 ;
    END
  END pd1[627]
  PIN pd1[628]
    DIRECTION OUTPUT ;
    USE SIGNAL ;
    PORT
      LAYER M5 ;
        RECT  84.912 129.516 84.936 129.6 ;
    END
  END pd1[628]
  PIN pd1[629]
    DIRECTION OUTPUT ;
    USE SIGNAL ;
    PORT
      LAYER M5 ;
        RECT  85.008 129.516 85.032 129.6 ;
    END
  END pd1[629]
  PIN pd1[62]
    DIRECTION OUTPUT ;
    USE SIGNAL ;
    PORT
      LAYER M5 ;
        RECT  79.728 129.516 79.752 129.6 ;
    END
  END pd1[62]
  PIN pd1[630]
    DIRECTION OUTPUT ;
    USE SIGNAL ;
    PORT
      LAYER M5 ;
        RECT  85.104 129.516 85.128 129.6 ;
    END
  END pd1[630]
  PIN pd1[631]
    DIRECTION OUTPUT ;
    USE SIGNAL ;
    PORT
      LAYER M5 ;
        RECT  85.2 129.516 85.224 129.6 ;
    END
  END pd1[631]
  PIN pd1[632]
    DIRECTION OUTPUT ;
    USE SIGNAL ;
    PORT
      LAYER M5 ;
        RECT  85.296 129.516 85.32 129.6 ;
    END
  END pd1[632]
  PIN pd1[633]
    DIRECTION OUTPUT ;
    USE SIGNAL ;
    PORT
      LAYER M5 ;
        RECT  85.392 129.516 85.416 129.6 ;
    END
  END pd1[633]
  PIN pd1[634]
    DIRECTION OUTPUT ;
    USE SIGNAL ;
    PORT
      LAYER M5 ;
        RECT  85.488 129.516 85.512 129.6 ;
    END
  END pd1[634]
  PIN pd1[635]
    DIRECTION OUTPUT ;
    USE SIGNAL ;
    PORT
      LAYER M5 ;
        RECT  85.584 129.516 85.608 129.6 ;
    END
  END pd1[635]
  PIN pd1[636]
    DIRECTION OUTPUT ;
    USE SIGNAL ;
    PORT
      LAYER M5 ;
        RECT  85.68 129.516 85.704 129.6 ;
    END
  END pd1[636]
  PIN pd1[637]
    DIRECTION OUTPUT ;
    USE SIGNAL ;
    PORT
      LAYER M5 ;
        RECT  85.776 129.516 85.8 129.6 ;
    END
  END pd1[637]
  PIN pd1[638]
    DIRECTION OUTPUT ;
    USE SIGNAL ;
    PORT
      LAYER M5 ;
        RECT  85.872 129.516 85.896 129.6 ;
    END
  END pd1[638]
  PIN pd1[639]
    DIRECTION OUTPUT ;
    USE SIGNAL ;
    PORT
      LAYER M5 ;
        RECT  85.968 129.516 85.992 129.6 ;
    END
  END pd1[639]
  PIN pd1[63]
    DIRECTION OUTPUT ;
    USE SIGNAL ;
    PORT
      LAYER M5 ;
        RECT  79.824 129.516 79.848 129.6 ;
    END
  END pd1[63]
  PIN pd1[640]
    DIRECTION OUTPUT ;
    USE SIGNAL ;
    PORT
      LAYER M5 ;
        RECT  60.72 129.516 60.744 129.6 ;
    END
  END pd1[640]
  PIN pd1[641]
    DIRECTION OUTPUT ;
    USE SIGNAL ;
    PORT
      LAYER M5 ;
        RECT  60.816 129.516 60.84 129.6 ;
    END
  END pd1[641]
  PIN pd1[642]
    DIRECTION OUTPUT ;
    USE SIGNAL ;
    PORT
      LAYER M5 ;
        RECT  60.912 129.516 60.936 129.6 ;
    END
  END pd1[642]
  PIN pd1[643]
    DIRECTION OUTPUT ;
    USE SIGNAL ;
    PORT
      LAYER M5 ;
        RECT  61.008 129.516 61.032 129.6 ;
    END
  END pd1[643]
  PIN pd1[644]
    DIRECTION OUTPUT ;
    USE SIGNAL ;
    PORT
      LAYER M5 ;
        RECT  61.104 129.516 61.128 129.6 ;
    END
  END pd1[644]
  PIN pd1[645]
    DIRECTION OUTPUT ;
    USE SIGNAL ;
    PORT
      LAYER M5 ;
        RECT  61.2 129.516 61.224 129.6 ;
    END
  END pd1[645]
  PIN pd1[646]
    DIRECTION OUTPUT ;
    USE SIGNAL ;
    PORT
      LAYER M5 ;
        RECT  61.296 129.516 61.32 129.6 ;
    END
  END pd1[646]
  PIN pd1[647]
    DIRECTION OUTPUT ;
    USE SIGNAL ;
    PORT
      LAYER M5 ;
        RECT  61.392 129.516 61.416 129.6 ;
    END
  END pd1[647]
  PIN pd1[648]
    DIRECTION OUTPUT ;
    USE SIGNAL ;
    PORT
      LAYER M5 ;
        RECT  61.488 129.516 61.512 129.6 ;
    END
  END pd1[648]
  PIN pd1[649]
    DIRECTION OUTPUT ;
    USE SIGNAL ;
    PORT
      LAYER M5 ;
        RECT  61.584 129.516 61.608 129.6 ;
    END
  END pd1[649]
  PIN pd1[64]
    DIRECTION OUTPUT ;
    USE SIGNAL ;
    PORT
      LAYER M5 ;
        RECT  105.264 129.516 105.288 129.6 ;
    END
  END pd1[64]
  PIN pd1[650]
    DIRECTION OUTPUT ;
    USE SIGNAL ;
    PORT
      LAYER M5 ;
        RECT  61.68 129.516 61.704 129.6 ;
    END
  END pd1[650]
  PIN pd1[651]
    DIRECTION OUTPUT ;
    USE SIGNAL ;
    PORT
      LAYER M5 ;
        RECT  61.776 129.516 61.8 129.6 ;
    END
  END pd1[651]
  PIN pd1[652]
    DIRECTION OUTPUT ;
    USE SIGNAL ;
    PORT
      LAYER M5 ;
        RECT  61.872 129.516 61.896 129.6 ;
    END
  END pd1[652]
  PIN pd1[653]
    DIRECTION OUTPUT ;
    USE SIGNAL ;
    PORT
      LAYER M5 ;
        RECT  61.968 129.516 61.992 129.6 ;
    END
  END pd1[653]
  PIN pd1[654]
    DIRECTION OUTPUT ;
    USE SIGNAL ;
    PORT
      LAYER M5 ;
        RECT  62.064 129.516 62.088 129.6 ;
    END
  END pd1[654]
  PIN pd1[655]
    DIRECTION OUTPUT ;
    USE SIGNAL ;
    PORT
      LAYER M5 ;
        RECT  62.16 129.516 62.184 129.6 ;
    END
  END pd1[655]
  PIN pd1[656]
    DIRECTION OUTPUT ;
    USE SIGNAL ;
    PORT
      LAYER M5 ;
        RECT  62.256 129.516 62.28 129.6 ;
    END
  END pd1[656]
  PIN pd1[657]
    DIRECTION OUTPUT ;
    USE SIGNAL ;
    PORT
      LAYER M5 ;
        RECT  62.352 129.516 62.376 129.6 ;
    END
  END pd1[657]
  PIN pd1[658]
    DIRECTION OUTPUT ;
    USE SIGNAL ;
    PORT
      LAYER M5 ;
        RECT  62.448 129.516 62.472 129.6 ;
    END
  END pd1[658]
  PIN pd1[659]
    DIRECTION OUTPUT ;
    USE SIGNAL ;
    PORT
      LAYER M5 ;
        RECT  62.544 129.516 62.568 129.6 ;
    END
  END pd1[659]
  PIN pd1[65]
    DIRECTION OUTPUT ;
    USE SIGNAL ;
    PORT
      LAYER M5 ;
        RECT  105.36 129.516 105.384 129.6 ;
    END
  END pd1[65]
  PIN pd1[660]
    DIRECTION OUTPUT ;
    USE SIGNAL ;
    PORT
      LAYER M5 ;
        RECT  62.64 129.516 62.664 129.6 ;
    END
  END pd1[660]
  PIN pd1[661]
    DIRECTION OUTPUT ;
    USE SIGNAL ;
    PORT
      LAYER M5 ;
        RECT  62.736 129.516 62.76 129.6 ;
    END
  END pd1[661]
  PIN pd1[662]
    DIRECTION OUTPUT ;
    USE SIGNAL ;
    PORT
      LAYER M5 ;
        RECT  62.832 129.516 62.856 129.6 ;
    END
  END pd1[662]
  PIN pd1[663]
    DIRECTION OUTPUT ;
    USE SIGNAL ;
    PORT
      LAYER M5 ;
        RECT  62.928 129.516 62.952 129.6 ;
    END
  END pd1[663]
  PIN pd1[664]
    DIRECTION OUTPUT ;
    USE SIGNAL ;
    PORT
      LAYER M5 ;
        RECT  63.024 129.516 63.048 129.6 ;
    END
  END pd1[664]
  PIN pd1[665]
    DIRECTION OUTPUT ;
    USE SIGNAL ;
    PORT
      LAYER M5 ;
        RECT  63.12 129.516 63.144 129.6 ;
    END
  END pd1[665]
  PIN pd1[666]
    DIRECTION OUTPUT ;
    USE SIGNAL ;
    PORT
      LAYER M5 ;
        RECT  63.216 129.516 63.24 129.6 ;
    END
  END pd1[666]
  PIN pd1[667]
    DIRECTION OUTPUT ;
    USE SIGNAL ;
    PORT
      LAYER M5 ;
        RECT  63.312 129.516 63.336 129.6 ;
    END
  END pd1[667]
  PIN pd1[668]
    DIRECTION OUTPUT ;
    USE SIGNAL ;
    PORT
      LAYER M5 ;
        RECT  63.408 129.516 63.432 129.6 ;
    END
  END pd1[668]
  PIN pd1[669]
    DIRECTION OUTPUT ;
    USE SIGNAL ;
    PORT
      LAYER M5 ;
        RECT  63.504 129.516 63.528 129.6 ;
    END
  END pd1[669]
  PIN pd1[66]
    DIRECTION OUTPUT ;
    USE SIGNAL ;
    PORT
      LAYER M5 ;
        RECT  105.456 129.516 105.48 129.6 ;
    END
  END pd1[66]
  PIN pd1[670]
    DIRECTION OUTPUT ;
    USE SIGNAL ;
    PORT
      LAYER M5 ;
        RECT  63.6 129.516 63.624 129.6 ;
    END
  END pd1[670]
  PIN pd1[671]
    DIRECTION OUTPUT ;
    USE SIGNAL ;
    PORT
      LAYER M5 ;
        RECT  63.696 129.516 63.72 129.6 ;
    END
  END pd1[671]
  PIN pd1[672]
    DIRECTION OUTPUT ;
    USE SIGNAL ;
    PORT
      LAYER M5 ;
        RECT  118.32 129.516 118.344 129.6 ;
    END
  END pd1[672]
  PIN pd1[673]
    DIRECTION OUTPUT ;
    USE SIGNAL ;
    PORT
      LAYER M5 ;
        RECT  118.416 129.516 118.44 129.6 ;
    END
  END pd1[673]
  PIN pd1[674]
    DIRECTION OUTPUT ;
    USE SIGNAL ;
    PORT
      LAYER M5 ;
        RECT  118.512 129.516 118.536 129.6 ;
    END
  END pd1[674]
  PIN pd1[675]
    DIRECTION OUTPUT ;
    USE SIGNAL ;
    PORT
      LAYER M5 ;
        RECT  118.608 129.516 118.632 129.6 ;
    END
  END pd1[675]
  PIN pd1[676]
    DIRECTION OUTPUT ;
    USE SIGNAL ;
    PORT
      LAYER M5 ;
        RECT  118.704 129.516 118.728 129.6 ;
    END
  END pd1[676]
  PIN pd1[677]
    DIRECTION OUTPUT ;
    USE SIGNAL ;
    PORT
      LAYER M5 ;
        RECT  118.8 129.516 118.824 129.6 ;
    END
  END pd1[677]
  PIN pd1[678]
    DIRECTION OUTPUT ;
    USE SIGNAL ;
    PORT
      LAYER M5 ;
        RECT  118.896 129.516 118.92 129.6 ;
    END
  END pd1[678]
  PIN pd1[679]
    DIRECTION OUTPUT ;
    USE SIGNAL ;
    PORT
      LAYER M5 ;
        RECT  118.992 129.516 119.016 129.6 ;
    END
  END pd1[679]
  PIN pd1[67]
    DIRECTION OUTPUT ;
    USE SIGNAL ;
    PORT
      LAYER M5 ;
        RECT  105.552 129.516 105.576 129.6 ;
    END
  END pd1[67]
  PIN pd1[680]
    DIRECTION OUTPUT ;
    USE SIGNAL ;
    PORT
      LAYER M5 ;
        RECT  119.088 129.516 119.112 129.6 ;
    END
  END pd1[680]
  PIN pd1[681]
    DIRECTION OUTPUT ;
    USE SIGNAL ;
    PORT
      LAYER M5 ;
        RECT  119.184 129.516 119.208 129.6 ;
    END
  END pd1[681]
  PIN pd1[682]
    DIRECTION OUTPUT ;
    USE SIGNAL ;
    PORT
      LAYER M5 ;
        RECT  119.28 129.516 119.304 129.6 ;
    END
  END pd1[682]
  PIN pd1[683]
    DIRECTION OUTPUT ;
    USE SIGNAL ;
    PORT
      LAYER M5 ;
        RECT  119.376 129.516 119.4 129.6 ;
    END
  END pd1[683]
  PIN pd1[684]
    DIRECTION OUTPUT ;
    USE SIGNAL ;
    PORT
      LAYER M5 ;
        RECT  119.472 129.516 119.496 129.6 ;
    END
  END pd1[684]
  PIN pd1[685]
    DIRECTION OUTPUT ;
    USE SIGNAL ;
    PORT
      LAYER M5 ;
        RECT  119.568 129.516 119.592 129.6 ;
    END
  END pd1[685]
  PIN pd1[686]
    DIRECTION OUTPUT ;
    USE SIGNAL ;
    PORT
      LAYER M5 ;
        RECT  119.664 129.516 119.688 129.6 ;
    END
  END pd1[686]
  PIN pd1[687]
    DIRECTION OUTPUT ;
    USE SIGNAL ;
    PORT
      LAYER M5 ;
        RECT  119.76 129.516 119.784 129.6 ;
    END
  END pd1[687]
  PIN pd1[688]
    DIRECTION OUTPUT ;
    USE SIGNAL ;
    PORT
      LAYER M5 ;
        RECT  119.856 129.516 119.88 129.6 ;
    END
  END pd1[688]
  PIN pd1[689]
    DIRECTION OUTPUT ;
    USE SIGNAL ;
    PORT
      LAYER M5 ;
        RECT  119.952 129.516 119.976 129.6 ;
    END
  END pd1[689]
  PIN pd1[68]
    DIRECTION OUTPUT ;
    USE SIGNAL ;
    PORT
      LAYER M5 ;
        RECT  105.648 129.516 105.672 129.6 ;
    END
  END pd1[68]
  PIN pd1[690]
    DIRECTION OUTPUT ;
    USE SIGNAL ;
    PORT
      LAYER M5 ;
        RECT  120.048 129.516 120.072 129.6 ;
    END
  END pd1[690]
  PIN pd1[691]
    DIRECTION OUTPUT ;
    USE SIGNAL ;
    PORT
      LAYER M5 ;
        RECT  120.144 129.516 120.168 129.6 ;
    END
  END pd1[691]
  PIN pd1[692]
    DIRECTION OUTPUT ;
    USE SIGNAL ;
    PORT
      LAYER M5 ;
        RECT  120.24 129.516 120.264 129.6 ;
    END
  END pd1[692]
  PIN pd1[693]
    DIRECTION OUTPUT ;
    USE SIGNAL ;
    PORT
      LAYER M5 ;
        RECT  120.336 129.516 120.36 129.6 ;
    END
  END pd1[693]
  PIN pd1[694]
    DIRECTION OUTPUT ;
    USE SIGNAL ;
    PORT
      LAYER M5 ;
        RECT  120.432 129.516 120.456 129.6 ;
    END
  END pd1[694]
  PIN pd1[695]
    DIRECTION OUTPUT ;
    USE SIGNAL ;
    PORT
      LAYER M5 ;
        RECT  120.528 129.516 120.552 129.6 ;
    END
  END pd1[695]
  PIN pd1[696]
    DIRECTION OUTPUT ;
    USE SIGNAL ;
    PORT
      LAYER M5 ;
        RECT  120.624 129.516 120.648 129.6 ;
    END
  END pd1[696]
  PIN pd1[697]
    DIRECTION OUTPUT ;
    USE SIGNAL ;
    PORT
      LAYER M5 ;
        RECT  120.72 129.516 120.744 129.6 ;
    END
  END pd1[697]
  PIN pd1[698]
    DIRECTION OUTPUT ;
    USE SIGNAL ;
    PORT
      LAYER M5 ;
        RECT  120.816 129.516 120.84 129.6 ;
    END
  END pd1[698]
  PIN pd1[699]
    DIRECTION OUTPUT ;
    USE SIGNAL ;
    PORT
      LAYER M5 ;
        RECT  120.912 129.516 120.936 129.6 ;
    END
  END pd1[699]
  PIN pd1[69]
    DIRECTION OUTPUT ;
    USE SIGNAL ;
    PORT
      LAYER M5 ;
        RECT  105.744 129.516 105.768 129.6 ;
    END
  END pd1[69]
  PIN pd1[6]
    DIRECTION OUTPUT ;
    USE SIGNAL ;
    PORT
      LAYER M5 ;
        RECT  160.368 129.516 160.392 129.6 ;
    END
  END pd1[6]
  PIN pd1[700]
    DIRECTION OUTPUT ;
    USE SIGNAL ;
    PORT
      LAYER M5 ;
        RECT  121.008 129.516 121.032 129.6 ;
    END
  END pd1[700]
  PIN pd1[701]
    DIRECTION OUTPUT ;
    USE SIGNAL ;
    PORT
      LAYER M5 ;
        RECT  121.104 129.516 121.128 129.6 ;
    END
  END pd1[701]
  PIN pd1[702]
    DIRECTION OUTPUT ;
    USE SIGNAL ;
    PORT
      LAYER M5 ;
        RECT  121.2 129.516 121.224 129.6 ;
    END
  END pd1[702]
  PIN pd1[703]
    DIRECTION OUTPUT ;
    USE SIGNAL ;
    PORT
      LAYER M5 ;
        RECT  121.296 129.516 121.32 129.6 ;
    END
  END pd1[703]
  PIN pd1[704]
    DIRECTION OUTPUT ;
    USE SIGNAL ;
    PORT
      LAYER M5 ;
        RECT  89.136 129.516 89.16 129.6 ;
    END
  END pd1[704]
  PIN pd1[705]
    DIRECTION OUTPUT ;
    USE SIGNAL ;
    PORT
      LAYER M5 ;
        RECT  89.232 129.516 89.256 129.6 ;
    END
  END pd1[705]
  PIN pd1[706]
    DIRECTION OUTPUT ;
    USE SIGNAL ;
    PORT
      LAYER M5 ;
        RECT  89.328 129.516 89.352 129.6 ;
    END
  END pd1[706]
  PIN pd1[707]
    DIRECTION OUTPUT ;
    USE SIGNAL ;
    PORT
      LAYER M5 ;
        RECT  89.424 129.516 89.448 129.6 ;
    END
  END pd1[707]
  PIN pd1[708]
    DIRECTION OUTPUT ;
    USE SIGNAL ;
    PORT
      LAYER M5 ;
        RECT  89.52 129.516 89.544 129.6 ;
    END
  END pd1[708]
  PIN pd1[709]
    DIRECTION OUTPUT ;
    USE SIGNAL ;
    PORT
      LAYER M5 ;
        RECT  89.616 129.516 89.64 129.6 ;
    END
  END pd1[709]
  PIN pd1[70]
    DIRECTION OUTPUT ;
    USE SIGNAL ;
    PORT
      LAYER M5 ;
        RECT  105.84 129.516 105.864 129.6 ;
    END
  END pd1[70]
  PIN pd1[710]
    DIRECTION OUTPUT ;
    USE SIGNAL ;
    PORT
      LAYER M5 ;
        RECT  89.712 129.516 89.736 129.6 ;
    END
  END pd1[710]
  PIN pd1[711]
    DIRECTION OUTPUT ;
    USE SIGNAL ;
    PORT
      LAYER M5 ;
        RECT  89.808 129.516 89.832 129.6 ;
    END
  END pd1[711]
  PIN pd1[712]
    DIRECTION OUTPUT ;
    USE SIGNAL ;
    PORT
      LAYER M5 ;
        RECT  89.904 129.516 89.928 129.6 ;
    END
  END pd1[712]
  PIN pd1[713]
    DIRECTION OUTPUT ;
    USE SIGNAL ;
    PORT
      LAYER M5 ;
        RECT  90 129.516 90.024 129.6 ;
    END
  END pd1[713]
  PIN pd1[714]
    DIRECTION OUTPUT ;
    USE SIGNAL ;
    PORT
      LAYER M5 ;
        RECT  90.096 129.516 90.12 129.6 ;
    END
  END pd1[714]
  PIN pd1[715]
    DIRECTION OUTPUT ;
    USE SIGNAL ;
    PORT
      LAYER M5 ;
        RECT  90.192 129.516 90.216 129.6 ;
    END
  END pd1[715]
  PIN pd1[716]
    DIRECTION OUTPUT ;
    USE SIGNAL ;
    PORT
      LAYER M5 ;
        RECT  90.288 129.516 90.312 129.6 ;
    END
  END pd1[716]
  PIN pd1[717]
    DIRECTION OUTPUT ;
    USE SIGNAL ;
    PORT
      LAYER M5 ;
        RECT  90.384 129.516 90.408 129.6 ;
    END
  END pd1[717]
  PIN pd1[718]
    DIRECTION OUTPUT ;
    USE SIGNAL ;
    PORT
      LAYER M5 ;
        RECT  90.48 129.516 90.504 129.6 ;
    END
  END pd1[718]
  PIN pd1[719]
    DIRECTION OUTPUT ;
    USE SIGNAL ;
    PORT
      LAYER M5 ;
        RECT  90.576 129.516 90.6 129.6 ;
    END
  END pd1[719]
  PIN pd1[71]
    DIRECTION OUTPUT ;
    USE SIGNAL ;
    PORT
      LAYER M5 ;
        RECT  105.936 129.516 105.96 129.6 ;
    END
  END pd1[71]
  PIN pd1[720]
    DIRECTION OUTPUT ;
    USE SIGNAL ;
    PORT
      LAYER M5 ;
        RECT  90.672 129.516 90.696 129.6 ;
    END
  END pd1[720]
  PIN pd1[721]
    DIRECTION OUTPUT ;
    USE SIGNAL ;
    PORT
      LAYER M5 ;
        RECT  90.768 129.516 90.792 129.6 ;
    END
  END pd1[721]
  PIN pd1[722]
    DIRECTION OUTPUT ;
    USE SIGNAL ;
    PORT
      LAYER M5 ;
        RECT  90.864 129.516 90.888 129.6 ;
    END
  END pd1[722]
  PIN pd1[723]
    DIRECTION OUTPUT ;
    USE SIGNAL ;
    PORT
      LAYER M5 ;
        RECT  90.96 129.516 90.984 129.6 ;
    END
  END pd1[723]
  PIN pd1[724]
    DIRECTION OUTPUT ;
    USE SIGNAL ;
    PORT
      LAYER M5 ;
        RECT  91.056 129.516 91.08 129.6 ;
    END
  END pd1[724]
  PIN pd1[725]
    DIRECTION OUTPUT ;
    USE SIGNAL ;
    PORT
      LAYER M5 ;
        RECT  91.152 129.516 91.176 129.6 ;
    END
  END pd1[725]
  PIN pd1[726]
    DIRECTION OUTPUT ;
    USE SIGNAL ;
    PORT
      LAYER M5 ;
        RECT  91.248 129.516 91.272 129.6 ;
    END
  END pd1[726]
  PIN pd1[727]
    DIRECTION OUTPUT ;
    USE SIGNAL ;
    PORT
      LAYER M5 ;
        RECT  91.344 129.516 91.368 129.6 ;
    END
  END pd1[727]
  PIN pd1[728]
    DIRECTION OUTPUT ;
    USE SIGNAL ;
    PORT
      LAYER M5 ;
        RECT  91.44 129.516 91.464 129.6 ;
    END
  END pd1[728]
  PIN pd1[729]
    DIRECTION OUTPUT ;
    USE SIGNAL ;
    PORT
      LAYER M5 ;
        RECT  91.536 129.516 91.56 129.6 ;
    END
  END pd1[729]
  PIN pd1[72]
    DIRECTION OUTPUT ;
    USE SIGNAL ;
    PORT
      LAYER M5 ;
        RECT  106.032 129.516 106.056 129.6 ;
    END
  END pd1[72]
  PIN pd1[730]
    DIRECTION OUTPUT ;
    USE SIGNAL ;
    PORT
      LAYER M5 ;
        RECT  91.632 129.516 91.656 129.6 ;
    END
  END pd1[730]
  PIN pd1[731]
    DIRECTION OUTPUT ;
    USE SIGNAL ;
    PORT
      LAYER M5 ;
        RECT  91.728 129.516 91.752 129.6 ;
    END
  END pd1[731]
  PIN pd1[732]
    DIRECTION OUTPUT ;
    USE SIGNAL ;
    PORT
      LAYER M5 ;
        RECT  91.824 129.516 91.848 129.6 ;
    END
  END pd1[732]
  PIN pd1[733]
    DIRECTION OUTPUT ;
    USE SIGNAL ;
    PORT
      LAYER M5 ;
        RECT  91.92 129.516 91.944 129.6 ;
    END
  END pd1[733]
  PIN pd1[734]
    DIRECTION OUTPUT ;
    USE SIGNAL ;
    PORT
      LAYER M5 ;
        RECT  92.016 129.516 92.04 129.6 ;
    END
  END pd1[734]
  PIN pd1[735]
    DIRECTION OUTPUT ;
    USE SIGNAL ;
    PORT
      LAYER M5 ;
        RECT  92.112 129.516 92.136 129.6 ;
    END
  END pd1[735]
  PIN pd1[736]
    DIRECTION OUTPUT ;
    USE SIGNAL ;
    PORT
      LAYER M5 ;
        RECT  73.008 129.516 73.032 129.6 ;
    END
  END pd1[736]
  PIN pd1[737]
    DIRECTION OUTPUT ;
    USE SIGNAL ;
    PORT
      LAYER M5 ;
        RECT  73.104 129.516 73.128 129.6 ;
    END
  END pd1[737]
  PIN pd1[738]
    DIRECTION OUTPUT ;
    USE SIGNAL ;
    PORT
      LAYER M5 ;
        RECT  73.2 129.516 73.224 129.6 ;
    END
  END pd1[738]
  PIN pd1[739]
    DIRECTION OUTPUT ;
    USE SIGNAL ;
    PORT
      LAYER M5 ;
        RECT  73.296 129.516 73.32 129.6 ;
    END
  END pd1[739]
  PIN pd1[73]
    DIRECTION OUTPUT ;
    USE SIGNAL ;
    PORT
      LAYER M5 ;
        RECT  106.128 129.516 106.152 129.6 ;
    END
  END pd1[73]
  PIN pd1[740]
    DIRECTION OUTPUT ;
    USE SIGNAL ;
    PORT
      LAYER M5 ;
        RECT  73.392 129.516 73.416 129.6 ;
    END
  END pd1[740]
  PIN pd1[741]
    DIRECTION OUTPUT ;
    USE SIGNAL ;
    PORT
      LAYER M5 ;
        RECT  73.488 129.516 73.512 129.6 ;
    END
  END pd1[741]
  PIN pd1[742]
    DIRECTION OUTPUT ;
    USE SIGNAL ;
    PORT
      LAYER M5 ;
        RECT  73.584 129.516 73.608 129.6 ;
    END
  END pd1[742]
  PIN pd1[743]
    DIRECTION OUTPUT ;
    USE SIGNAL ;
    PORT
      LAYER M5 ;
        RECT  73.68 129.516 73.704 129.6 ;
    END
  END pd1[743]
  PIN pd1[744]
    DIRECTION OUTPUT ;
    USE SIGNAL ;
    PORT
      LAYER M5 ;
        RECT  73.776 129.516 73.8 129.6 ;
    END
  END pd1[744]
  PIN pd1[745]
    DIRECTION OUTPUT ;
    USE SIGNAL ;
    PORT
      LAYER M5 ;
        RECT  73.872 129.516 73.896 129.6 ;
    END
  END pd1[745]
  PIN pd1[746]
    DIRECTION OUTPUT ;
    USE SIGNAL ;
    PORT
      LAYER M5 ;
        RECT  73.968 129.516 73.992 129.6 ;
    END
  END pd1[746]
  PIN pd1[747]
    DIRECTION OUTPUT ;
    USE SIGNAL ;
    PORT
      LAYER M5 ;
        RECT  74.064 129.516 74.088 129.6 ;
    END
  END pd1[747]
  PIN pd1[748]
    DIRECTION OUTPUT ;
    USE SIGNAL ;
    PORT
      LAYER M5 ;
        RECT  74.16 129.516 74.184 129.6 ;
    END
  END pd1[748]
  PIN pd1[749]
    DIRECTION OUTPUT ;
    USE SIGNAL ;
    PORT
      LAYER M5 ;
        RECT  74.256 129.516 74.28 129.6 ;
    END
  END pd1[749]
  PIN pd1[74]
    DIRECTION OUTPUT ;
    USE SIGNAL ;
    PORT
      LAYER M5 ;
        RECT  106.224 129.516 106.248 129.6 ;
    END
  END pd1[74]
  PIN pd1[750]
    DIRECTION OUTPUT ;
    USE SIGNAL ;
    PORT
      LAYER M5 ;
        RECT  74.352 129.516 74.376 129.6 ;
    END
  END pd1[750]
  PIN pd1[751]
    DIRECTION OUTPUT ;
    USE SIGNAL ;
    PORT
      LAYER M5 ;
        RECT  74.448 129.516 74.472 129.6 ;
    END
  END pd1[751]
  PIN pd1[752]
    DIRECTION OUTPUT ;
    USE SIGNAL ;
    PORT
      LAYER M5 ;
        RECT  74.544 129.516 74.568 129.6 ;
    END
  END pd1[752]
  PIN pd1[753]
    DIRECTION OUTPUT ;
    USE SIGNAL ;
    PORT
      LAYER M5 ;
        RECT  74.64 129.516 74.664 129.6 ;
    END
  END pd1[753]
  PIN pd1[754]
    DIRECTION OUTPUT ;
    USE SIGNAL ;
    PORT
      LAYER M5 ;
        RECT  74.736 129.516 74.76 129.6 ;
    END
  END pd1[754]
  PIN pd1[755]
    DIRECTION OUTPUT ;
    USE SIGNAL ;
    PORT
      LAYER M5 ;
        RECT  74.832 129.516 74.856 129.6 ;
    END
  END pd1[755]
  PIN pd1[756]
    DIRECTION OUTPUT ;
    USE SIGNAL ;
    PORT
      LAYER M5 ;
        RECT  74.928 129.516 74.952 129.6 ;
    END
  END pd1[756]
  PIN pd1[757]
    DIRECTION OUTPUT ;
    USE SIGNAL ;
    PORT
      LAYER M5 ;
        RECT  75.024 129.516 75.048 129.6 ;
    END
  END pd1[757]
  PIN pd1[758]
    DIRECTION OUTPUT ;
    USE SIGNAL ;
    PORT
      LAYER M5 ;
        RECT  75.12 129.516 75.144 129.6 ;
    END
  END pd1[758]
  PIN pd1[759]
    DIRECTION OUTPUT ;
    USE SIGNAL ;
    PORT
      LAYER M5 ;
        RECT  75.216 129.516 75.24 129.6 ;
    END
  END pd1[759]
  PIN pd1[75]
    DIRECTION OUTPUT ;
    USE SIGNAL ;
    PORT
      LAYER M5 ;
        RECT  106.32 129.516 106.344 129.6 ;
    END
  END pd1[75]
  PIN pd1[760]
    DIRECTION OUTPUT ;
    USE SIGNAL ;
    PORT
      LAYER M5 ;
        RECT  75.312 129.516 75.336 129.6 ;
    END
  END pd1[760]
  PIN pd1[761]
    DIRECTION OUTPUT ;
    USE SIGNAL ;
    PORT
      LAYER M5 ;
        RECT  75.408 129.516 75.432 129.6 ;
    END
  END pd1[761]
  PIN pd1[762]
    DIRECTION OUTPUT ;
    USE SIGNAL ;
    PORT
      LAYER M5 ;
        RECT  75.504 129.516 75.528 129.6 ;
    END
  END pd1[762]
  PIN pd1[763]
    DIRECTION OUTPUT ;
    USE SIGNAL ;
    PORT
      LAYER M5 ;
        RECT  75.6 129.516 75.624 129.6 ;
    END
  END pd1[763]
  PIN pd1[764]
    DIRECTION OUTPUT ;
    USE SIGNAL ;
    PORT
      LAYER M5 ;
        RECT  75.696 129.516 75.72 129.6 ;
    END
  END pd1[764]
  PIN pd1[765]
    DIRECTION OUTPUT ;
    USE SIGNAL ;
    PORT
      LAYER M5 ;
        RECT  75.792 129.516 75.816 129.6 ;
    END
  END pd1[765]
  PIN pd1[766]
    DIRECTION OUTPUT ;
    USE SIGNAL ;
    PORT
      LAYER M5 ;
        RECT  75.888 129.516 75.912 129.6 ;
    END
  END pd1[766]
  PIN pd1[767]
    DIRECTION OUTPUT ;
    USE SIGNAL ;
    PORT
      LAYER M5 ;
        RECT  75.984 129.516 76.008 129.6 ;
    END
  END pd1[767]
  PIN pd1[76]
    DIRECTION OUTPUT ;
    USE SIGNAL ;
    PORT
      LAYER M5 ;
        RECT  106.416 129.516 106.44 129.6 ;
    END
  END pd1[76]
  PIN pd1[77]
    DIRECTION OUTPUT ;
    USE SIGNAL ;
    PORT
      LAYER M5 ;
        RECT  106.512 129.516 106.536 129.6 ;
    END
  END pd1[77]
  PIN pd1[78]
    DIRECTION OUTPUT ;
    USE SIGNAL ;
    PORT
      LAYER M5 ;
        RECT  106.608 129.516 106.632 129.6 ;
    END
  END pd1[78]
  PIN pd1[79]
    DIRECTION OUTPUT ;
    USE SIGNAL ;
    PORT
      LAYER M5 ;
        RECT  106.704 129.516 106.728 129.6 ;
    END
  END pd1[79]
  PIN pd1[7]
    DIRECTION OUTPUT ;
    USE SIGNAL ;
    PORT
      LAYER M5 ;
        RECT  160.464 129.516 160.488 129.6 ;
    END
  END pd1[7]
  PIN pd1[80]
    DIRECTION OUTPUT ;
    USE SIGNAL ;
    PORT
      LAYER M5 ;
        RECT  106.8 129.516 106.824 129.6 ;
    END
  END pd1[80]
  PIN pd1[81]
    DIRECTION OUTPUT ;
    USE SIGNAL ;
    PORT
      LAYER M5 ;
        RECT  106.896 129.516 106.92 129.6 ;
    END
  END pd1[81]
  PIN pd1[82]
    DIRECTION OUTPUT ;
    USE SIGNAL ;
    PORT
      LAYER M5 ;
        RECT  106.992 129.516 107.016 129.6 ;
    END
  END pd1[82]
  PIN pd1[83]
    DIRECTION OUTPUT ;
    USE SIGNAL ;
    PORT
      LAYER M5 ;
        RECT  107.088 129.516 107.112 129.6 ;
    END
  END pd1[83]
  PIN pd1[84]
    DIRECTION OUTPUT ;
    USE SIGNAL ;
    PORT
      LAYER M5 ;
        RECT  107.184 129.516 107.208 129.6 ;
    END
  END pd1[84]
  PIN pd1[85]
    DIRECTION OUTPUT ;
    USE SIGNAL ;
    PORT
      LAYER M5 ;
        RECT  107.28 129.516 107.304 129.6 ;
    END
  END pd1[85]
  PIN pd1[86]
    DIRECTION OUTPUT ;
    USE SIGNAL ;
    PORT
      LAYER M5 ;
        RECT  107.376 129.516 107.4 129.6 ;
    END
  END pd1[86]
  PIN pd1[87]
    DIRECTION OUTPUT ;
    USE SIGNAL ;
    PORT
      LAYER M5 ;
        RECT  107.472 129.516 107.496 129.6 ;
    END
  END pd1[87]
  PIN pd1[88]
    DIRECTION OUTPUT ;
    USE SIGNAL ;
    PORT
      LAYER M5 ;
        RECT  107.568 129.516 107.592 129.6 ;
    END
  END pd1[88]
  PIN pd1[89]
    DIRECTION OUTPUT ;
    USE SIGNAL ;
    PORT
      LAYER M5 ;
        RECT  107.664 129.516 107.688 129.6 ;
    END
  END pd1[89]
  PIN pd1[8]
    DIRECTION OUTPUT ;
    USE SIGNAL ;
    PORT
      LAYER M5 ;
        RECT  160.56 129.516 160.584 129.6 ;
    END
  END pd1[8]
  PIN pd1[90]
    DIRECTION OUTPUT ;
    USE SIGNAL ;
    PORT
      LAYER M5 ;
        RECT  107.76 129.516 107.784 129.6 ;
    END
  END pd1[90]
  PIN pd1[91]
    DIRECTION OUTPUT ;
    USE SIGNAL ;
    PORT
      LAYER M5 ;
        RECT  107.856 129.516 107.88 129.6 ;
    END
  END pd1[91]
  PIN pd1[92]
    DIRECTION OUTPUT ;
    USE SIGNAL ;
    PORT
      LAYER M5 ;
        RECT  107.952 129.516 107.976 129.6 ;
    END
  END pd1[92]
  PIN pd1[93]
    DIRECTION OUTPUT ;
    USE SIGNAL ;
    PORT
      LAYER M5 ;
        RECT  108.048 129.516 108.072 129.6 ;
    END
  END pd1[93]
  PIN pd1[94]
    DIRECTION OUTPUT ;
    USE SIGNAL ;
    PORT
      LAYER M5 ;
        RECT  108.144 129.516 108.168 129.6 ;
    END
  END pd1[94]
  PIN pd1[95]
    DIRECTION OUTPUT ;
    USE SIGNAL ;
    PORT
      LAYER M5 ;
        RECT  108.24 129.516 108.264 129.6 ;
    END
  END pd1[95]
  PIN pd1[96]
    DIRECTION OUTPUT ;
    USE SIGNAL ;
    PORT
      LAYER M5 ;
        RECT  162.864 129.516 162.888 129.6 ;
    END
  END pd1[96]
  PIN pd1[97]
    DIRECTION OUTPUT ;
    USE SIGNAL ;
    PORT
      LAYER M5 ;
        RECT  162.96 129.516 162.984 129.6 ;
    END
  END pd1[97]
  PIN pd1[98]
    DIRECTION OUTPUT ;
    USE SIGNAL ;
    PORT
      LAYER M5 ;
        RECT  163.056 129.516 163.08 129.6 ;
    END
  END pd1[98]
  PIN pd1[99]
    DIRECTION OUTPUT ;
    USE SIGNAL ;
    PORT
      LAYER M5 ;
        RECT  163.152 129.516 163.176 129.6 ;
    END
  END pd1[99]
  PIN pd1[9]
    DIRECTION OUTPUT ;
    USE SIGNAL ;
    PORT
      LAYER M5 ;
        RECT  160.656 129.516 160.68 129.6 ;
    END
  END pd1[9]
  PIN rd_v
    DIRECTION INPUT ;
    USE SIGNAL ;
    PORT
      LAYER M4 ;
        RECT  0 55.344 0.084 55.368 ;
    END
  END rd_v
  PIN red_busy
    DIRECTION INPUT ;
    USE SIGNAL ;
    PORT
      LAYER M4 ;
        RECT  0 55.44 0.084 55.464 ;
    END
  END red_busy
  PIN red_fault
    DIRECTION INPUT ;
    USE SIGNAL ;
    PORT
      LAYER M4 ;
        RECT  0 55.536 0.084 55.56 ;
    END
  END red_fault
  PIN rst_n
    DIRECTION INPUT ;
    USE SIGNAL ;
    PORT
      LAYER M5 ;
        RECT  46.128 0 46.152 0.084 ;
    END
  END rst_n
  PIN si[0]
    DIRECTION INPUT ;
    USE SIGNAL ;
    PORT
      LAYER M4 ;
        RECT  0 55.632 0.084 55.656 ;
    END
  END si[0]
  PIN si[100]
    DIRECTION INPUT ;
    USE SIGNAL ;
    PORT
      LAYER M4 ;
        RECT  0 62.16 0.084 62.184 ;
    END
  END si[100]
  PIN si[101]
    DIRECTION INPUT ;
    USE SIGNAL ;
    PORT
      LAYER M4 ;
        RECT  0 62.256 0.084 62.28 ;
    END
  END si[101]
  PIN si[102]
    DIRECTION INPUT ;
    USE SIGNAL ;
    PORT
      LAYER M4 ;
        RECT  0 62.352 0.084 62.376 ;
    END
  END si[102]
  PIN si[103]
    DIRECTION INPUT ;
    USE SIGNAL ;
    PORT
      LAYER M4 ;
        RECT  0 62.448 0.084 62.472 ;
    END
  END si[103]
  PIN si[104]
    DIRECTION INPUT ;
    USE SIGNAL ;
    PORT
      LAYER M4 ;
        RECT  0 62.544 0.084 62.568 ;
    END
  END si[104]
  PIN si[105]
    DIRECTION INPUT ;
    USE SIGNAL ;
    PORT
      LAYER M4 ;
        RECT  0 62.64 0.084 62.664 ;
    END
  END si[105]
  PIN si[106]
    DIRECTION INPUT ;
    USE SIGNAL ;
    PORT
      LAYER M4 ;
        RECT  0 62.736 0.084 62.76 ;
    END
  END si[106]
  PIN si[107]
    DIRECTION INPUT ;
    USE SIGNAL ;
    PORT
      LAYER M4 ;
        RECT  0 62.832 0.084 62.856 ;
    END
  END si[107]
  PIN si[108]
    DIRECTION INPUT ;
    USE SIGNAL ;
    PORT
      LAYER M4 ;
        RECT  0 62.928 0.084 62.952 ;
    END
  END si[108]
  PIN si[109]
    DIRECTION INPUT ;
    USE SIGNAL ;
    PORT
      LAYER M4 ;
        RECT  0 63.024 0.084 63.048 ;
    END
  END si[109]
  PIN si[10]
    DIRECTION INPUT ;
    USE SIGNAL ;
    PORT
      LAYER M4 ;
        RECT  0 56.592 0.084 56.616 ;
    END
  END si[10]
  PIN si[110]
    DIRECTION INPUT ;
    USE SIGNAL ;
    PORT
      LAYER M4 ;
        RECT  0 63.12 0.084 63.144 ;
    END
  END si[110]
  PIN si[111]
    DIRECTION INPUT ;
    USE SIGNAL ;
    PORT
      LAYER M4 ;
        RECT  0 63.216 0.084 63.24 ;
    END
  END si[111]
  PIN si[112]
    DIRECTION INPUT ;
    USE SIGNAL ;
    PORT
      LAYER M4 ;
        RECT  0 63.312 0.084 63.336 ;
    END
  END si[112]
  PIN si[113]
    DIRECTION INPUT ;
    USE SIGNAL ;
    PORT
      LAYER M4 ;
        RECT  0 63.408 0.084 63.432 ;
    END
  END si[113]
  PIN si[114]
    DIRECTION INPUT ;
    USE SIGNAL ;
    PORT
      LAYER M4 ;
        RECT  0 63.504 0.084 63.528 ;
    END
  END si[114]
  PIN si[115]
    DIRECTION INPUT ;
    USE SIGNAL ;
    PORT
      LAYER M4 ;
        RECT  0 63.6 0.084 63.624 ;
    END
  END si[115]
  PIN si[116]
    DIRECTION INPUT ;
    USE SIGNAL ;
    PORT
      LAYER M4 ;
        RECT  0 63.696 0.084 63.72 ;
    END
  END si[116]
  PIN si[117]
    DIRECTION INPUT ;
    USE SIGNAL ;
    PORT
      LAYER M4 ;
        RECT  0 63.792 0.084 63.816 ;
    END
  END si[117]
  PIN si[118]
    DIRECTION INPUT ;
    USE SIGNAL ;
    PORT
      LAYER M4 ;
        RECT  0 63.888 0.084 63.912 ;
    END
  END si[118]
  PIN si[119]
    DIRECTION INPUT ;
    USE SIGNAL ;
    PORT
      LAYER M4 ;
        RECT  0 63.984 0.084 64.008 ;
    END
  END si[119]
  PIN si[11]
    DIRECTION INPUT ;
    USE SIGNAL ;
    PORT
      LAYER M4 ;
        RECT  0 56.688 0.084 56.712 ;
    END
  END si[11]
  PIN si[120]
    DIRECTION INPUT ;
    USE SIGNAL ;
    PORT
      LAYER M4 ;
        RECT  0 64.08 0.084 64.104 ;
    END
  END si[120]
  PIN si[121]
    DIRECTION INPUT ;
    USE SIGNAL ;
    PORT
      LAYER M4 ;
        RECT  0 64.176 0.084 64.2 ;
    END
  END si[121]
  PIN si[122]
    DIRECTION INPUT ;
    USE SIGNAL ;
    PORT
      LAYER M4 ;
        RECT  0 64.272 0.084 64.296 ;
    END
  END si[122]
  PIN si[123]
    DIRECTION INPUT ;
    USE SIGNAL ;
    PORT
      LAYER M4 ;
        RECT  0 64.368 0.084 64.392 ;
    END
  END si[123]
  PIN si[124]
    DIRECTION INPUT ;
    USE SIGNAL ;
    PORT
      LAYER M4 ;
        RECT  0 64.464 0.084 64.488 ;
    END
  END si[124]
  PIN si[125]
    DIRECTION INPUT ;
    USE SIGNAL ;
    PORT
      LAYER M4 ;
        RECT  0 64.56 0.084 64.584 ;
    END
  END si[125]
  PIN si[126]
    DIRECTION INPUT ;
    USE SIGNAL ;
    PORT
      LAYER M4 ;
        RECT  0 64.656 0.084 64.68 ;
    END
  END si[126]
  PIN si[127]
    DIRECTION INPUT ;
    USE SIGNAL ;
    PORT
      LAYER M4 ;
        RECT  0 64.752 0.084 64.776 ;
    END
  END si[127]
  PIN si[128]
    DIRECTION INPUT ;
    USE SIGNAL ;
    PORT
      LAYER M4 ;
        RECT  0 64.848 0.084 64.872 ;
    END
  END si[128]
  PIN si[129]
    DIRECTION INPUT ;
    USE SIGNAL ;
    PORT
      LAYER M4 ;
        RECT  0 64.944 0.084 64.968 ;
    END
  END si[129]
  PIN si[12]
    DIRECTION INPUT ;
    USE SIGNAL ;
    PORT
      LAYER M4 ;
        RECT  0 56.784 0.084 56.808 ;
    END
  END si[12]
  PIN si[130]
    DIRECTION INPUT ;
    USE SIGNAL ;
    PORT
      LAYER M4 ;
        RECT  0 65.04 0.084 65.064 ;
    END
  END si[130]
  PIN si[131]
    DIRECTION INPUT ;
    USE SIGNAL ;
    PORT
      LAYER M4 ;
        RECT  0 58.992 0.084 59.016 ;
    END
  END si[131]
  PIN si[132]
    DIRECTION INPUT ;
    USE SIGNAL ;
    PORT
      LAYER M4 ;
        RECT  0 59.088 0.084 59.112 ;
    END
  END si[132]
  PIN si[133]
    DIRECTION INPUT ;
    USE SIGNAL ;
    PORT
      LAYER M4 ;
        RECT  0 59.184 0.084 59.208 ;
    END
  END si[133]
  PIN si[134]
    DIRECTION INPUT ;
    USE SIGNAL ;
    PORT
      LAYER M4 ;
        RECT  0 59.28 0.084 59.304 ;
    END
  END si[134]
  PIN si[135]
    DIRECTION INPUT ;
    USE SIGNAL ;
    PORT
      LAYER M4 ;
        RECT  0 59.376 0.084 59.4 ;
    END
  END si[135]
  PIN si[136]
    DIRECTION INPUT ;
    USE SIGNAL ;
    PORT
      LAYER M4 ;
        RECT  0 59.472 0.084 59.496 ;
    END
  END si[136]
  PIN si[137]
    DIRECTION INPUT ;
    USE SIGNAL ;
    PORT
      LAYER M4 ;
        RECT  0 59.568 0.084 59.592 ;
    END
  END si[137]
  PIN si[138]
    DIRECTION INPUT ;
    USE SIGNAL ;
    PORT
      LAYER M4 ;
        RECT  0 59.664 0.084 59.688 ;
    END
  END si[138]
  PIN si[139]
    DIRECTION INPUT ;
    USE SIGNAL ;
    PORT
      LAYER M4 ;
        RECT  0 59.76 0.084 59.784 ;
    END
  END si[139]
  PIN si[13]
    DIRECTION INPUT ;
    USE SIGNAL ;
    PORT
      LAYER M4 ;
        RECT  0 56.88 0.084 56.904 ;
    END
  END si[13]
  PIN si[140]
    DIRECTION INPUT ;
    USE SIGNAL ;
    PORT
      LAYER M4 ;
        RECT  0 59.856 0.084 59.88 ;
    END
  END si[140]
  PIN si[141]
    DIRECTION INPUT ;
    USE SIGNAL ;
    PORT
      LAYER M4 ;
        RECT  0 59.952 0.084 59.976 ;
    END
  END si[141]
  PIN si[142]
    DIRECTION INPUT ;
    USE SIGNAL ;
    PORT
      LAYER M4 ;
        RECT  0 60.048 0.084 60.072 ;
    END
  END si[142]
  PIN si[143]
    DIRECTION INPUT ;
    USE SIGNAL ;
    PORT
      LAYER M4 ;
        RECT  0 60.144 0.084 60.168 ;
    END
  END si[143]
  PIN si[144]
    DIRECTION INPUT ;
    USE SIGNAL ;
    PORT
      LAYER M4 ;
        RECT  0 60.24 0.084 60.264 ;
    END
  END si[144]
  PIN si[145]
    DIRECTION INPUT ;
    USE SIGNAL ;
    PORT
      LAYER M4 ;
        RECT  0 60.336 0.084 60.36 ;
    END
  END si[145]
  PIN si[146]
    DIRECTION INPUT ;
    USE SIGNAL ;
    PORT
      LAYER M4 ;
        RECT  0 60.432 0.084 60.456 ;
    END
  END si[146]
  PIN si[147]
    DIRECTION INPUT ;
    USE SIGNAL ;
    PORT
      LAYER M4 ;
        RECT  0 60.528 0.084 60.552 ;
    END
  END si[147]
  PIN si[148]
    DIRECTION INPUT ;
    USE SIGNAL ;
    PORT
      LAYER M4 ;
        RECT  0 60.624 0.084 60.648 ;
    END
  END si[148]
  PIN si[149]
    DIRECTION INPUT ;
    USE SIGNAL ;
    PORT
      LAYER M4 ;
        RECT  0 60.72 0.084 60.744 ;
    END
  END si[149]
  PIN si[14]
    DIRECTION INPUT ;
    USE SIGNAL ;
    PORT
      LAYER M4 ;
        RECT  0 56.976 0.084 57 ;
    END
  END si[14]
  PIN si[150]
    DIRECTION INPUT ;
    USE SIGNAL ;
    PORT
      LAYER M4 ;
        RECT  0 60.816 0.084 60.84 ;
    END
  END si[150]
  PIN si[151]
    DIRECTION INPUT ;
    USE SIGNAL ;
    PORT
      LAYER M4 ;
        RECT  0 60.912 0.084 60.936 ;
    END
  END si[151]
  PIN si[152]
    DIRECTION INPUT ;
    USE SIGNAL ;
    PORT
      LAYER M4 ;
        RECT  0 61.008 0.084 61.032 ;
    END
  END si[152]
  PIN si[153]
    DIRECTION INPUT ;
    USE SIGNAL ;
    PORT
      LAYER M4 ;
        RECT  0 61.104 0.084 61.128 ;
    END
  END si[153]
  PIN si[154]
    DIRECTION INPUT ;
    USE SIGNAL ;
    PORT
      LAYER M4 ;
        RECT  0 61.2 0.084 61.224 ;
    END
  END si[154]
  PIN si[155]
    DIRECTION INPUT ;
    USE SIGNAL ;
    PORT
      LAYER M4 ;
        RECT  0 61.296 0.084 61.32 ;
    END
  END si[155]
  PIN si[156]
    DIRECTION INPUT ;
    USE SIGNAL ;
    PORT
      LAYER M4 ;
        RECT  0 61.392 0.084 61.416 ;
    END
  END si[156]
  PIN si[157]
    DIRECTION INPUT ;
    USE SIGNAL ;
    PORT
      LAYER M4 ;
        RECT  0 61.488 0.084 61.512 ;
    END
  END si[157]
  PIN si[158]
    DIRECTION INPUT ;
    USE SIGNAL ;
    PORT
      LAYER M4 ;
        RECT  0 61.584 0.084 61.608 ;
    END
  END si[158]
  PIN si[159]
    DIRECTION INPUT ;
    USE SIGNAL ;
    PORT
      LAYER M4 ;
        RECT  0 61.68 0.084 61.704 ;
    END
  END si[159]
  PIN si[15]
    DIRECTION INPUT ;
    USE SIGNAL ;
    PORT
      LAYER M4 ;
        RECT  0 57.072 0.084 57.096 ;
    END
  END si[15]
  PIN si[160]
    DIRECTION INPUT ;
    USE SIGNAL ;
    PORT
      LAYER M4 ;
        RECT  0 61.776 0.084 61.8 ;
    END
  END si[160]
  PIN si[161]
    DIRECTION INPUT ;
    USE SIGNAL ;
    PORT
      LAYER M4 ;
        RECT  0 61.872 0.084 61.896 ;
    END
  END si[161]
  PIN si[162]
    DIRECTION INPUT ;
    USE SIGNAL ;
    PORT
      LAYER M4 ;
        RECT  0 61.968 0.084 61.992 ;
    END
  END si[162]
  PIN si[163]
    DIRECTION INPUT ;
    USE SIGNAL ;
    PORT
      LAYER M4 ;
        RECT  0 72.048 0.084 72.072 ;
    END
  END si[163]
  PIN si[164]
    DIRECTION INPUT ;
    USE SIGNAL ;
    PORT
      LAYER M4 ;
        RECT  0 72.144 0.084 72.168 ;
    END
  END si[164]
  PIN si[165]
    DIRECTION INPUT ;
    USE SIGNAL ;
    PORT
      LAYER M4 ;
        RECT  0 72.24 0.084 72.264 ;
    END
  END si[165]
  PIN si[166]
    DIRECTION INPUT ;
    USE SIGNAL ;
    PORT
      LAYER M4 ;
        RECT  0 72.336 0.084 72.36 ;
    END
  END si[166]
  PIN si[167]
    DIRECTION INPUT ;
    USE SIGNAL ;
    PORT
      LAYER M4 ;
        RECT  0 72.432 0.084 72.456 ;
    END
  END si[167]
  PIN si[168]
    DIRECTION INPUT ;
    USE SIGNAL ;
    PORT
      LAYER M4 ;
        RECT  0 72.528 0.084 72.552 ;
    END
  END si[168]
  PIN si[169]
    DIRECTION INPUT ;
    USE SIGNAL ;
    PORT
      LAYER M4 ;
        RECT  0 72.624 0.084 72.648 ;
    END
  END si[169]
  PIN si[16]
    DIRECTION INPUT ;
    USE SIGNAL ;
    PORT
      LAYER M4 ;
        RECT  0 57.168 0.084 57.192 ;
    END
  END si[16]
  PIN si[170]
    DIRECTION INPUT ;
    USE SIGNAL ;
    PORT
      LAYER M4 ;
        RECT  0 72.72 0.084 72.744 ;
    END
  END si[170]
  PIN si[171]
    DIRECTION INPUT ;
    USE SIGNAL ;
    PORT
      LAYER M4 ;
        RECT  0 72.816 0.084 72.84 ;
    END
  END si[171]
  PIN si[172]
    DIRECTION INPUT ;
    USE SIGNAL ;
    PORT
      LAYER M4 ;
        RECT  0 72.912 0.084 72.936 ;
    END
  END si[172]
  PIN si[173]
    DIRECTION INPUT ;
    USE SIGNAL ;
    PORT
      LAYER M4 ;
        RECT  0 73.008 0.084 73.032 ;
    END
  END si[173]
  PIN si[174]
    DIRECTION INPUT ;
    USE SIGNAL ;
    PORT
      LAYER M4 ;
        RECT  0 73.104 0.084 73.128 ;
    END
  END si[174]
  PIN si[175]
    DIRECTION INPUT ;
    USE SIGNAL ;
    PORT
      LAYER M4 ;
        RECT  0 73.2 0.084 73.224 ;
    END
  END si[175]
  PIN si[176]
    DIRECTION INPUT ;
    USE SIGNAL ;
    PORT
      LAYER M4 ;
        RECT  0 73.296 0.084 73.32 ;
    END
  END si[176]
  PIN si[177]
    DIRECTION INPUT ;
    USE SIGNAL ;
    PORT
      LAYER M4 ;
        RECT  0 73.392 0.084 73.416 ;
    END
  END si[177]
  PIN si[178]
    DIRECTION INPUT ;
    USE SIGNAL ;
    PORT
      LAYER M4 ;
        RECT  0 73.488 0.084 73.512 ;
    END
  END si[178]
  PIN si[179]
    DIRECTION INPUT ;
    USE SIGNAL ;
    PORT
      LAYER M4 ;
        RECT  0 73.584 0.084 73.608 ;
    END
  END si[179]
  PIN si[17]
    DIRECTION INPUT ;
    USE SIGNAL ;
    PORT
      LAYER M4 ;
        RECT  0 57.264 0.084 57.288 ;
    END
  END si[17]
  PIN si[180]
    DIRECTION INPUT ;
    USE SIGNAL ;
    PORT
      LAYER M4 ;
        RECT  0 73.68 0.084 73.704 ;
    END
  END si[180]
  PIN si[181]
    DIRECTION INPUT ;
    USE SIGNAL ;
    PORT
      LAYER M4 ;
        RECT  0 73.776 0.084 73.8 ;
    END
  END si[181]
  PIN si[182]
    DIRECTION INPUT ;
    USE SIGNAL ;
    PORT
      LAYER M4 ;
        RECT  0 73.872 0.084 73.896 ;
    END
  END si[182]
  PIN si[183]
    DIRECTION INPUT ;
    USE SIGNAL ;
    PORT
      LAYER M4 ;
        RECT  0 73.968 0.084 73.992 ;
    END
  END si[183]
  PIN si[184]
    DIRECTION INPUT ;
    USE SIGNAL ;
    PORT
      LAYER M4 ;
        RECT  0 74.064 0.084 74.088 ;
    END
  END si[184]
  PIN si[185]
    DIRECTION INPUT ;
    USE SIGNAL ;
    PORT
      LAYER M4 ;
        RECT  0 74.16 0.084 74.184 ;
    END
  END si[185]
  PIN si[186]
    DIRECTION INPUT ;
    USE SIGNAL ;
    PORT
      LAYER M4 ;
        RECT  0 74.256 0.084 74.28 ;
    END
  END si[186]
  PIN si[187]
    DIRECTION INPUT ;
    USE SIGNAL ;
    PORT
      LAYER M4 ;
        RECT  0 74.352 0.084 74.376 ;
    END
  END si[187]
  PIN si[188]
    DIRECTION INPUT ;
    USE SIGNAL ;
    PORT
      LAYER M4 ;
        RECT  0 74.448 0.084 74.472 ;
    END
  END si[188]
  PIN si[189]
    DIRECTION INPUT ;
    USE SIGNAL ;
    PORT
      LAYER M4 ;
        RECT  0 74.544 0.084 74.568 ;
    END
  END si[189]
  PIN si[18]
    DIRECTION INPUT ;
    USE SIGNAL ;
    PORT
      LAYER M4 ;
        RECT  0 57.36 0.084 57.384 ;
    END
  END si[18]
  PIN si[190]
    DIRECTION INPUT ;
    USE SIGNAL ;
    PORT
      LAYER M4 ;
        RECT  0 74.64 0.084 74.664 ;
    END
  END si[190]
  PIN si[191]
    DIRECTION INPUT ;
    USE SIGNAL ;
    PORT
      LAYER M4 ;
        RECT  0 74.736 0.084 74.76 ;
    END
  END si[191]
  PIN si[192]
    DIRECTION INPUT ;
    USE SIGNAL ;
    PORT
      LAYER M4 ;
        RECT  0 74.832 0.084 74.856 ;
    END
  END si[192]
  PIN si[193]
    DIRECTION INPUT ;
    USE SIGNAL ;
    PORT
      LAYER M4 ;
        RECT  0 74.928 0.084 74.952 ;
    END
  END si[193]
  PIN si[194]
    DIRECTION INPUT ;
    USE SIGNAL ;
    PORT
      LAYER M4 ;
        RECT  0 75.024 0.084 75.048 ;
    END
  END si[194]
  PIN si[195]
    DIRECTION INPUT ;
    USE SIGNAL ;
    PORT
      LAYER M4 ;
        RECT  0 97.392 0.084 97.416 ;
    END
  END si[195]
  PIN si[196]
    DIRECTION INPUT ;
    USE SIGNAL ;
    PORT
      LAYER M4 ;
        RECT  0 97.488 0.084 97.512 ;
    END
  END si[196]
  PIN si[197]
    DIRECTION INPUT ;
    USE SIGNAL ;
    PORT
      LAYER M4 ;
        RECT  0 97.584 0.084 97.608 ;
    END
  END si[197]
  PIN si[198]
    DIRECTION INPUT ;
    USE SIGNAL ;
    PORT
      LAYER M4 ;
        RECT  0 97.68 0.084 97.704 ;
    END
  END si[198]
  PIN si[199]
    DIRECTION INPUT ;
    USE SIGNAL ;
    PORT
      LAYER M4 ;
        RECT  0 97.776 0.084 97.8 ;
    END
  END si[199]
  PIN si[19]
    DIRECTION INPUT ;
    USE SIGNAL ;
    PORT
      LAYER M4 ;
        RECT  0 57.456 0.084 57.48 ;
    END
  END si[19]
  PIN si[1]
    DIRECTION INPUT ;
    USE SIGNAL ;
    PORT
      LAYER M4 ;
        RECT  0 55.728 0.084 55.752 ;
    END
  END si[1]
  PIN si[200]
    DIRECTION INPUT ;
    USE SIGNAL ;
    PORT
      LAYER M4 ;
        RECT  0 97.872 0.084 97.896 ;
    END
  END si[200]
  PIN si[201]
    DIRECTION INPUT ;
    USE SIGNAL ;
    PORT
      LAYER M4 ;
        RECT  0 97.968 0.084 97.992 ;
    END
  END si[201]
  PIN si[202]
    DIRECTION INPUT ;
    USE SIGNAL ;
    PORT
      LAYER M4 ;
        RECT  0 98.064 0.084 98.088 ;
    END
  END si[202]
  PIN si[203]
    DIRECTION INPUT ;
    USE SIGNAL ;
    PORT
      LAYER M4 ;
        RECT  0 98.16 0.084 98.184 ;
    END
  END si[203]
  PIN si[204]
    DIRECTION INPUT ;
    USE SIGNAL ;
    PORT
      LAYER M4 ;
        RECT  0 98.256 0.084 98.28 ;
    END
  END si[204]
  PIN si[205]
    DIRECTION INPUT ;
    USE SIGNAL ;
    PORT
      LAYER M4 ;
        RECT  0 98.352 0.084 98.376 ;
    END
  END si[205]
  PIN si[206]
    DIRECTION INPUT ;
    USE SIGNAL ;
    PORT
      LAYER M4 ;
        RECT  0 98.448 0.084 98.472 ;
    END
  END si[206]
  PIN si[207]
    DIRECTION INPUT ;
    USE SIGNAL ;
    PORT
      LAYER M4 ;
        RECT  0 98.544 0.084 98.568 ;
    END
  END si[207]
  PIN si[208]
    DIRECTION INPUT ;
    USE SIGNAL ;
    PORT
      LAYER M4 ;
        RECT  0 98.64 0.084 98.664 ;
    END
  END si[208]
  PIN si[209]
    DIRECTION INPUT ;
    USE SIGNAL ;
    PORT
      LAYER M4 ;
        RECT  0 98.736 0.084 98.76 ;
    END
  END si[209]
  PIN si[20]
    DIRECTION INPUT ;
    USE SIGNAL ;
    PORT
      LAYER M4 ;
        RECT  0 57.552 0.084 57.576 ;
    END
  END si[20]
  PIN si[210]
    DIRECTION INPUT ;
    USE SIGNAL ;
    PORT
      LAYER M4 ;
        RECT  0 98.832 0.084 98.856 ;
    END
  END si[210]
  PIN si[211]
    DIRECTION INPUT ;
    USE SIGNAL ;
    PORT
      LAYER M4 ;
        RECT  0 98.928 0.084 98.952 ;
    END
  END si[211]
  PIN si[212]
    DIRECTION INPUT ;
    USE SIGNAL ;
    PORT
      LAYER M4 ;
        RECT  0 99.024 0.084 99.048 ;
    END
  END si[212]
  PIN si[213]
    DIRECTION INPUT ;
    USE SIGNAL ;
    PORT
      LAYER M4 ;
        RECT  0 99.12 0.084 99.144 ;
    END
  END si[213]
  PIN si[214]
    DIRECTION INPUT ;
    USE SIGNAL ;
    PORT
      LAYER M4 ;
        RECT  0 99.216 0.084 99.24 ;
    END
  END si[214]
  PIN si[215]
    DIRECTION INPUT ;
    USE SIGNAL ;
    PORT
      LAYER M4 ;
        RECT  0 99.312 0.084 99.336 ;
    END
  END si[215]
  PIN si[216]
    DIRECTION INPUT ;
    USE SIGNAL ;
    PORT
      LAYER M4 ;
        RECT  0 99.408 0.084 99.432 ;
    END
  END si[216]
  PIN si[217]
    DIRECTION INPUT ;
    USE SIGNAL ;
    PORT
      LAYER M4 ;
        RECT  0 99.504 0.084 99.528 ;
    END
  END si[217]
  PIN si[218]
    DIRECTION INPUT ;
    USE SIGNAL ;
    PORT
      LAYER M4 ;
        RECT  0 99.6 0.084 99.624 ;
    END
  END si[218]
  PIN si[219]
    DIRECTION INPUT ;
    USE SIGNAL ;
    PORT
      LAYER M4 ;
        RECT  0 99.696 0.084 99.72 ;
    END
  END si[219]
  PIN si[21]
    DIRECTION INPUT ;
    USE SIGNAL ;
    PORT
      LAYER M4 ;
        RECT  0 57.648 0.084 57.672 ;
    END
  END si[21]
  PIN si[220]
    DIRECTION INPUT ;
    USE SIGNAL ;
    PORT
      LAYER M4 ;
        RECT  0 99.792 0.084 99.816 ;
    END
  END si[220]
  PIN si[221]
    DIRECTION INPUT ;
    USE SIGNAL ;
    PORT
      LAYER M4 ;
        RECT  0 99.888 0.084 99.912 ;
    END
  END si[221]
  PIN si[222]
    DIRECTION INPUT ;
    USE SIGNAL ;
    PORT
      LAYER M4 ;
        RECT  0 99.984 0.084 100.008 ;
    END
  END si[222]
  PIN si[223]
    DIRECTION INPUT ;
    USE SIGNAL ;
    PORT
      LAYER M4 ;
        RECT  0 100.08 0.084 100.104 ;
    END
  END si[223]
  PIN si[224]
    DIRECTION INPUT ;
    USE SIGNAL ;
    PORT
      LAYER M4 ;
        RECT  0 100.176 0.084 100.2 ;
    END
  END si[224]
  PIN si[225]
    DIRECTION INPUT ;
    USE SIGNAL ;
    PORT
      LAYER M4 ;
        RECT  0 100.272 0.084 100.296 ;
    END
  END si[225]
  PIN si[226]
    DIRECTION INPUT ;
    USE SIGNAL ;
    PORT
      LAYER M4 ;
        RECT  0 100.368 0.084 100.392 ;
    END
  END si[226]
  PIN si[227]
    DIRECTION INPUT ;
    USE SIGNAL ;
    PORT
      LAYER M4 ;
        RECT  0 106.608 0.084 106.632 ;
    END
  END si[227]
  PIN si[228]
    DIRECTION INPUT ;
    USE SIGNAL ;
    PORT
      LAYER M4 ;
        RECT  0 106.704 0.084 106.728 ;
    END
  END si[228]
  PIN si[229]
    DIRECTION INPUT ;
    USE SIGNAL ;
    PORT
      LAYER M4 ;
        RECT  0 106.8 0.084 106.824 ;
    END
  END si[229]
  PIN si[22]
    DIRECTION INPUT ;
    USE SIGNAL ;
    PORT
      LAYER M4 ;
        RECT  0 57.744 0.084 57.768 ;
    END
  END si[22]
  PIN si[230]
    DIRECTION INPUT ;
    USE SIGNAL ;
    PORT
      LAYER M4 ;
        RECT  0 106.896 0.084 106.92 ;
    END
  END si[230]
  PIN si[231]
    DIRECTION INPUT ;
    USE SIGNAL ;
    PORT
      LAYER M4 ;
        RECT  0 106.992 0.084 107.016 ;
    END
  END si[231]
  PIN si[232]
    DIRECTION INPUT ;
    USE SIGNAL ;
    PORT
      LAYER M4 ;
        RECT  0 107.088 0.084 107.112 ;
    END
  END si[232]
  PIN si[233]
    DIRECTION INPUT ;
    USE SIGNAL ;
    PORT
      LAYER M4 ;
        RECT  0 107.184 0.084 107.208 ;
    END
  END si[233]
  PIN si[234]
    DIRECTION INPUT ;
    USE SIGNAL ;
    PORT
      LAYER M4 ;
        RECT  0 107.28 0.084 107.304 ;
    END
  END si[234]
  PIN si[235]
    DIRECTION INPUT ;
    USE SIGNAL ;
    PORT
      LAYER M4 ;
        RECT  0 107.376 0.084 107.4 ;
    END
  END si[235]
  PIN si[236]
    DIRECTION INPUT ;
    USE SIGNAL ;
    PORT
      LAYER M4 ;
        RECT  0 107.472 0.084 107.496 ;
    END
  END si[236]
  PIN si[237]
    DIRECTION INPUT ;
    USE SIGNAL ;
    PORT
      LAYER M4 ;
        RECT  0 107.568 0.084 107.592 ;
    END
  END si[237]
  PIN si[238]
    DIRECTION INPUT ;
    USE SIGNAL ;
    PORT
      LAYER M4 ;
        RECT  0 107.664 0.084 107.688 ;
    END
  END si[238]
  PIN si[239]
    DIRECTION INPUT ;
    USE SIGNAL ;
    PORT
      LAYER M4 ;
        RECT  0 107.76 0.084 107.784 ;
    END
  END si[239]
  PIN si[23]
    DIRECTION INPUT ;
    USE SIGNAL ;
    PORT
      LAYER M4 ;
        RECT  0 57.84 0.084 57.864 ;
    END
  END si[23]
  PIN si[240]
    DIRECTION INPUT ;
    USE SIGNAL ;
    PORT
      LAYER M4 ;
        RECT  0 107.856 0.084 107.88 ;
    END
  END si[240]
  PIN si[241]
    DIRECTION INPUT ;
    USE SIGNAL ;
    PORT
      LAYER M4 ;
        RECT  0 107.952 0.084 107.976 ;
    END
  END si[241]
  PIN si[242]
    DIRECTION INPUT ;
    USE SIGNAL ;
    PORT
      LAYER M4 ;
        RECT  0 108.048 0.084 108.072 ;
    END
  END si[242]
  PIN si[243]
    DIRECTION INPUT ;
    USE SIGNAL ;
    PORT
      LAYER M4 ;
        RECT  0 108.144 0.084 108.168 ;
    END
  END si[243]
  PIN si[244]
    DIRECTION INPUT ;
    USE SIGNAL ;
    PORT
      LAYER M4 ;
        RECT  0 108.24 0.084 108.264 ;
    END
  END si[244]
  PIN si[245]
    DIRECTION INPUT ;
    USE SIGNAL ;
    PORT
      LAYER M4 ;
        RECT  0 108.336 0.084 108.36 ;
    END
  END si[245]
  PIN si[246]
    DIRECTION INPUT ;
    USE SIGNAL ;
    PORT
      LAYER M4 ;
        RECT  0 108.432 0.084 108.456 ;
    END
  END si[246]
  PIN si[247]
    DIRECTION INPUT ;
    USE SIGNAL ;
    PORT
      LAYER M4 ;
        RECT  0 108.528 0.084 108.552 ;
    END
  END si[247]
  PIN si[248]
    DIRECTION INPUT ;
    USE SIGNAL ;
    PORT
      LAYER M4 ;
        RECT  0 108.624 0.084 108.648 ;
    END
  END si[248]
  PIN si[249]
    DIRECTION INPUT ;
    USE SIGNAL ;
    PORT
      LAYER M4 ;
        RECT  0 108.72 0.084 108.744 ;
    END
  END si[249]
  PIN si[24]
    DIRECTION INPUT ;
    USE SIGNAL ;
    PORT
      LAYER M4 ;
        RECT  0 57.936 0.084 57.96 ;
    END
  END si[24]
  PIN si[250]
    DIRECTION INPUT ;
    USE SIGNAL ;
    PORT
      LAYER M4 ;
        RECT  0 108.816 0.084 108.84 ;
    END
  END si[250]
  PIN si[251]
    DIRECTION INPUT ;
    USE SIGNAL ;
    PORT
      LAYER M4 ;
        RECT  0 108.912 0.084 108.936 ;
    END
  END si[251]
  PIN si[252]
    DIRECTION INPUT ;
    USE SIGNAL ;
    PORT
      LAYER M4 ;
        RECT  0 109.008 0.084 109.032 ;
    END
  END si[252]
  PIN si[253]
    DIRECTION INPUT ;
    USE SIGNAL ;
    PORT
      LAYER M4 ;
        RECT  0 109.104 0.084 109.128 ;
    END
  END si[253]
  PIN si[254]
    DIRECTION INPUT ;
    USE SIGNAL ;
    PORT
      LAYER M4 ;
        RECT  0 109.2 0.084 109.224 ;
    END
  END si[254]
  PIN si[255]
    DIRECTION INPUT ;
    USE SIGNAL ;
    PORT
      LAYER M4 ;
        RECT  0 109.296 0.084 109.32 ;
    END
  END si[255]
  PIN si[256]
    DIRECTION INPUT ;
    USE SIGNAL ;
    PORT
      LAYER M4 ;
        RECT  0 109.392 0.084 109.416 ;
    END
  END si[256]
  PIN si[257]
    DIRECTION INPUT ;
    USE SIGNAL ;
    PORT
      LAYER M4 ;
        RECT  0 109.488 0.084 109.512 ;
    END
  END si[257]
  PIN si[258]
    DIRECTION INPUT ;
    USE SIGNAL ;
    PORT
      LAYER M4 ;
        RECT  0 109.584 0.084 109.608 ;
    END
  END si[258]
  PIN si[259]
    DIRECTION INPUT ;
    USE SIGNAL ;
    PORT
      LAYER M4 ;
        RECT  0 65.136 0.084 65.16 ;
    END
  END si[259]
  PIN si[25]
    DIRECTION INPUT ;
    USE SIGNAL ;
    PORT
      LAYER M4 ;
        RECT  0 58.032 0.084 58.056 ;
    END
  END si[25]
  PIN si[260]
    DIRECTION INPUT ;
    USE SIGNAL ;
    PORT
      LAYER M4 ;
        RECT  0 65.232 0.084 65.256 ;
    END
  END si[260]
  PIN si[261]
    DIRECTION INPUT ;
    USE SIGNAL ;
    PORT
      LAYER M4 ;
        RECT  0 65.328 0.084 65.352 ;
    END
  END si[261]
  PIN si[262]
    DIRECTION INPUT ;
    USE SIGNAL ;
    PORT
      LAYER M4 ;
        RECT  0 65.424 0.084 65.448 ;
    END
  END si[262]
  PIN si[263]
    DIRECTION INPUT ;
    USE SIGNAL ;
    PORT
      LAYER M4 ;
        RECT  0 65.52 0.084 65.544 ;
    END
  END si[263]
  PIN si[264]
    DIRECTION INPUT ;
    USE SIGNAL ;
    PORT
      LAYER M4 ;
        RECT  0 65.616 0.084 65.64 ;
    END
  END si[264]
  PIN si[265]
    DIRECTION INPUT ;
    USE SIGNAL ;
    PORT
      LAYER M4 ;
        RECT  0 65.712 0.084 65.736 ;
    END
  END si[265]
  PIN si[266]
    DIRECTION INPUT ;
    USE SIGNAL ;
    PORT
      LAYER M4 ;
        RECT  0 65.808 0.084 65.832 ;
    END
  END si[266]
  PIN si[267]
    DIRECTION INPUT ;
    USE SIGNAL ;
    PORT
      LAYER M4 ;
        RECT  0 65.904 0.084 65.928 ;
    END
  END si[267]
  PIN si[268]
    DIRECTION INPUT ;
    USE SIGNAL ;
    PORT
      LAYER M4 ;
        RECT  0 66 0.084 66.024 ;
    END
  END si[268]
  PIN si[269]
    DIRECTION INPUT ;
    USE SIGNAL ;
    PORT
      LAYER M4 ;
        RECT  0 66.096 0.084 66.12 ;
    END
  END si[269]
  PIN si[26]
    DIRECTION INPUT ;
    USE SIGNAL ;
    PORT
      LAYER M4 ;
        RECT  0 58.128 0.084 58.152 ;
    END
  END si[26]
  PIN si[270]
    DIRECTION INPUT ;
    USE SIGNAL ;
    PORT
      LAYER M4 ;
        RECT  0 66.192 0.084 66.216 ;
    END
  END si[270]
  PIN si[271]
    DIRECTION INPUT ;
    USE SIGNAL ;
    PORT
      LAYER M4 ;
        RECT  0 66.288 0.084 66.312 ;
    END
  END si[271]
  PIN si[272]
    DIRECTION INPUT ;
    USE SIGNAL ;
    PORT
      LAYER M4 ;
        RECT  0 66.384 0.084 66.408 ;
    END
  END si[272]
  PIN si[273]
    DIRECTION INPUT ;
    USE SIGNAL ;
    PORT
      LAYER M4 ;
        RECT  0 66.48 0.084 66.504 ;
    END
  END si[273]
  PIN si[274]
    DIRECTION INPUT ;
    USE SIGNAL ;
    PORT
      LAYER M4 ;
        RECT  0 66.576 0.084 66.6 ;
    END
  END si[274]
  PIN si[275]
    DIRECTION INPUT ;
    USE SIGNAL ;
    PORT
      LAYER M4 ;
        RECT  0 66.672 0.084 66.696 ;
    END
  END si[275]
  PIN si[276]
    DIRECTION INPUT ;
    USE SIGNAL ;
    PORT
      LAYER M4 ;
        RECT  0 66.768 0.084 66.792 ;
    END
  END si[276]
  PIN si[277]
    DIRECTION INPUT ;
    USE SIGNAL ;
    PORT
      LAYER M4 ;
        RECT  0 66.864 0.084 66.888 ;
    END
  END si[277]
  PIN si[278]
    DIRECTION INPUT ;
    USE SIGNAL ;
    PORT
      LAYER M4 ;
        RECT  0 66.96 0.084 66.984 ;
    END
  END si[278]
  PIN si[279]
    DIRECTION INPUT ;
    USE SIGNAL ;
    PORT
      LAYER M4 ;
        RECT  0 67.056 0.084 67.08 ;
    END
  END si[279]
  PIN si[27]
    DIRECTION INPUT ;
    USE SIGNAL ;
    PORT
      LAYER M4 ;
        RECT  0 58.224 0.084 58.248 ;
    END
  END si[27]
  PIN si[280]
    DIRECTION INPUT ;
    USE SIGNAL ;
    PORT
      LAYER M4 ;
        RECT  0 67.152 0.084 67.176 ;
    END
  END si[280]
  PIN si[281]
    DIRECTION INPUT ;
    USE SIGNAL ;
    PORT
      LAYER M4 ;
        RECT  0 67.248 0.084 67.272 ;
    END
  END si[281]
  PIN si[282]
    DIRECTION INPUT ;
    USE SIGNAL ;
    PORT
      LAYER M4 ;
        RECT  0 67.344 0.084 67.368 ;
    END
  END si[282]
  PIN si[283]
    DIRECTION INPUT ;
    USE SIGNAL ;
    PORT
      LAYER M4 ;
        RECT  0 67.44 0.084 67.464 ;
    END
  END si[283]
  PIN si[284]
    DIRECTION INPUT ;
    USE SIGNAL ;
    PORT
      LAYER M4 ;
        RECT  0 67.536 0.084 67.56 ;
    END
  END si[284]
  PIN si[285]
    DIRECTION INPUT ;
    USE SIGNAL ;
    PORT
      LAYER M4 ;
        RECT  0 67.632 0.084 67.656 ;
    END
  END si[285]
  PIN si[286]
    DIRECTION INPUT ;
    USE SIGNAL ;
    PORT
      LAYER M4 ;
        RECT  0 67.728 0.084 67.752 ;
    END
  END si[286]
  PIN si[287]
    DIRECTION INPUT ;
    USE SIGNAL ;
    PORT
      LAYER M4 ;
        RECT  0 67.824 0.084 67.848 ;
    END
  END si[287]
  PIN si[288]
    DIRECTION INPUT ;
    USE SIGNAL ;
    PORT
      LAYER M4 ;
        RECT  0 67.92 0.084 67.944 ;
    END
  END si[288]
  PIN si[289]
    DIRECTION INPUT ;
    USE SIGNAL ;
    PORT
      LAYER M4 ;
        RECT  0 68.016 0.084 68.04 ;
    END
  END si[289]
  PIN si[28]
    DIRECTION INPUT ;
    USE SIGNAL ;
    PORT
      LAYER M4 ;
        RECT  0 58.32 0.084 58.344 ;
    END
  END si[28]
  PIN si[290]
    DIRECTION INPUT ;
    USE SIGNAL ;
    PORT
      LAYER M4 ;
        RECT  0 68.112 0.084 68.136 ;
    END
  END si[290]
  PIN si[291]
    DIRECTION INPUT ;
    USE SIGNAL ;
    PORT
      LAYER M4 ;
        RECT  0 68.208 0.084 68.232 ;
    END
  END si[291]
  PIN si[292]
    DIRECTION INPUT ;
    USE SIGNAL ;
    PORT
      LAYER M4 ;
        RECT  0 68.304 0.084 68.328 ;
    END
  END si[292]
  PIN si[293]
    DIRECTION INPUT ;
    USE SIGNAL ;
    PORT
      LAYER M4 ;
        RECT  0 68.4 0.084 68.424 ;
    END
  END si[293]
  PIN si[294]
    DIRECTION INPUT ;
    USE SIGNAL ;
    PORT
      LAYER M4 ;
        RECT  0 68.496 0.084 68.52 ;
    END
  END si[294]
  PIN si[295]
    DIRECTION INPUT ;
    USE SIGNAL ;
    PORT
      LAYER M4 ;
        RECT  0 68.592 0.084 68.616 ;
    END
  END si[295]
  PIN si[296]
    DIRECTION INPUT ;
    USE SIGNAL ;
    PORT
      LAYER M4 ;
        RECT  0 68.688 0.084 68.712 ;
    END
  END si[296]
  PIN si[297]
    DIRECTION INPUT ;
    USE SIGNAL ;
    PORT
      LAYER M4 ;
        RECT  0 68.784 0.084 68.808 ;
    END
  END si[297]
  PIN si[298]
    DIRECTION INPUT ;
    USE SIGNAL ;
    PORT
      LAYER M4 ;
        RECT  0 68.88 0.084 68.904 ;
    END
  END si[298]
  PIN si[299]
    DIRECTION INPUT ;
    USE SIGNAL ;
    PORT
      LAYER M4 ;
        RECT  0 68.976 0.084 69 ;
    END
  END si[299]
  PIN si[29]
    DIRECTION INPUT ;
    USE SIGNAL ;
    PORT
      LAYER M4 ;
        RECT  0 58.416 0.084 58.44 ;
    END
  END si[29]
  PIN si[2]
    DIRECTION INPUT ;
    USE SIGNAL ;
    PORT
      LAYER M4 ;
        RECT  0 55.824 0.084 55.848 ;
    END
  END si[2]
  PIN si[300]
    DIRECTION INPUT ;
    USE SIGNAL ;
    PORT
      LAYER M4 ;
        RECT  0 69.072 0.084 69.096 ;
    END
  END si[300]
  PIN si[301]
    DIRECTION INPUT ;
    USE SIGNAL ;
    PORT
      LAYER M4 ;
        RECT  0 69.168 0.084 69.192 ;
    END
  END si[301]
  PIN si[302]
    DIRECTION INPUT ;
    USE SIGNAL ;
    PORT
      LAYER M4 ;
        RECT  0 69.264 0.084 69.288 ;
    END
  END si[302]
  PIN si[303]
    DIRECTION INPUT ;
    USE SIGNAL ;
    PORT
      LAYER M4 ;
        RECT  0 69.36 0.084 69.384 ;
    END
  END si[303]
  PIN si[304]
    DIRECTION INPUT ;
    USE SIGNAL ;
    PORT
      LAYER M4 ;
        RECT  0 69.456 0.084 69.48 ;
    END
  END si[304]
  PIN si[305]
    DIRECTION INPUT ;
    USE SIGNAL ;
    PORT
      LAYER M4 ;
        RECT  0 69.552 0.084 69.576 ;
    END
  END si[305]
  PIN si[306]
    DIRECTION INPUT ;
    USE SIGNAL ;
    PORT
      LAYER M4 ;
        RECT  0 69.648 0.084 69.672 ;
    END
  END si[306]
  PIN si[307]
    DIRECTION INPUT ;
    USE SIGNAL ;
    PORT
      LAYER M4 ;
        RECT  0 69.744 0.084 69.768 ;
    END
  END si[307]
  PIN si[308]
    DIRECTION INPUT ;
    USE SIGNAL ;
    PORT
      LAYER M4 ;
        RECT  0 69.84 0.084 69.864 ;
    END
  END si[308]
  PIN si[309]
    DIRECTION INPUT ;
    USE SIGNAL ;
    PORT
      LAYER M4 ;
        RECT  0 69.936 0.084 69.96 ;
    END
  END si[309]
  PIN si[30]
    DIRECTION INPUT ;
    USE SIGNAL ;
    PORT
      LAYER M4 ;
        RECT  0 58.512 0.084 58.536 ;
    END
  END si[30]
  PIN si[310]
    DIRECTION INPUT ;
    USE SIGNAL ;
    PORT
      LAYER M4 ;
        RECT  0 70.032 0.084 70.056 ;
    END
  END si[310]
  PIN si[311]
    DIRECTION INPUT ;
    USE SIGNAL ;
    PORT
      LAYER M4 ;
        RECT  0 70.128 0.084 70.152 ;
    END
  END si[311]
  PIN si[312]
    DIRECTION INPUT ;
    USE SIGNAL ;
    PORT
      LAYER M4 ;
        RECT  0 70.224 0.084 70.248 ;
    END
  END si[312]
  PIN si[313]
    DIRECTION INPUT ;
    USE SIGNAL ;
    PORT
      LAYER M4 ;
        RECT  0 70.32 0.084 70.344 ;
    END
  END si[313]
  PIN si[314]
    DIRECTION INPUT ;
    USE SIGNAL ;
    PORT
      LAYER M4 ;
        RECT  0 70.416 0.084 70.44 ;
    END
  END si[314]
  PIN si[315]
    DIRECTION INPUT ;
    USE SIGNAL ;
    PORT
      LAYER M4 ;
        RECT  0 70.512 0.084 70.536 ;
    END
  END si[315]
  PIN si[316]
    DIRECTION INPUT ;
    USE SIGNAL ;
    PORT
      LAYER M4 ;
        RECT  0 70.608 0.084 70.632 ;
    END
  END si[316]
  PIN si[317]
    DIRECTION INPUT ;
    USE SIGNAL ;
    PORT
      LAYER M4 ;
        RECT  0 70.704 0.084 70.728 ;
    END
  END si[317]
  PIN si[318]
    DIRECTION INPUT ;
    USE SIGNAL ;
    PORT
      LAYER M4 ;
        RECT  0 70.8 0.084 70.824 ;
    END
  END si[318]
  PIN si[319]
    DIRECTION INPUT ;
    USE SIGNAL ;
    PORT
      LAYER M4 ;
        RECT  0 70.896 0.084 70.92 ;
    END
  END si[319]
  PIN si[31]
    DIRECTION INPUT ;
    USE SIGNAL ;
    PORT
      LAYER M4 ;
        RECT  0 58.608 0.084 58.632 ;
    END
  END si[31]
  PIN si[320]
    DIRECTION INPUT ;
    USE SIGNAL ;
    PORT
      LAYER M4 ;
        RECT  0 70.992 0.084 71.016 ;
    END
  END si[320]
  PIN si[321]
    DIRECTION INPUT ;
    USE SIGNAL ;
    PORT
      LAYER M4 ;
        RECT  0 71.088 0.084 71.112 ;
    END
  END si[321]
  PIN si[322]
    DIRECTION INPUT ;
    USE SIGNAL ;
    PORT
      LAYER M4 ;
        RECT  0 71.184 0.084 71.208 ;
    END
  END si[322]
  PIN si[323]
    DIRECTION INPUT ;
    USE SIGNAL ;
    PORT
      LAYER M4 ;
        RECT  0 49.008 0.084 49.032 ;
    END
  END si[323]
  PIN si[324]
    DIRECTION INPUT ;
    USE SIGNAL ;
    PORT
      LAYER M4 ;
        RECT  0 49.104 0.084 49.128 ;
    END
  END si[324]
  PIN si[325]
    DIRECTION INPUT ;
    USE SIGNAL ;
    PORT
      LAYER M4 ;
        RECT  0 49.2 0.084 49.224 ;
    END
  END si[325]
  PIN si[326]
    DIRECTION INPUT ;
    USE SIGNAL ;
    PORT
      LAYER M4 ;
        RECT  0 49.296 0.084 49.32 ;
    END
  END si[326]
  PIN si[327]
    DIRECTION INPUT ;
    USE SIGNAL ;
    PORT
      LAYER M4 ;
        RECT  0 49.392 0.084 49.416 ;
    END
  END si[327]
  PIN si[328]
    DIRECTION INPUT ;
    USE SIGNAL ;
    PORT
      LAYER M4 ;
        RECT  0 49.488 0.084 49.512 ;
    END
  END si[328]
  PIN si[329]
    DIRECTION INPUT ;
    USE SIGNAL ;
    PORT
      LAYER M4 ;
        RECT  0 49.584 0.084 49.608 ;
    END
  END si[329]
  PIN si[32]
    DIRECTION INPUT ;
    USE SIGNAL ;
    PORT
      LAYER M4 ;
        RECT  0 58.704 0.084 58.728 ;
    END
  END si[32]
  PIN si[330]
    DIRECTION INPUT ;
    USE SIGNAL ;
    PORT
      LAYER M4 ;
        RECT  0 49.68 0.084 49.704 ;
    END
  END si[330]
  PIN si[331]
    DIRECTION INPUT ;
    USE SIGNAL ;
    PORT
      LAYER M4 ;
        RECT  0 49.776 0.084 49.8 ;
    END
  END si[331]
  PIN si[332]
    DIRECTION INPUT ;
    USE SIGNAL ;
    PORT
      LAYER M4 ;
        RECT  0 49.872 0.084 49.896 ;
    END
  END si[332]
  PIN si[333]
    DIRECTION INPUT ;
    USE SIGNAL ;
    PORT
      LAYER M4 ;
        RECT  0 49.968 0.084 49.992 ;
    END
  END si[333]
  PIN si[334]
    DIRECTION INPUT ;
    USE SIGNAL ;
    PORT
      LAYER M4 ;
        RECT  0 50.064 0.084 50.088 ;
    END
  END si[334]
  PIN si[335]
    DIRECTION INPUT ;
    USE SIGNAL ;
    PORT
      LAYER M4 ;
        RECT  0 50.16 0.084 50.184 ;
    END
  END si[335]
  PIN si[336]
    DIRECTION INPUT ;
    USE SIGNAL ;
    PORT
      LAYER M4 ;
        RECT  0 50.256 0.084 50.28 ;
    END
  END si[336]
  PIN si[337]
    DIRECTION INPUT ;
    USE SIGNAL ;
    PORT
      LAYER M4 ;
        RECT  0 50.352 0.084 50.376 ;
    END
  END si[337]
  PIN si[338]
    DIRECTION INPUT ;
    USE SIGNAL ;
    PORT
      LAYER M4 ;
        RECT  0 50.448 0.084 50.472 ;
    END
  END si[338]
  PIN si[339]
    DIRECTION INPUT ;
    USE SIGNAL ;
    PORT
      LAYER M4 ;
        RECT  0 50.544 0.084 50.568 ;
    END
  END si[339]
  PIN si[33]
    DIRECTION INPUT ;
    USE SIGNAL ;
    PORT
      LAYER M4 ;
        RECT  0 58.8 0.084 58.824 ;
    END
  END si[33]
  PIN si[340]
    DIRECTION INPUT ;
    USE SIGNAL ;
    PORT
      LAYER M4 ;
        RECT  0 50.64 0.084 50.664 ;
    END
  END si[340]
  PIN si[341]
    DIRECTION INPUT ;
    USE SIGNAL ;
    PORT
      LAYER M4 ;
        RECT  0 50.736 0.084 50.76 ;
    END
  END si[341]
  PIN si[342]
    DIRECTION INPUT ;
    USE SIGNAL ;
    PORT
      LAYER M4 ;
        RECT  0 50.832 0.084 50.856 ;
    END
  END si[342]
  PIN si[343]
    DIRECTION INPUT ;
    USE SIGNAL ;
    PORT
      LAYER M4 ;
        RECT  0 50.928 0.084 50.952 ;
    END
  END si[343]
  PIN si[344]
    DIRECTION INPUT ;
    USE SIGNAL ;
    PORT
      LAYER M4 ;
        RECT  0 51.024 0.084 51.048 ;
    END
  END si[344]
  PIN si[345]
    DIRECTION INPUT ;
    USE SIGNAL ;
    PORT
      LAYER M4 ;
        RECT  0 51.12 0.084 51.144 ;
    END
  END si[345]
  PIN si[346]
    DIRECTION INPUT ;
    USE SIGNAL ;
    PORT
      LAYER M4 ;
        RECT  0 51.216 0.084 51.24 ;
    END
  END si[346]
  PIN si[347]
    DIRECTION INPUT ;
    USE SIGNAL ;
    PORT
      LAYER M4 ;
        RECT  0 51.312 0.084 51.336 ;
    END
  END si[347]
  PIN si[348]
    DIRECTION INPUT ;
    USE SIGNAL ;
    PORT
      LAYER M4 ;
        RECT  0 51.408 0.084 51.432 ;
    END
  END si[348]
  PIN si[349]
    DIRECTION INPUT ;
    USE SIGNAL ;
    PORT
      LAYER M4 ;
        RECT  0 51.504 0.084 51.528 ;
    END
  END si[349]
  PIN si[34]
    DIRECTION INPUT ;
    USE SIGNAL ;
    PORT
      LAYER M4 ;
        RECT  0 58.896 0.084 58.92 ;
    END
  END si[34]
  PIN si[350]
    DIRECTION INPUT ;
    USE SIGNAL ;
    PORT
      LAYER M4 ;
        RECT  0 51.6 0.084 51.624 ;
    END
  END si[350]
  PIN si[351]
    DIRECTION INPUT ;
    USE SIGNAL ;
    PORT
      LAYER M4 ;
        RECT  0 51.696 0.084 51.72 ;
    END
  END si[351]
  PIN si[352]
    DIRECTION INPUT ;
    USE SIGNAL ;
    PORT
      LAYER M4 ;
        RECT  0 51.792 0.084 51.816 ;
    END
  END si[352]
  PIN si[353]
    DIRECTION INPUT ;
    USE SIGNAL ;
    PORT
      LAYER M4 ;
        RECT  0 51.888 0.084 51.912 ;
    END
  END si[353]
  PIN si[354]
    DIRECTION INPUT ;
    USE SIGNAL ;
    PORT
      LAYER M4 ;
        RECT  0 51.984 0.084 52.008 ;
    END
  END si[354]
  PIN si[355]
    DIRECTION INPUT ;
    USE SIGNAL ;
    PORT
      LAYER M4 ;
        RECT  0 45.936 0.084 45.96 ;
    END
  END si[355]
  PIN si[356]
    DIRECTION INPUT ;
    USE SIGNAL ;
    PORT
      LAYER M4 ;
        RECT  0 46.032 0.084 46.056 ;
    END
  END si[356]
  PIN si[357]
    DIRECTION INPUT ;
    USE SIGNAL ;
    PORT
      LAYER M4 ;
        RECT  0 46.128 0.084 46.152 ;
    END
  END si[357]
  PIN si[358]
    DIRECTION INPUT ;
    USE SIGNAL ;
    PORT
      LAYER M4 ;
        RECT  0 46.224 0.084 46.248 ;
    END
  END si[358]
  PIN si[359]
    DIRECTION INPUT ;
    USE SIGNAL ;
    PORT
      LAYER M4 ;
        RECT  0 46.32 0.084 46.344 ;
    END
  END si[359]
  PIN si[35]
    DIRECTION INPUT ;
    USE SIGNAL ;
    PORT
      LAYER M4 ;
        RECT  0 36.72 0.084 36.744 ;
    END
  END si[35]
  PIN si[360]
    DIRECTION INPUT ;
    USE SIGNAL ;
    PORT
      LAYER M4 ;
        RECT  0 46.416 0.084 46.44 ;
    END
  END si[360]
  PIN si[361]
    DIRECTION INPUT ;
    USE SIGNAL ;
    PORT
      LAYER M4 ;
        RECT  0 46.512 0.084 46.536 ;
    END
  END si[361]
  PIN si[362]
    DIRECTION INPUT ;
    USE SIGNAL ;
    PORT
      LAYER M4 ;
        RECT  0 46.608 0.084 46.632 ;
    END
  END si[362]
  PIN si[363]
    DIRECTION INPUT ;
    USE SIGNAL ;
    PORT
      LAYER M4 ;
        RECT  0 46.704 0.084 46.728 ;
    END
  END si[363]
  PIN si[364]
    DIRECTION INPUT ;
    USE SIGNAL ;
    PORT
      LAYER M4 ;
        RECT  0 46.8 0.084 46.824 ;
    END
  END si[364]
  PIN si[365]
    DIRECTION INPUT ;
    USE SIGNAL ;
    PORT
      LAYER M4 ;
        RECT  0 46.896 0.084 46.92 ;
    END
  END si[365]
  PIN si[366]
    DIRECTION INPUT ;
    USE SIGNAL ;
    PORT
      LAYER M4 ;
        RECT  0 46.992 0.084 47.016 ;
    END
  END si[366]
  PIN si[367]
    DIRECTION INPUT ;
    USE SIGNAL ;
    PORT
      LAYER M4 ;
        RECT  0 47.088 0.084 47.112 ;
    END
  END si[367]
  PIN si[368]
    DIRECTION INPUT ;
    USE SIGNAL ;
    PORT
      LAYER M4 ;
        RECT  0 47.184 0.084 47.208 ;
    END
  END si[368]
  PIN si[369]
    DIRECTION INPUT ;
    USE SIGNAL ;
    PORT
      LAYER M4 ;
        RECT  0 47.28 0.084 47.304 ;
    END
  END si[369]
  PIN si[36]
    DIRECTION INPUT ;
    USE SIGNAL ;
    PORT
      LAYER M4 ;
        RECT  0 36.816 0.084 36.84 ;
    END
  END si[36]
  PIN si[370]
    DIRECTION INPUT ;
    USE SIGNAL ;
    PORT
      LAYER M4 ;
        RECT  0 47.376 0.084 47.4 ;
    END
  END si[370]
  PIN si[371]
    DIRECTION INPUT ;
    USE SIGNAL ;
    PORT
      LAYER M4 ;
        RECT  0 47.472 0.084 47.496 ;
    END
  END si[371]
  PIN si[372]
    DIRECTION INPUT ;
    USE SIGNAL ;
    PORT
      LAYER M4 ;
        RECT  0 47.568 0.084 47.592 ;
    END
  END si[372]
  PIN si[373]
    DIRECTION INPUT ;
    USE SIGNAL ;
    PORT
      LAYER M4 ;
        RECT  0 47.664 0.084 47.688 ;
    END
  END si[373]
  PIN si[374]
    DIRECTION INPUT ;
    USE SIGNAL ;
    PORT
      LAYER M4 ;
        RECT  0 47.76 0.084 47.784 ;
    END
  END si[374]
  PIN si[375]
    DIRECTION INPUT ;
    USE SIGNAL ;
    PORT
      LAYER M4 ;
        RECT  0 47.856 0.084 47.88 ;
    END
  END si[375]
  PIN si[376]
    DIRECTION INPUT ;
    USE SIGNAL ;
    PORT
      LAYER M4 ;
        RECT  0 47.952 0.084 47.976 ;
    END
  END si[376]
  PIN si[377]
    DIRECTION INPUT ;
    USE SIGNAL ;
    PORT
      LAYER M4 ;
        RECT  0 48.048 0.084 48.072 ;
    END
  END si[377]
  PIN si[378]
    DIRECTION INPUT ;
    USE SIGNAL ;
    PORT
      LAYER M4 ;
        RECT  0 48.144 0.084 48.168 ;
    END
  END si[378]
  PIN si[379]
    DIRECTION INPUT ;
    USE SIGNAL ;
    PORT
      LAYER M4 ;
        RECT  0 48.24 0.084 48.264 ;
    END
  END si[379]
  PIN si[37]
    DIRECTION INPUT ;
    USE SIGNAL ;
    PORT
      LAYER M4 ;
        RECT  0 36.912 0.084 36.936 ;
    END
  END si[37]
  PIN si[380]
    DIRECTION INPUT ;
    USE SIGNAL ;
    PORT
      LAYER M4 ;
        RECT  0 48.336 0.084 48.36 ;
    END
  END si[380]
  PIN si[381]
    DIRECTION INPUT ;
    USE SIGNAL ;
    PORT
      LAYER M4 ;
        RECT  0 48.432 0.084 48.456 ;
    END
  END si[381]
  PIN si[382]
    DIRECTION INPUT ;
    USE SIGNAL ;
    PORT
      LAYER M4 ;
        RECT  0 48.528 0.084 48.552 ;
    END
  END si[382]
  PIN si[383]
    DIRECTION INPUT ;
    USE SIGNAL ;
    PORT
      LAYER M4 ;
        RECT  0 48.624 0.084 48.648 ;
    END
  END si[383]
  PIN si[384]
    DIRECTION INPUT ;
    USE SIGNAL ;
    PORT
      LAYER M4 ;
        RECT  0 48.72 0.084 48.744 ;
    END
  END si[384]
  PIN si[385]
    DIRECTION INPUT ;
    USE SIGNAL ;
    PORT
      LAYER M4 ;
        RECT  0 48.816 0.084 48.84 ;
    END
  END si[385]
  PIN si[386]
    DIRECTION INPUT ;
    USE SIGNAL ;
    PORT
      LAYER M4 ;
        RECT  0 48.912 0.084 48.936 ;
    END
  END si[386]
  PIN si[387]
    DIRECTION INPUT ;
    USE SIGNAL ;
    PORT
      LAYER M4 ;
        RECT  0 39.792 0.084 39.816 ;
    END
  END si[387]
  PIN si[388]
    DIRECTION INPUT ;
    USE SIGNAL ;
    PORT
      LAYER M4 ;
        RECT  0 39.888 0.084 39.912 ;
    END
  END si[388]
  PIN si[389]
    DIRECTION INPUT ;
    USE SIGNAL ;
    PORT
      LAYER M4 ;
        RECT  0 39.984 0.084 40.008 ;
    END
  END si[389]
  PIN si[38]
    DIRECTION INPUT ;
    USE SIGNAL ;
    PORT
      LAYER M4 ;
        RECT  0 37.008 0.084 37.032 ;
    END
  END si[38]
  PIN si[390]
    DIRECTION INPUT ;
    USE SIGNAL ;
    PORT
      LAYER M4 ;
        RECT  0 40.08 0.084 40.104 ;
    END
  END si[390]
  PIN si[391]
    DIRECTION INPUT ;
    USE SIGNAL ;
    PORT
      LAYER M4 ;
        RECT  0 40.176 0.084 40.2 ;
    END
  END si[391]
  PIN si[392]
    DIRECTION INPUT ;
    USE SIGNAL ;
    PORT
      LAYER M4 ;
        RECT  0 40.272 0.084 40.296 ;
    END
  END si[392]
  PIN si[393]
    DIRECTION INPUT ;
    USE SIGNAL ;
    PORT
      LAYER M4 ;
        RECT  0 40.368 0.084 40.392 ;
    END
  END si[393]
  PIN si[394]
    DIRECTION INPUT ;
    USE SIGNAL ;
    PORT
      LAYER M4 ;
        RECT  0 40.464 0.084 40.488 ;
    END
  END si[394]
  PIN si[395]
    DIRECTION INPUT ;
    USE SIGNAL ;
    PORT
      LAYER M4 ;
        RECT  0 40.56 0.084 40.584 ;
    END
  END si[395]
  PIN si[396]
    DIRECTION INPUT ;
    USE SIGNAL ;
    PORT
      LAYER M4 ;
        RECT  0 40.656 0.084 40.68 ;
    END
  END si[396]
  PIN si[397]
    DIRECTION INPUT ;
    USE SIGNAL ;
    PORT
      LAYER M4 ;
        RECT  0 40.752 0.084 40.776 ;
    END
  END si[397]
  PIN si[398]
    DIRECTION INPUT ;
    USE SIGNAL ;
    PORT
      LAYER M4 ;
        RECT  0 40.848 0.084 40.872 ;
    END
  END si[398]
  PIN si[399]
    DIRECTION INPUT ;
    USE SIGNAL ;
    PORT
      LAYER M4 ;
        RECT  0 40.944 0.084 40.968 ;
    END
  END si[399]
  PIN si[39]
    DIRECTION INPUT ;
    USE SIGNAL ;
    PORT
      LAYER M4 ;
        RECT  0 37.104 0.084 37.128 ;
    END
  END si[39]
  PIN si[3]
    DIRECTION INPUT ;
    USE SIGNAL ;
    PORT
      LAYER M4 ;
        RECT  0 55.92 0.084 55.944 ;
    END
  END si[3]
  PIN si[400]
    DIRECTION INPUT ;
    USE SIGNAL ;
    PORT
      LAYER M4 ;
        RECT  0 41.04 0.084 41.064 ;
    END
  END si[400]
  PIN si[401]
    DIRECTION INPUT ;
    USE SIGNAL ;
    PORT
      LAYER M4 ;
        RECT  0 41.136 0.084 41.16 ;
    END
  END si[401]
  PIN si[402]
    DIRECTION INPUT ;
    USE SIGNAL ;
    PORT
      LAYER M4 ;
        RECT  0 41.232 0.084 41.256 ;
    END
  END si[402]
  PIN si[403]
    DIRECTION INPUT ;
    USE SIGNAL ;
    PORT
      LAYER M4 ;
        RECT  0 41.328 0.084 41.352 ;
    END
  END si[403]
  PIN si[404]
    DIRECTION INPUT ;
    USE SIGNAL ;
    PORT
      LAYER M4 ;
        RECT  0 41.424 0.084 41.448 ;
    END
  END si[404]
  PIN si[405]
    DIRECTION INPUT ;
    USE SIGNAL ;
    PORT
      LAYER M4 ;
        RECT  0 41.52 0.084 41.544 ;
    END
  END si[405]
  PIN si[406]
    DIRECTION INPUT ;
    USE SIGNAL ;
    PORT
      LAYER M4 ;
        RECT  0 41.616 0.084 41.64 ;
    END
  END si[406]
  PIN si[407]
    DIRECTION INPUT ;
    USE SIGNAL ;
    PORT
      LAYER M4 ;
        RECT  0 41.712 0.084 41.736 ;
    END
  END si[407]
  PIN si[408]
    DIRECTION INPUT ;
    USE SIGNAL ;
    PORT
      LAYER M4 ;
        RECT  0 41.808 0.084 41.832 ;
    END
  END si[408]
  PIN si[409]
    DIRECTION INPUT ;
    USE SIGNAL ;
    PORT
      LAYER M4 ;
        RECT  0 41.904 0.084 41.928 ;
    END
  END si[409]
  PIN si[40]
    DIRECTION INPUT ;
    USE SIGNAL ;
    PORT
      LAYER M4 ;
        RECT  0 37.2 0.084 37.224 ;
    END
  END si[40]
  PIN si[410]
    DIRECTION INPUT ;
    USE SIGNAL ;
    PORT
      LAYER M4 ;
        RECT  0 42 0.084 42.024 ;
    END
  END si[410]
  PIN si[411]
    DIRECTION INPUT ;
    USE SIGNAL ;
    PORT
      LAYER M4 ;
        RECT  0 42.096 0.084 42.12 ;
    END
  END si[411]
  PIN si[412]
    DIRECTION INPUT ;
    USE SIGNAL ;
    PORT
      LAYER M4 ;
        RECT  0 42.192 0.084 42.216 ;
    END
  END si[412]
  PIN si[413]
    DIRECTION INPUT ;
    USE SIGNAL ;
    PORT
      LAYER M4 ;
        RECT  0 42.288 0.084 42.312 ;
    END
  END si[413]
  PIN si[414]
    DIRECTION INPUT ;
    USE SIGNAL ;
    PORT
      LAYER M4 ;
        RECT  0 42.384 0.084 42.408 ;
    END
  END si[414]
  PIN si[415]
    DIRECTION INPUT ;
    USE SIGNAL ;
    PORT
      LAYER M4 ;
        RECT  0 42.48 0.084 42.504 ;
    END
  END si[415]
  PIN si[416]
    DIRECTION INPUT ;
    USE SIGNAL ;
    PORT
      LAYER M4 ;
        RECT  0 42.576 0.084 42.6 ;
    END
  END si[416]
  PIN si[417]
    DIRECTION INPUT ;
    USE SIGNAL ;
    PORT
      LAYER M4 ;
        RECT  0 42.672 0.084 42.696 ;
    END
  END si[417]
  PIN si[418]
    DIRECTION INPUT ;
    USE SIGNAL ;
    PORT
      LAYER M4 ;
        RECT  0 42.768 0.084 42.792 ;
    END
  END si[418]
  PIN si[419]
    DIRECTION INPUT ;
    USE SIGNAL ;
    PORT
      LAYER M4 ;
        RECT  0 42.864 0.084 42.888 ;
    END
  END si[419]
  PIN si[41]
    DIRECTION INPUT ;
    USE SIGNAL ;
    PORT
      LAYER M4 ;
        RECT  0 37.296 0.084 37.32 ;
    END
  END si[41]
  PIN si[420]
    DIRECTION INPUT ;
    USE SIGNAL ;
    PORT
      LAYER M4 ;
        RECT  0 42.96 0.084 42.984 ;
    END
  END si[420]
  PIN si[421]
    DIRECTION INPUT ;
    USE SIGNAL ;
    PORT
      LAYER M4 ;
        RECT  0 43.056 0.084 43.08 ;
    END
  END si[421]
  PIN si[422]
    DIRECTION INPUT ;
    USE SIGNAL ;
    PORT
      LAYER M4 ;
        RECT  0 43.152 0.084 43.176 ;
    END
  END si[422]
  PIN si[423]
    DIRECTION INPUT ;
    USE SIGNAL ;
    PORT
      LAYER M4 ;
        RECT  0 43.248 0.084 43.272 ;
    END
  END si[423]
  PIN si[424]
    DIRECTION INPUT ;
    USE SIGNAL ;
    PORT
      LAYER M4 ;
        RECT  0 43.344 0.084 43.368 ;
    END
  END si[424]
  PIN si[425]
    DIRECTION INPUT ;
    USE SIGNAL ;
    PORT
      LAYER M4 ;
        RECT  0 43.44 0.084 43.464 ;
    END
  END si[425]
  PIN si[426]
    DIRECTION INPUT ;
    USE SIGNAL ;
    PORT
      LAYER M4 ;
        RECT  0 43.536 0.084 43.56 ;
    END
  END si[426]
  PIN si[427]
    DIRECTION INPUT ;
    USE SIGNAL ;
    PORT
      LAYER M4 ;
        RECT  0 43.632 0.084 43.656 ;
    END
  END si[427]
  PIN si[428]
    DIRECTION INPUT ;
    USE SIGNAL ;
    PORT
      LAYER M4 ;
        RECT  0 43.728 0.084 43.752 ;
    END
  END si[428]
  PIN si[429]
    DIRECTION INPUT ;
    USE SIGNAL ;
    PORT
      LAYER M4 ;
        RECT  0 43.824 0.084 43.848 ;
    END
  END si[429]
  PIN si[42]
    DIRECTION INPUT ;
    USE SIGNAL ;
    PORT
      LAYER M4 ;
        RECT  0 37.392 0.084 37.416 ;
    END
  END si[42]
  PIN si[430]
    DIRECTION INPUT ;
    USE SIGNAL ;
    PORT
      LAYER M4 ;
        RECT  0 43.92 0.084 43.944 ;
    END
  END si[430]
  PIN si[431]
    DIRECTION INPUT ;
    USE SIGNAL ;
    PORT
      LAYER M4 ;
        RECT  0 44.016 0.084 44.04 ;
    END
  END si[431]
  PIN si[432]
    DIRECTION INPUT ;
    USE SIGNAL ;
    PORT
      LAYER M4 ;
        RECT  0 44.112 0.084 44.136 ;
    END
  END si[432]
  PIN si[433]
    DIRECTION INPUT ;
    USE SIGNAL ;
    PORT
      LAYER M4 ;
        RECT  0 44.208 0.084 44.232 ;
    END
  END si[433]
  PIN si[434]
    DIRECTION INPUT ;
    USE SIGNAL ;
    PORT
      LAYER M4 ;
        RECT  0 44.304 0.084 44.328 ;
    END
  END si[434]
  PIN si[435]
    DIRECTION INPUT ;
    USE SIGNAL ;
    PORT
      LAYER M4 ;
        RECT  0 44.4 0.084 44.424 ;
    END
  END si[435]
  PIN si[436]
    DIRECTION INPUT ;
    USE SIGNAL ;
    PORT
      LAYER M4 ;
        RECT  0 44.496 0.084 44.52 ;
    END
  END si[436]
  PIN si[437]
    DIRECTION INPUT ;
    USE SIGNAL ;
    PORT
      LAYER M4 ;
        RECT  0 44.592 0.084 44.616 ;
    END
  END si[437]
  PIN si[438]
    DIRECTION INPUT ;
    USE SIGNAL ;
    PORT
      LAYER M4 ;
        RECT  0 44.688 0.084 44.712 ;
    END
  END si[438]
  PIN si[439]
    DIRECTION INPUT ;
    USE SIGNAL ;
    PORT
      LAYER M4 ;
        RECT  0 44.784 0.084 44.808 ;
    END
  END si[439]
  PIN si[43]
    DIRECTION INPUT ;
    USE SIGNAL ;
    PORT
      LAYER M4 ;
        RECT  0 37.488 0.084 37.512 ;
    END
  END si[43]
  PIN si[440]
    DIRECTION INPUT ;
    USE SIGNAL ;
    PORT
      LAYER M4 ;
        RECT  0 44.88 0.084 44.904 ;
    END
  END si[440]
  PIN si[441]
    DIRECTION INPUT ;
    USE SIGNAL ;
    PORT
      LAYER M4 ;
        RECT  0 44.976 0.084 45 ;
    END
  END si[441]
  PIN si[442]
    DIRECTION INPUT ;
    USE SIGNAL ;
    PORT
      LAYER M4 ;
        RECT  0 45.072 0.084 45.096 ;
    END
  END si[442]
  PIN si[443]
    DIRECTION INPUT ;
    USE SIGNAL ;
    PORT
      LAYER M4 ;
        RECT  0 45.168 0.084 45.192 ;
    END
  END si[443]
  PIN si[444]
    DIRECTION INPUT ;
    USE SIGNAL ;
    PORT
      LAYER M4 ;
        RECT  0 45.264 0.084 45.288 ;
    END
  END si[444]
  PIN si[445]
    DIRECTION INPUT ;
    USE SIGNAL ;
    PORT
      LAYER M4 ;
        RECT  0 45.36 0.084 45.384 ;
    END
  END si[445]
  PIN si[446]
    DIRECTION INPUT ;
    USE SIGNAL ;
    PORT
      LAYER M4 ;
        RECT  0 45.456 0.084 45.48 ;
    END
  END si[446]
  PIN si[447]
    DIRECTION INPUT ;
    USE SIGNAL ;
    PORT
      LAYER M4 ;
        RECT  0 45.552 0.084 45.576 ;
    END
  END si[447]
  PIN si[448]
    DIRECTION INPUT ;
    USE SIGNAL ;
    PORT
      LAYER M4 ;
        RECT  0 45.648 0.084 45.672 ;
    END
  END si[448]
  PIN si[449]
    DIRECTION INPUT ;
    USE SIGNAL ;
    PORT
      LAYER M4 ;
        RECT  0 45.744 0.084 45.768 ;
    END
  END si[449]
  PIN si[44]
    DIRECTION INPUT ;
    USE SIGNAL ;
    PORT
      LAYER M4 ;
        RECT  0 37.584 0.084 37.608 ;
    END
  END si[44]
  PIN si[450]
    DIRECTION INPUT ;
    USE SIGNAL ;
    PORT
      LAYER M4 ;
        RECT  0 45.84 0.084 45.864 ;
    END
  END si[450]
  PIN si[451]
    DIRECTION INPUT ;
    USE SIGNAL ;
    PORT
      LAYER M4 ;
        RECT  0 32.976 0.084 33 ;
    END
  END si[451]
  PIN si[452]
    DIRECTION INPUT ;
    USE SIGNAL ;
    PORT
      LAYER M4 ;
        RECT  0 33.072 0.084 33.096 ;
    END
  END si[452]
  PIN si[453]
    DIRECTION INPUT ;
    USE SIGNAL ;
    PORT
      LAYER M4 ;
        RECT  0 33.168 0.084 33.192 ;
    END
  END si[453]
  PIN si[454]
    DIRECTION INPUT ;
    USE SIGNAL ;
    PORT
      LAYER M4 ;
        RECT  0 33.264 0.084 33.288 ;
    END
  END si[454]
  PIN si[455]
    DIRECTION INPUT ;
    USE SIGNAL ;
    PORT
      LAYER M4 ;
        RECT  0 33.36 0.084 33.384 ;
    END
  END si[455]
  PIN si[456]
    DIRECTION INPUT ;
    USE SIGNAL ;
    PORT
      LAYER M4 ;
        RECT  0 33.456 0.084 33.48 ;
    END
  END si[456]
  PIN si[45]
    DIRECTION INPUT ;
    USE SIGNAL ;
    PORT
      LAYER M4 ;
        RECT  0 37.68 0.084 37.704 ;
    END
  END si[45]
  PIN si[46]
    DIRECTION INPUT ;
    USE SIGNAL ;
    PORT
      LAYER M4 ;
        RECT  0 37.776 0.084 37.8 ;
    END
  END si[46]
  PIN si[47]
    DIRECTION INPUT ;
    USE SIGNAL ;
    PORT
      LAYER M4 ;
        RECT  0 37.872 0.084 37.896 ;
    END
  END si[47]
  PIN si[48]
    DIRECTION INPUT ;
    USE SIGNAL ;
    PORT
      LAYER M4 ;
        RECT  0 37.968 0.084 37.992 ;
    END
  END si[48]
  PIN si[49]
    DIRECTION INPUT ;
    USE SIGNAL ;
    PORT
      LAYER M4 ;
        RECT  0 38.064 0.084 38.088 ;
    END
  END si[49]
  PIN si[4]
    DIRECTION INPUT ;
    USE SIGNAL ;
    PORT
      LAYER M4 ;
        RECT  0 56.016 0.084 56.04 ;
    END
  END si[4]
  PIN si[50]
    DIRECTION INPUT ;
    USE SIGNAL ;
    PORT
      LAYER M4 ;
        RECT  0 38.16 0.084 38.184 ;
    END
  END si[50]
  PIN si[51]
    DIRECTION INPUT ;
    USE SIGNAL ;
    PORT
      LAYER M4 ;
        RECT  0 38.256 0.084 38.28 ;
    END
  END si[51]
  PIN si[52]
    DIRECTION INPUT ;
    USE SIGNAL ;
    PORT
      LAYER M4 ;
        RECT  0 38.352 0.084 38.376 ;
    END
  END si[52]
  PIN si[53]
    DIRECTION INPUT ;
    USE SIGNAL ;
    PORT
      LAYER M4 ;
        RECT  0 38.448 0.084 38.472 ;
    END
  END si[53]
  PIN si[54]
    DIRECTION INPUT ;
    USE SIGNAL ;
    PORT
      LAYER M4 ;
        RECT  0 38.544 0.084 38.568 ;
    END
  END si[54]
  PIN si[55]
    DIRECTION INPUT ;
    USE SIGNAL ;
    PORT
      LAYER M4 ;
        RECT  0 38.64 0.084 38.664 ;
    END
  END si[55]
  PIN si[56]
    DIRECTION INPUT ;
    USE SIGNAL ;
    PORT
      LAYER M4 ;
        RECT  0 38.736 0.084 38.76 ;
    END
  END si[56]
  PIN si[57]
    DIRECTION INPUT ;
    USE SIGNAL ;
    PORT
      LAYER M4 ;
        RECT  0 38.832 0.084 38.856 ;
    END
  END si[57]
  PIN si[58]
    DIRECTION INPUT ;
    USE SIGNAL ;
    PORT
      LAYER M4 ;
        RECT  0 38.928 0.084 38.952 ;
    END
  END si[58]
  PIN si[59]
    DIRECTION INPUT ;
    USE SIGNAL ;
    PORT
      LAYER M4 ;
        RECT  0 39.024 0.084 39.048 ;
    END
  END si[59]
  PIN si[5]
    DIRECTION INPUT ;
    USE SIGNAL ;
    PORT
      LAYER M4 ;
        RECT  0 56.112 0.084 56.136 ;
    END
  END si[5]
  PIN si[60]
    DIRECTION INPUT ;
    USE SIGNAL ;
    PORT
      LAYER M4 ;
        RECT  0 39.12 0.084 39.144 ;
    END
  END si[60]
  PIN si[61]
    DIRECTION INPUT ;
    USE SIGNAL ;
    PORT
      LAYER M4 ;
        RECT  0 39.216 0.084 39.24 ;
    END
  END si[61]
  PIN si[62]
    DIRECTION INPUT ;
    USE SIGNAL ;
    PORT
      LAYER M4 ;
        RECT  0 39.312 0.084 39.336 ;
    END
  END si[62]
  PIN si[63]
    DIRECTION INPUT ;
    USE SIGNAL ;
    PORT
      LAYER M4 ;
        RECT  0 39.408 0.084 39.432 ;
    END
  END si[63]
  PIN si[64]
    DIRECTION INPUT ;
    USE SIGNAL ;
    PORT
      LAYER M4 ;
        RECT  0 39.504 0.084 39.528 ;
    END
  END si[64]
  PIN si[65]
    DIRECTION INPUT ;
    USE SIGNAL ;
    PORT
      LAYER M4 ;
        RECT  0 39.6 0.084 39.624 ;
    END
  END si[65]
  PIN si[66]
    DIRECTION INPUT ;
    USE SIGNAL ;
    PORT
      LAYER M4 ;
        RECT  0 39.696 0.084 39.72 ;
    END
  END si[66]
  PIN si[67]
    DIRECTION INPUT ;
    USE SIGNAL ;
    PORT
      LAYER M4 ;
        RECT  0 33.648 0.084 33.672 ;
    END
  END si[67]
  PIN si[68]
    DIRECTION INPUT ;
    USE SIGNAL ;
    PORT
      LAYER M4 ;
        RECT  0 33.744 0.084 33.768 ;
    END
  END si[68]
  PIN si[69]
    DIRECTION INPUT ;
    USE SIGNAL ;
    PORT
      LAYER M4 ;
        RECT  0 33.84 0.084 33.864 ;
    END
  END si[69]
  PIN si[6]
    DIRECTION INPUT ;
    USE SIGNAL ;
    PORT
      LAYER M4 ;
        RECT  0 56.208 0.084 56.232 ;
    END
  END si[6]
  PIN si[70]
    DIRECTION INPUT ;
    USE SIGNAL ;
    PORT
      LAYER M4 ;
        RECT  0 33.936 0.084 33.96 ;
    END
  END si[70]
  PIN si[71]
    DIRECTION INPUT ;
    USE SIGNAL ;
    PORT
      LAYER M4 ;
        RECT  0 34.032 0.084 34.056 ;
    END
  END si[71]
  PIN si[72]
    DIRECTION INPUT ;
    USE SIGNAL ;
    PORT
      LAYER M4 ;
        RECT  0 34.128 0.084 34.152 ;
    END
  END si[72]
  PIN si[73]
    DIRECTION INPUT ;
    USE SIGNAL ;
    PORT
      LAYER M4 ;
        RECT  0 34.224 0.084 34.248 ;
    END
  END si[73]
  PIN si[74]
    DIRECTION INPUT ;
    USE SIGNAL ;
    PORT
      LAYER M4 ;
        RECT  0 34.32 0.084 34.344 ;
    END
  END si[74]
  PIN si[75]
    DIRECTION INPUT ;
    USE SIGNAL ;
    PORT
      LAYER M4 ;
        RECT  0 34.416 0.084 34.44 ;
    END
  END si[75]
  PIN si[76]
    DIRECTION INPUT ;
    USE SIGNAL ;
    PORT
      LAYER M4 ;
        RECT  0 34.512 0.084 34.536 ;
    END
  END si[76]
  PIN si[77]
    DIRECTION INPUT ;
    USE SIGNAL ;
    PORT
      LAYER M4 ;
        RECT  0 34.608 0.084 34.632 ;
    END
  END si[77]
  PIN si[78]
    DIRECTION INPUT ;
    USE SIGNAL ;
    PORT
      LAYER M4 ;
        RECT  0 34.704 0.084 34.728 ;
    END
  END si[78]
  PIN si[79]
    DIRECTION INPUT ;
    USE SIGNAL ;
    PORT
      LAYER M4 ;
        RECT  0 34.8 0.084 34.824 ;
    END
  END si[79]
  PIN si[7]
    DIRECTION INPUT ;
    USE SIGNAL ;
    PORT
      LAYER M4 ;
        RECT  0 56.304 0.084 56.328 ;
    END
  END si[7]
  PIN si[80]
    DIRECTION INPUT ;
    USE SIGNAL ;
    PORT
      LAYER M4 ;
        RECT  0 34.896 0.084 34.92 ;
    END
  END si[80]
  PIN si[81]
    DIRECTION INPUT ;
    USE SIGNAL ;
    PORT
      LAYER M4 ;
        RECT  0 34.992 0.084 35.016 ;
    END
  END si[81]
  PIN si[82]
    DIRECTION INPUT ;
    USE SIGNAL ;
    PORT
      LAYER M4 ;
        RECT  0 35.088 0.084 35.112 ;
    END
  END si[82]
  PIN si[83]
    DIRECTION INPUT ;
    USE SIGNAL ;
    PORT
      LAYER M4 ;
        RECT  0 35.184 0.084 35.208 ;
    END
  END si[83]
  PIN si[84]
    DIRECTION INPUT ;
    USE SIGNAL ;
    PORT
      LAYER M4 ;
        RECT  0 35.28 0.084 35.304 ;
    END
  END si[84]
  PIN si[85]
    DIRECTION INPUT ;
    USE SIGNAL ;
    PORT
      LAYER M4 ;
        RECT  0 35.376 0.084 35.4 ;
    END
  END si[85]
  PIN si[86]
    DIRECTION INPUT ;
    USE SIGNAL ;
    PORT
      LAYER M4 ;
        RECT  0 35.472 0.084 35.496 ;
    END
  END si[86]
  PIN si[87]
    DIRECTION INPUT ;
    USE SIGNAL ;
    PORT
      LAYER M4 ;
        RECT  0 35.568 0.084 35.592 ;
    END
  END si[87]
  PIN si[88]
    DIRECTION INPUT ;
    USE SIGNAL ;
    PORT
      LAYER M4 ;
        RECT  0 35.664 0.084 35.688 ;
    END
  END si[88]
  PIN si[89]
    DIRECTION INPUT ;
    USE SIGNAL ;
    PORT
      LAYER M4 ;
        RECT  0 35.76 0.084 35.784 ;
    END
  END si[89]
  PIN si[8]
    DIRECTION INPUT ;
    USE SIGNAL ;
    PORT
      LAYER M4 ;
        RECT  0 56.4 0.084 56.424 ;
    END
  END si[8]
  PIN si[90]
    DIRECTION INPUT ;
    USE SIGNAL ;
    PORT
      LAYER M4 ;
        RECT  0 35.856 0.084 35.88 ;
    END
  END si[90]
  PIN si[91]
    DIRECTION INPUT ;
    USE SIGNAL ;
    PORT
      LAYER M4 ;
        RECT  0 35.952 0.084 35.976 ;
    END
  END si[91]
  PIN si[92]
    DIRECTION INPUT ;
    USE SIGNAL ;
    PORT
      LAYER M4 ;
        RECT  0 36.048 0.084 36.072 ;
    END
  END si[92]
  PIN si[93]
    DIRECTION INPUT ;
    USE SIGNAL ;
    PORT
      LAYER M4 ;
        RECT  0 36.144 0.084 36.168 ;
    END
  END si[93]
  PIN si[94]
    DIRECTION INPUT ;
    USE SIGNAL ;
    PORT
      LAYER M4 ;
        RECT  0 36.24 0.084 36.264 ;
    END
  END si[94]
  PIN si[95]
    DIRECTION INPUT ;
    USE SIGNAL ;
    PORT
      LAYER M4 ;
        RECT  0 36.336 0.084 36.36 ;
    END
  END si[95]
  PIN si[96]
    DIRECTION INPUT ;
    USE SIGNAL ;
    PORT
      LAYER M4 ;
        RECT  0 36.432 0.084 36.456 ;
    END
  END si[96]
  PIN si[97]
    DIRECTION INPUT ;
    USE SIGNAL ;
    PORT
      LAYER M4 ;
        RECT  0 36.528 0.084 36.552 ;
    END
  END si[97]
  PIN si[98]
    DIRECTION INPUT ;
    USE SIGNAL ;
    PORT
      LAYER M4 ;
        RECT  0 36.624 0.084 36.648 ;
    END
  END si[98]
  PIN si[99]
    DIRECTION INPUT ;
    USE SIGNAL ;
    PORT
      LAYER M4 ;
        RECT  0 62.064 0.084 62.088 ;
    END
  END si[99]
  PIN si[9]
    DIRECTION INPUT ;
    USE SIGNAL ;
    PORT
      LAYER M4 ;
        RECT  0 56.496 0.084 56.52 ;
    END
  END si[9]
  PIN start
    DIRECTION INPUT ;
    USE SIGNAL ;
    PORT
      LAYER M4 ;
        RECT  0 33.552 0.084 33.576 ;
    END
  END start
  PIN su_fault
    DIRECTION OUTPUT ;
    USE SIGNAL ;
    PORT
      LAYER M5 ;
        RECT  46.224 0 46.248 0.084 ;
    END
  END su_fault
  PIN su_idle
    DIRECTION OUTPUT ;
    USE SIGNAL ;
    PORT
      LAYER M5 ;
        RECT  46.32 0 46.344 0.084 ;
    END
  END su_idle
  PIN su_nr
    DIRECTION OUTPUT ;
    USE SIGNAL ;
    PORT
      LAYER M5 ;
        RECT  46.416 0 46.44 0.084 ;
    END
  END su_nr
  PIN su_prog[0]
    DIRECTION OUTPUT ;
    USE SIGNAL ;
    PORT
      LAYER M5 ;
        RECT  46.512 0 46.536 0.084 ;
    END
  END su_prog[0]
  PIN su_prog[10]
    DIRECTION OUTPUT ;
    USE SIGNAL ;
    PORT
      LAYER M5 ;
        RECT  47.472 0 47.496 0.084 ;
    END
  END su_prog[10]
  PIN su_prog[11]
    DIRECTION OUTPUT ;
    USE SIGNAL ;
    PORT
      LAYER M5 ;
        RECT  47.568 0 47.592 0.084 ;
    END
  END su_prog[11]
  PIN su_prog[12]
    DIRECTION OUTPUT ;
    USE SIGNAL ;
    PORT
      LAYER M5 ;
        RECT  47.664 0 47.688 0.084 ;
    END
  END su_prog[12]
  PIN su_prog[13]
    DIRECTION OUTPUT ;
    USE SIGNAL ;
    PORT
      LAYER M5 ;
        RECT  47.76 0 47.784 0.084 ;
    END
  END su_prog[13]
  PIN su_prog[14]
    DIRECTION OUTPUT ;
    USE SIGNAL ;
    PORT
      LAYER M5 ;
        RECT  47.856 0 47.88 0.084 ;
    END
  END su_prog[14]
  PIN su_prog[15]
    DIRECTION OUTPUT ;
    USE SIGNAL ;
    PORT
      LAYER M5 ;
        RECT  47.952 0 47.976 0.084 ;
    END
  END su_prog[15]
  PIN su_prog[1]
    DIRECTION OUTPUT ;
    USE SIGNAL ;
    PORT
      LAYER M5 ;
        RECT  46.608 0 46.632 0.084 ;
    END
  END su_prog[1]
  PIN su_prog[2]
    DIRECTION OUTPUT ;
    USE SIGNAL ;
    PORT
      LAYER M5 ;
        RECT  46.704 0 46.728 0.084 ;
    END
  END su_prog[2]
  PIN su_prog[3]
    DIRECTION OUTPUT ;
    USE SIGNAL ;
    PORT
      LAYER M5 ;
        RECT  46.8 0 46.824 0.084 ;
    END
  END su_prog[3]
  PIN su_prog[4]
    DIRECTION OUTPUT ;
    USE SIGNAL ;
    PORT
      LAYER M5 ;
        RECT  46.896 0 46.92 0.084 ;
    END
  END su_prog[4]
  PIN su_prog[5]
    DIRECTION OUTPUT ;
    USE SIGNAL ;
    PORT
      LAYER M5 ;
        RECT  46.992 0 47.016 0.084 ;
    END
  END su_prog[5]
  PIN su_prog[6]
    DIRECTION OUTPUT ;
    USE SIGNAL ;
    PORT
      LAYER M5 ;
        RECT  47.088 0 47.112 0.084 ;
    END
  END su_prog[6]
  PIN su_prog[7]
    DIRECTION OUTPUT ;
    USE SIGNAL ;
    PORT
      LAYER M5 ;
        RECT  47.184 0 47.208 0.084 ;
    END
  END su_prog[7]
  PIN su_prog[8]
    DIRECTION OUTPUT ;
    USE SIGNAL ;
    PORT
      LAYER M5 ;
        RECT  47.28 0 47.304 0.084 ;
    END
  END su_prog[8]
  PIN su_prog[9]
    DIRECTION OUTPUT ;
    USE SIGNAL ;
    PORT
      LAYER M5 ;
        RECT  47.376 0 47.4 0.084 ;
    END
  END su_prog[9]
  PIN su_rows[0]
    DIRECTION OUTPUT ;
    USE SIGNAL ;
    PORT
      LAYER M5 ;
        RECT  48.048 0 48.072 0.084 ;
    END
  END su_rows[0]
  PIN su_rows[10]
    DIRECTION OUTPUT ;
    USE SIGNAL ;
    PORT
      LAYER M5 ;
        RECT  42.864 0 42.888 0.084 ;
    END
  END su_rows[10]
  PIN su_rows[11]
    DIRECTION OUTPUT ;
    USE SIGNAL ;
    PORT
      LAYER M5 ;
        RECT  42.96 0 42.984 0.084 ;
    END
  END su_rows[11]
  PIN su_rows[12]
    DIRECTION OUTPUT ;
    USE SIGNAL ;
    PORT
      LAYER M5 ;
        RECT  43.056 0 43.08 0.084 ;
    END
  END su_rows[12]
  PIN su_rows[13]
    DIRECTION OUTPUT ;
    USE SIGNAL ;
    PORT
      LAYER M5 ;
        RECT  43.152 0 43.176 0.084 ;
    END
  END su_rows[13]
  PIN su_rows[14]
    DIRECTION OUTPUT ;
    USE SIGNAL ;
    PORT
      LAYER M5 ;
        RECT  43.248 0 43.272 0.084 ;
    END
  END su_rows[14]
  PIN su_rows[15]
    DIRECTION OUTPUT ;
    USE SIGNAL ;
    PORT
      LAYER M5 ;
        RECT  43.344 0 43.368 0.084 ;
    END
  END su_rows[15]
  PIN su_rows[1]
    DIRECTION OUTPUT ;
    USE SIGNAL ;
    PORT
      LAYER M5 ;
        RECT  48.144 0 48.168 0.084 ;
    END
  END su_rows[1]
  PIN su_rows[2]
    DIRECTION OUTPUT ;
    USE SIGNAL ;
    PORT
      LAYER M5 ;
        RECT  48.24 0 48.264 0.084 ;
    END
  END su_rows[2]
  PIN su_rows[3]
    DIRECTION OUTPUT ;
    USE SIGNAL ;
    PORT
      LAYER M5 ;
        RECT  42.192 0 42.216 0.084 ;
    END
  END su_rows[3]
  PIN su_rows[4]
    DIRECTION OUTPUT ;
    USE SIGNAL ;
    PORT
      LAYER M5 ;
        RECT  42.288 0 42.312 0.084 ;
    END
  END su_rows[4]
  PIN su_rows[5]
    DIRECTION OUTPUT ;
    USE SIGNAL ;
    PORT
      LAYER M5 ;
        RECT  42.384 0 42.408 0.084 ;
    END
  END su_rows[5]
  PIN su_rows[6]
    DIRECTION OUTPUT ;
    USE SIGNAL ;
    PORT
      LAYER M5 ;
        RECT  42.48 0 42.504 0.084 ;
    END
  END su_rows[6]
  PIN su_rows[7]
    DIRECTION OUTPUT ;
    USE SIGNAL ;
    PORT
      LAYER M5 ;
        RECT  42.576 0 42.6 0.084 ;
    END
  END su_rows[7]
  PIN su_rows[8]
    DIRECTION OUTPUT ;
    USE SIGNAL ;
    PORT
      LAYER M5 ;
        RECT  42.672 0 42.696 0.084 ;
    END
  END su_rows[8]
  PIN su_rows[9]
    DIRECTION OUTPUT ;
    USE SIGNAL ;
    PORT
      LAYER M5 ;
        RECT  42.768 0 42.792 0.084 ;
    END
  END su_rows[9]
  PIN VSS
    DIRECTION INOUT ;
    USE GROUND ;
    PORT
      LAYER M5 ;
        RECT  166.164 4.297 166.284 125.303 ;
        RECT  161.844 4.297 161.964 125.303 ;
        RECT  157.524 4.297 157.644 125.303 ;
        RECT  153.204 4.297 153.324 125.303 ;
        RECT  148.884 4.297 149.004 125.303 ;
        RECT  144.564 4.297 144.684 125.303 ;
        RECT  140.244 4.297 140.364 125.303 ;
        RECT  135.924 4.297 136.044 125.303 ;
        RECT  131.604 4.297 131.724 125.303 ;
        RECT  127.284 4.297 127.404 125.303 ;
        RECT  122.964 4.297 123.084 125.303 ;
        RECT  118.644 4.297 118.764 125.303 ;
        RECT  114.324 4.297 114.444 125.303 ;
        RECT  110.004 4.297 110.124 125.303 ;
        RECT  105.684 4.297 105.804 125.303 ;
        RECT  101.364 4.297 101.484 125.303 ;
        RECT  97.044 4.297 97.164 125.303 ;
        RECT  92.724 4.297 92.844 125.303 ;
        RECT  88.404 4.297 88.524 125.303 ;
        RECT  84.084 4.297 84.204 125.303 ;
        RECT  79.764 4.297 79.884 125.303 ;
        RECT  75.444 4.297 75.564 125.303 ;
        RECT  71.124 4.297 71.244 125.303 ;
        RECT  66.804 4.297 66.924 125.303 ;
        RECT  62.484 4.297 62.604 125.303 ;
        RECT  58.164 4.297 58.284 125.303 ;
        RECT  53.844 4.297 53.964 125.303 ;
        RECT  49.524 4.297 49.644 125.303 ;
        RECT  45.204 4.297 45.324 125.303 ;
        RECT  40.884 4.297 41.004 125.303 ;
        RECT  36.564 4.297 36.684 125.303 ;
        RECT  32.244 4.297 32.364 125.303 ;
        RECT  27.924 4.297 28.044 125.303 ;
        RECT  23.604 4.297 23.724 125.303 ;
        RECT  19.284 4.297 19.404 125.303 ;
        RECT  14.964 4.297 15.084 125.303 ;
        RECT  10.644 4.297 10.764 125.303 ;
        RECT  6.324 4.297 6.444 125.303 ;
    END
  END VSS
  PIN VDD
    DIRECTION INOUT ;
    USE POWER ;
    PORT
      LAYER M5 ;
        RECT  166.356 4.311 166.476 125.289 ;
        RECT  162.036 4.311 162.156 125.289 ;
        RECT  157.716 4.311 157.836 125.289 ;
        RECT  153.396 4.311 153.516 125.289 ;
        RECT  149.076 4.311 149.196 125.289 ;
        RECT  144.756 4.311 144.876 125.289 ;
        RECT  140.436 4.311 140.556 125.289 ;
        RECT  136.116 4.311 136.236 125.289 ;
        RECT  131.796 4.311 131.916 125.289 ;
        RECT  127.476 4.311 127.596 125.289 ;
        RECT  123.156 4.311 123.276 125.289 ;
        RECT  118.836 4.311 118.956 125.289 ;
        RECT  114.516 4.311 114.636 125.289 ;
        RECT  110.196 4.311 110.316 125.289 ;
        RECT  105.876 4.311 105.996 125.289 ;
        RECT  101.556 4.311 101.676 125.289 ;
        RECT  97.236 4.311 97.356 125.289 ;
        RECT  92.916 4.311 93.036 125.289 ;
        RECT  88.596 4.311 88.716 125.289 ;
        RECT  84.276 4.311 84.396 125.289 ;
        RECT  79.956 4.311 80.076 125.289 ;
        RECT  75.636 4.311 75.756 125.289 ;
        RECT  71.316 4.311 71.436 125.289 ;
        RECT  66.996 4.311 67.116 125.289 ;
        RECT  62.676 4.311 62.796 125.289 ;
        RECT  58.356 4.311 58.476 125.289 ;
        RECT  54.036 4.311 54.156 125.289 ;
        RECT  49.716 4.311 49.836 125.289 ;
        RECT  45.396 4.311 45.516 125.289 ;
        RECT  41.076 4.311 41.196 125.289 ;
        RECT  36.756 4.311 36.876 125.289 ;
        RECT  32.436 4.311 32.556 125.289 ;
        RECT  28.116 4.311 28.236 125.289 ;
        RECT  23.796 4.311 23.916 125.289 ;
        RECT  19.476 4.311 19.596 125.289 ;
        RECT  15.156 4.311 15.276 125.289 ;
        RECT  10.836 4.311 10.956 125.289 ;
        RECT  6.516 4.311 6.636 125.289 ;
    END
  END VDD
  OBS
    LAYER RVTN ;
     RECT  0 0 172.8 129.6 ;
    LAYER RVTP ;
     RECT  0 0 172.8 129.6 ;
    LAYER M1 ;
     RECT  0 0 172.8 129.6 ;
    LAYER M2 ;
     RECT  0 0 172.8 129.6 ;
    LAYER M3 ;
     RECT  0 0 172.8 129.6 ;
    LAYER M4 ;
     RECT  0 0 172.8 129.6 ;
    LAYER M5 ;
     RECT  0 0 172.8 129.6 ;
  END
END qfd_dv_s5_su8_rst3
END LIBRARY
